VERSION 5.7 ;
  NOWIREEXTENSIONATPIN ON ;
  DIVIDERCHAR "/" ;
  BUSBITCHARS "[]" ;
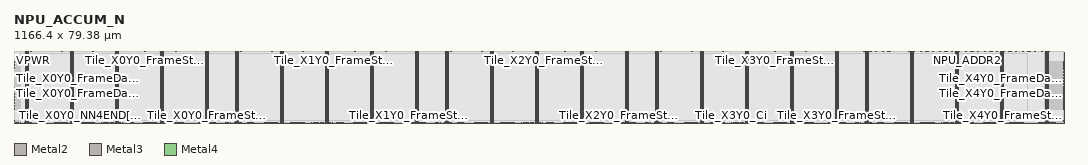
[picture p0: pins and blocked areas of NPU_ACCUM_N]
MACRO NPU_ACCUM_N
  CLASS BLOCK ;
  FOREIGN NPU_ACCUM_N ;
  ORIGIN 0.000 0.000 ;
  SIZE 1166.400 BY 79.380 ;
  PIN NPU_ADDR0
    DIRECTION OUTPUT ;
    USE SIGNAL ;
    ANTENNADIFFAREA 2.647800 ;
    PORT
      LAYER Metal2 ;
        RECT 1055.320 78.980 1055.720 79.380 ;
    END
  END NPU_ADDR0
  PIN NPU_ADDR1
    DIRECTION OUTPUT ;
    USE SIGNAL ;
    ANTENNADIFFAREA 2.647800 ;
    PORT
      LAYER Metal2 ;
        RECT 1057.240 78.980 1057.640 79.380 ;
    END
  END NPU_ADDR1
  PIN NPU_ADDR2
    DIRECTION OUTPUT ;
    USE SIGNAL ;
    ANTENNADIFFAREA 2.647800 ;
    PORT
      LAYER Metal2 ;
        RECT 1059.160 78.980 1059.560 79.380 ;
    END
  END NPU_ADDR2
  PIN NPU_ADDR3
    DIRECTION OUTPUT ;
    USE SIGNAL ;
    ANTENNADIFFAREA 2.647800 ;
    PORT
      LAYER Metal2 ;
        RECT 1061.080 78.980 1061.480 79.380 ;
    END
  END NPU_ADDR3
  PIN NPU_ADDR4
    DIRECTION OUTPUT ;
    USE SIGNAL ;
    ANTENNADIFFAREA 2.647800 ;
    PORT
      LAYER Metal2 ;
        RECT 1063.000 78.980 1063.400 79.380 ;
    END
  END NPU_ADDR4
  PIN NPU_ADDR5
    DIRECTION OUTPUT ;
    USE SIGNAL ;
    ANTENNADIFFAREA 2.647800 ;
    PORT
      LAYER Metal2 ;
        RECT 1064.920 78.980 1065.320 79.380 ;
    END
  END NPU_ADDR5
  PIN NPU_ADDR6
    DIRECTION OUTPUT ;
    USE SIGNAL ;
    ANTENNADIFFAREA 2.647800 ;
    PORT
      LAYER Metal2 ;
        RECT 1066.840 78.980 1067.240 79.380 ;
    END
  END NPU_ADDR6
  PIN NPU_ADDR7
    DIRECTION OUTPUT ;
    USE SIGNAL ;
    ANTENNADIFFAREA 2.647800 ;
    PORT
      LAYER Metal2 ;
        RECT 1068.760 78.980 1069.160 79.380 ;
    END
  END NPU_ADDR7
  PIN NPU_RDATA0
    DIRECTION INPUT ;
    USE SIGNAL ;
    ANTENNAGATEAREA 0.109200 ;
    ANTENNADIFFAREA 2.015400 ;
    PORT
      LAYER Metal2 ;
        RECT 993.880 78.980 994.280 79.380 ;
    END
  END NPU_RDATA0
  PIN NPU_RDATA1
    DIRECTION INPUT ;
    USE SIGNAL ;
    ANTENNAGATEAREA 0.109200 ;
    ANTENNADIFFAREA 2.015400 ;
    PORT
      LAYER Metal2 ;
        RECT 995.800 78.980 996.200 79.380 ;
    END
  END NPU_RDATA1
  PIN NPU_RDATA10
    DIRECTION INPUT ;
    USE SIGNAL ;
    ANTENNAGATEAREA 0.109200 ;
    ANTENNADIFFAREA 2.015400 ;
    PORT
      LAYER Metal2 ;
        RECT 1013.080 78.980 1013.480 79.380 ;
    END
  END NPU_RDATA10
  PIN NPU_RDATA11
    DIRECTION INPUT ;
    USE SIGNAL ;
    ANTENNAGATEAREA 0.109200 ;
    ANTENNADIFFAREA 2.015400 ;
    PORT
      LAYER Metal2 ;
        RECT 1015.000 78.980 1015.400 79.380 ;
    END
  END NPU_RDATA11
  PIN NPU_RDATA12
    DIRECTION INPUT ;
    USE SIGNAL ;
    ANTENNAGATEAREA 0.109200 ;
    ANTENNADIFFAREA 2.015400 ;
    PORT
      LAYER Metal2 ;
        RECT 1016.920 78.980 1017.320 79.380 ;
    END
  END NPU_RDATA12
  PIN NPU_RDATA13
    DIRECTION INPUT ;
    USE SIGNAL ;
    ANTENNAGATEAREA 0.109200 ;
    ANTENNADIFFAREA 2.015400 ;
    PORT
      LAYER Metal2 ;
        RECT 1018.840 78.980 1019.240 79.380 ;
    END
  END NPU_RDATA13
  PIN NPU_RDATA14
    DIRECTION INPUT ;
    USE SIGNAL ;
    ANTENNAGATEAREA 0.109200 ;
    ANTENNADIFFAREA 2.015400 ;
    PORT
      LAYER Metal2 ;
        RECT 1020.760 78.980 1021.160 79.380 ;
    END
  END NPU_RDATA14
  PIN NPU_RDATA15
    DIRECTION INPUT ;
    USE SIGNAL ;
    ANTENNAGATEAREA 0.109200 ;
    ANTENNADIFFAREA 2.015400 ;
    PORT
      LAYER Metal2 ;
        RECT 1022.680 78.980 1023.080 79.380 ;
    END
  END NPU_RDATA15
  PIN NPU_RDATA16
    DIRECTION INPUT ;
    USE SIGNAL ;
    ANTENNAGATEAREA 0.109200 ;
    ANTENNADIFFAREA 2.015400 ;
    PORT
      LAYER Metal2 ;
        RECT 1024.600 78.980 1025.000 79.380 ;
    END
  END NPU_RDATA16
  PIN NPU_RDATA17
    DIRECTION INPUT ;
    USE SIGNAL ;
    ANTENNAGATEAREA 0.109200 ;
    ANTENNADIFFAREA 2.015400 ;
    PORT
      LAYER Metal2 ;
        RECT 1026.520 78.980 1026.920 79.380 ;
    END
  END NPU_RDATA17
  PIN NPU_RDATA18
    DIRECTION INPUT ;
    USE SIGNAL ;
    ANTENNAGATEAREA 0.109200 ;
    ANTENNADIFFAREA 2.015400 ;
    PORT
      LAYER Metal2 ;
        RECT 1028.440 78.980 1028.840 79.380 ;
    END
  END NPU_RDATA18
  PIN NPU_RDATA19
    DIRECTION INPUT ;
    USE SIGNAL ;
    ANTENNAGATEAREA 0.109200 ;
    ANTENNADIFFAREA 2.015400 ;
    PORT
      LAYER Metal2 ;
        RECT 1030.360 78.980 1030.760 79.380 ;
    END
  END NPU_RDATA19
  PIN NPU_RDATA2
    DIRECTION INPUT ;
    USE SIGNAL ;
    ANTENNAGATEAREA 0.109200 ;
    ANTENNADIFFAREA 2.015400 ;
    PORT
      LAYER Metal2 ;
        RECT 997.720 78.980 998.120 79.380 ;
    END
  END NPU_RDATA2
  PIN NPU_RDATA20
    DIRECTION INPUT ;
    USE SIGNAL ;
    ANTENNAGATEAREA 0.109200 ;
    ANTENNADIFFAREA 2.015400 ;
    PORT
      LAYER Metal2 ;
        RECT 1032.280 78.980 1032.680 79.380 ;
    END
  END NPU_RDATA20
  PIN NPU_RDATA21
    DIRECTION INPUT ;
    USE SIGNAL ;
    ANTENNAGATEAREA 0.109200 ;
    ANTENNADIFFAREA 2.015400 ;
    PORT
      LAYER Metal2 ;
        RECT 1034.200 78.980 1034.600 79.380 ;
    END
  END NPU_RDATA21
  PIN NPU_RDATA22
    DIRECTION INPUT ;
    USE SIGNAL ;
    ANTENNAGATEAREA 0.109200 ;
    ANTENNADIFFAREA 2.015400 ;
    PORT
      LAYER Metal2 ;
        RECT 1036.120 78.980 1036.520 79.380 ;
    END
  END NPU_RDATA22
  PIN NPU_RDATA23
    DIRECTION INPUT ;
    USE SIGNAL ;
    ANTENNAGATEAREA 0.109200 ;
    ANTENNADIFFAREA 4.030800 ;
    PORT
      LAYER Metal2 ;
        RECT 1038.040 78.980 1038.440 79.380 ;
    END
  END NPU_RDATA23
  PIN NPU_RDATA24
    DIRECTION INPUT ;
    USE SIGNAL ;
    ANTENNAGATEAREA 0.109200 ;
    ANTENNADIFFAREA 6.046200 ;
    PORT
      LAYER Metal2 ;
        RECT 1039.960 78.980 1040.360 79.380 ;
    END
  END NPU_RDATA24
  PIN NPU_RDATA25
    DIRECTION INPUT ;
    USE SIGNAL ;
    ANTENNAGATEAREA 0.109200 ;
    ANTENNADIFFAREA 2.015400 ;
    PORT
      LAYER Metal2 ;
        RECT 1041.880 78.980 1042.280 79.380 ;
    END
  END NPU_RDATA25
  PIN NPU_RDATA26
    DIRECTION INPUT ;
    USE SIGNAL ;
    ANTENNAGATEAREA 0.109200 ;
    ANTENNADIFFAREA 6.046200 ;
    PORT
      LAYER Metal2 ;
        RECT 1043.800 78.980 1044.200 79.380 ;
    END
  END NPU_RDATA26
  PIN NPU_RDATA27
    DIRECTION INPUT ;
    USE SIGNAL ;
    ANTENNAGATEAREA 0.109200 ;
    ANTENNADIFFAREA 2.015400 ;
    PORT
      LAYER Metal2 ;
        RECT 1045.720 78.980 1046.120 79.380 ;
    END
  END NPU_RDATA27
  PIN NPU_RDATA28
    DIRECTION INPUT ;
    USE SIGNAL ;
    ANTENNAGATEAREA 0.109200 ;
    ANTENNADIFFAREA 2.015400 ;
    PORT
      LAYER Metal2 ;
        RECT 1047.640 78.980 1048.040 79.380 ;
    END
  END NPU_RDATA28
  PIN NPU_RDATA29
    DIRECTION INPUT ;
    USE SIGNAL ;
    ANTENNAGATEAREA 0.109200 ;
    ANTENNADIFFAREA 2.015400 ;
    PORT
      LAYER Metal2 ;
        RECT 1049.560 78.980 1049.960 79.380 ;
    END
  END NPU_RDATA29
  PIN NPU_RDATA3
    DIRECTION INPUT ;
    USE SIGNAL ;
    ANTENNAGATEAREA 0.109200 ;
    ANTENNADIFFAREA 2.015400 ;
    PORT
      LAYER Metal2 ;
        RECT 999.640 78.980 1000.040 79.380 ;
    END
  END NPU_RDATA3
  PIN NPU_RDATA30
    DIRECTION INPUT ;
    USE SIGNAL ;
    ANTENNAGATEAREA 0.109200 ;
    ANTENNADIFFAREA 2.015400 ;
    PORT
      LAYER Metal2 ;
        RECT 1051.480 78.980 1051.880 79.380 ;
    END
  END NPU_RDATA30
  PIN NPU_RDATA31
    DIRECTION INPUT ;
    USE SIGNAL ;
    ANTENNAGATEAREA 0.109200 ;
    ANTENNADIFFAREA 2.015400 ;
    PORT
      LAYER Metal2 ;
        RECT 1053.400 78.980 1053.800 79.380 ;
    END
  END NPU_RDATA31
  PIN NPU_RDATA4
    DIRECTION INPUT ;
    USE SIGNAL ;
    ANTENNAGATEAREA 0.109200 ;
    ANTENNADIFFAREA 2.015400 ;
    PORT
      LAYER Metal2 ;
        RECT 1001.560 78.980 1001.960 79.380 ;
    END
  END NPU_RDATA4
  PIN NPU_RDATA5
    DIRECTION INPUT ;
    USE SIGNAL ;
    ANTENNAGATEAREA 0.109200 ;
    ANTENNADIFFAREA 2.015400 ;
    PORT
      LAYER Metal2 ;
        RECT 1003.480 78.980 1003.880 79.380 ;
    END
  END NPU_RDATA5
  PIN NPU_RDATA6
    DIRECTION INPUT ;
    USE SIGNAL ;
    ANTENNAGATEAREA 0.109200 ;
    ANTENNADIFFAREA 2.015400 ;
    PORT
      LAYER Metal2 ;
        RECT 1005.400 78.980 1005.800 79.380 ;
    END
  END NPU_RDATA6
  PIN NPU_RDATA7
    DIRECTION INPUT ;
    USE SIGNAL ;
    ANTENNAGATEAREA 0.109200 ;
    ANTENNADIFFAREA 6.046200 ;
    PORT
      LAYER Metal2 ;
        RECT 1007.320 78.980 1007.720 79.380 ;
    END
  END NPU_RDATA7
  PIN NPU_RDATA8
    DIRECTION INPUT ;
    USE SIGNAL ;
    ANTENNAGATEAREA 0.109200 ;
    ANTENNADIFFAREA 2.015400 ;
    PORT
      LAYER Metal2 ;
        RECT 1009.240 78.980 1009.640 79.380 ;
    END
  END NPU_RDATA8
  PIN NPU_RDATA9
    DIRECTION INPUT ;
    USE SIGNAL ;
    ANTENNAGATEAREA 0.109200 ;
    ANTENNADIFFAREA 6.046200 ;
    PORT
      LAYER Metal2 ;
        RECT 1011.160 78.980 1011.560 79.380 ;
    END
  END NPU_RDATA9
  PIN NPU_READ_BANK_SEL0
    DIRECTION OUTPUT ;
    USE SIGNAL ;
    ANTENNADIFFAREA 2.647800 ;
    PORT
      LAYER Metal2 ;
        RECT 1147.480 78.980 1147.880 79.380 ;
    END
  END NPU_READ_BANK_SEL0
  PIN NPU_READ_BANK_SEL1
    DIRECTION OUTPUT ;
    USE SIGNAL ;
    ANTENNADIFFAREA 2.647800 ;
    PORT
      LAYER Metal2 ;
        RECT 1149.400 78.980 1149.800 79.380 ;
    END
  END NPU_READ_BANK_SEL1
  PIN NPU_READ_BANK_SEL2
    DIRECTION OUTPUT ;
    USE SIGNAL ;
    ANTENNADIFFAREA 2.647800 ;
    PORT
      LAYER Metal2 ;
        RECT 1151.320 78.980 1151.720 79.380 ;
    END
  END NPU_READ_BANK_SEL2
  PIN NPU_WDATA0
    DIRECTION OUTPUT ;
    USE SIGNAL ;
    ANTENNADIFFAREA 2.647800 ;
    PORT
      LAYER Metal2 ;
        RECT 1086.040 78.980 1086.440 79.380 ;
    END
  END NPU_WDATA0
  PIN NPU_WDATA1
    DIRECTION OUTPUT ;
    USE SIGNAL ;
    ANTENNADIFFAREA 2.647800 ;
    PORT
      LAYER Metal2 ;
        RECT 1087.960 78.980 1088.360 79.380 ;
    END
  END NPU_WDATA1
  PIN NPU_WDATA10
    DIRECTION OUTPUT ;
    USE SIGNAL ;
    ANTENNADIFFAREA 2.647800 ;
    PORT
      LAYER Metal2 ;
        RECT 1105.240 78.980 1105.640 79.380 ;
    END
  END NPU_WDATA10
  PIN NPU_WDATA11
    DIRECTION OUTPUT ;
    USE SIGNAL ;
    ANTENNADIFFAREA 2.647800 ;
    PORT
      LAYER Metal2 ;
        RECT 1107.160 78.980 1107.560 79.380 ;
    END
  END NPU_WDATA11
  PIN NPU_WDATA12
    DIRECTION OUTPUT ;
    USE SIGNAL ;
    ANTENNADIFFAREA 2.647800 ;
    PORT
      LAYER Metal2 ;
        RECT 1109.080 78.980 1109.480 79.380 ;
    END
  END NPU_WDATA12
  PIN NPU_WDATA13
    DIRECTION OUTPUT ;
    USE SIGNAL ;
    ANTENNADIFFAREA 2.647800 ;
    PORT
      LAYER Metal2 ;
        RECT 1111.000 78.980 1111.400 79.380 ;
    END
  END NPU_WDATA13
  PIN NPU_WDATA14
    DIRECTION OUTPUT ;
    USE SIGNAL ;
    ANTENNADIFFAREA 2.647800 ;
    PORT
      LAYER Metal2 ;
        RECT 1112.920 78.980 1113.320 79.380 ;
    END
  END NPU_WDATA14
  PIN NPU_WDATA15
    DIRECTION OUTPUT ;
    USE SIGNAL ;
    ANTENNADIFFAREA 2.647800 ;
    PORT
      LAYER Metal2 ;
        RECT 1114.840 78.980 1115.240 79.380 ;
    END
  END NPU_WDATA15
  PIN NPU_WDATA16
    DIRECTION OUTPUT ;
    USE SIGNAL ;
    ANTENNADIFFAREA 2.647800 ;
    PORT
      LAYER Metal2 ;
        RECT 1116.760 78.980 1117.160 79.380 ;
    END
  END NPU_WDATA16
  PIN NPU_WDATA17
    DIRECTION OUTPUT ;
    USE SIGNAL ;
    ANTENNADIFFAREA 2.647800 ;
    PORT
      LAYER Metal2 ;
        RECT 1118.680 78.980 1119.080 79.380 ;
    END
  END NPU_WDATA17
  PIN NPU_WDATA18
    DIRECTION OUTPUT ;
    USE SIGNAL ;
    ANTENNADIFFAREA 2.647800 ;
    PORT
      LAYER Metal2 ;
        RECT 1120.600 78.980 1121.000 79.380 ;
    END
  END NPU_WDATA18
  PIN NPU_WDATA19
    DIRECTION OUTPUT ;
    USE SIGNAL ;
    ANTENNADIFFAREA 2.647800 ;
    PORT
      LAYER Metal2 ;
        RECT 1122.520 78.980 1122.920 79.380 ;
    END
  END NPU_WDATA19
  PIN NPU_WDATA2
    DIRECTION OUTPUT ;
    USE SIGNAL ;
    ANTENNADIFFAREA 2.647800 ;
    PORT
      LAYER Metal2 ;
        RECT 1089.880 78.980 1090.280 79.380 ;
    END
  END NPU_WDATA2
  PIN NPU_WDATA20
    DIRECTION OUTPUT ;
    USE SIGNAL ;
    ANTENNADIFFAREA 2.647800 ;
    PORT
      LAYER Metal2 ;
        RECT 1124.440 78.980 1124.840 79.380 ;
    END
  END NPU_WDATA20
  PIN NPU_WDATA21
    DIRECTION OUTPUT ;
    USE SIGNAL ;
    ANTENNADIFFAREA 2.647800 ;
    PORT
      LAYER Metal2 ;
        RECT 1126.360 78.980 1126.760 79.380 ;
    END
  END NPU_WDATA21
  PIN NPU_WDATA22
    DIRECTION OUTPUT ;
    USE SIGNAL ;
    ANTENNADIFFAREA 2.647800 ;
    PORT
      LAYER Metal2 ;
        RECT 1128.280 78.980 1128.680 79.380 ;
    END
  END NPU_WDATA22
  PIN NPU_WDATA23
    DIRECTION OUTPUT ;
    USE SIGNAL ;
    ANTENNADIFFAREA 2.647800 ;
    PORT
      LAYER Metal2 ;
        RECT 1130.200 78.980 1130.600 79.380 ;
    END
  END NPU_WDATA23
  PIN NPU_WDATA24
    DIRECTION OUTPUT ;
    USE SIGNAL ;
    ANTENNADIFFAREA 2.647800 ;
    PORT
      LAYER Metal2 ;
        RECT 1132.120 78.980 1132.520 79.380 ;
    END
  END NPU_WDATA24
  PIN NPU_WDATA25
    DIRECTION OUTPUT ;
    USE SIGNAL ;
    ANTENNADIFFAREA 2.647800 ;
    PORT
      LAYER Metal2 ;
        RECT 1134.040 78.980 1134.440 79.380 ;
    END
  END NPU_WDATA25
  PIN NPU_WDATA26
    DIRECTION OUTPUT ;
    USE SIGNAL ;
    ANTENNADIFFAREA 2.647800 ;
    PORT
      LAYER Metal2 ;
        RECT 1135.960 78.980 1136.360 79.380 ;
    END
  END NPU_WDATA26
  PIN NPU_WDATA27
    DIRECTION OUTPUT ;
    USE SIGNAL ;
    ANTENNADIFFAREA 2.647800 ;
    PORT
      LAYER Metal2 ;
        RECT 1137.880 78.980 1138.280 79.380 ;
    END
  END NPU_WDATA27
  PIN NPU_WDATA28
    DIRECTION OUTPUT ;
    USE SIGNAL ;
    ANTENNADIFFAREA 2.647800 ;
    PORT
      LAYER Metal2 ;
        RECT 1139.800 78.980 1140.200 79.380 ;
    END
  END NPU_WDATA28
  PIN NPU_WDATA29
    DIRECTION OUTPUT ;
    USE SIGNAL ;
    ANTENNADIFFAREA 2.647800 ;
    PORT
      LAYER Metal2 ;
        RECT 1141.720 78.980 1142.120 79.380 ;
    END
  END NPU_WDATA29
  PIN NPU_WDATA3
    DIRECTION OUTPUT ;
    USE SIGNAL ;
    ANTENNADIFFAREA 2.647800 ;
    PORT
      LAYER Metal2 ;
        RECT 1091.800 78.980 1092.200 79.380 ;
    END
  END NPU_WDATA3
  PIN NPU_WDATA30
    DIRECTION OUTPUT ;
    USE SIGNAL ;
    ANTENNADIFFAREA 2.647800 ;
    PORT
      LAYER Metal2 ;
        RECT 1143.640 78.980 1144.040 79.380 ;
    END
  END NPU_WDATA30
  PIN NPU_WDATA31
    DIRECTION OUTPUT ;
    USE SIGNAL ;
    ANTENNADIFFAREA 2.647800 ;
    PORT
      LAYER Metal2 ;
        RECT 1145.560 78.980 1145.960 79.380 ;
    END
  END NPU_WDATA31
  PIN NPU_WDATA4
    DIRECTION OUTPUT ;
    USE SIGNAL ;
    ANTENNADIFFAREA 2.647800 ;
    PORT
      LAYER Metal2 ;
        RECT 1093.720 78.980 1094.120 79.380 ;
    END
  END NPU_WDATA4
  PIN NPU_WDATA5
    DIRECTION OUTPUT ;
    USE SIGNAL ;
    ANTENNADIFFAREA 2.647800 ;
    PORT
      LAYER Metal2 ;
        RECT 1095.640 78.980 1096.040 79.380 ;
    END
  END NPU_WDATA5
  PIN NPU_WDATA6
    DIRECTION OUTPUT ;
    USE SIGNAL ;
    ANTENNADIFFAREA 2.647800 ;
    PORT
      LAYER Metal2 ;
        RECT 1097.560 78.980 1097.960 79.380 ;
    END
  END NPU_WDATA6
  PIN NPU_WDATA7
    DIRECTION OUTPUT ;
    USE SIGNAL ;
    ANTENNADIFFAREA 2.647800 ;
    PORT
      LAYER Metal2 ;
        RECT 1099.480 78.980 1099.880 79.380 ;
    END
  END NPU_WDATA7
  PIN NPU_WDATA8
    DIRECTION OUTPUT ;
    USE SIGNAL ;
    ANTENNADIFFAREA 2.647800 ;
    PORT
      LAYER Metal2 ;
        RECT 1101.400 78.980 1101.800 79.380 ;
    END
  END NPU_WDATA8
  PIN NPU_WDATA9
    DIRECTION OUTPUT ;
    USE SIGNAL ;
    ANTENNADIFFAREA 2.647800 ;
    PORT
      LAYER Metal2 ;
        RECT 1103.320 78.980 1103.720 79.380 ;
    END
  END NPU_WDATA9
  PIN NPU_WE0
    DIRECTION OUTPUT ;
    USE SIGNAL ;
    ANTENNADIFFAREA 2.647800 ;
    PORT
      LAYER Metal2 ;
        RECT 1070.680 78.980 1071.080 79.380 ;
    END
  END NPU_WE0
  PIN NPU_WE1
    DIRECTION OUTPUT ;
    USE SIGNAL ;
    ANTENNADIFFAREA 2.647800 ;
    PORT
      LAYER Metal2 ;
        RECT 1072.600 78.980 1073.000 79.380 ;
    END
  END NPU_WE1
  PIN NPU_WE2
    DIRECTION OUTPUT ;
    USE SIGNAL ;
    ANTENNADIFFAREA 2.647800 ;
    PORT
      LAYER Metal2 ;
        RECT 1074.520 78.980 1074.920 79.380 ;
    END
  END NPU_WE2
  PIN NPU_WE3
    DIRECTION OUTPUT ;
    USE SIGNAL ;
    ANTENNADIFFAREA 2.647800 ;
    PORT
      LAYER Metal2 ;
        RECT 1076.440 78.980 1076.840 79.380 ;
    END
  END NPU_WE3
  PIN NPU_WE4
    DIRECTION OUTPUT ;
    USE SIGNAL ;
    ANTENNADIFFAREA 2.647800 ;
    PORT
      LAYER Metal2 ;
        RECT 1078.360 78.980 1078.760 79.380 ;
    END
  END NPU_WE4
  PIN NPU_WE5
    DIRECTION OUTPUT ;
    USE SIGNAL ;
    ANTENNADIFFAREA 2.647800 ;
    PORT
      LAYER Metal2 ;
        RECT 1080.280 78.980 1080.680 79.380 ;
    END
  END NPU_WE5
  PIN NPU_WE6
    DIRECTION OUTPUT ;
    USE SIGNAL ;
    ANTENNADIFFAREA 2.647800 ;
    PORT
      LAYER Metal2 ;
        RECT 1082.200 78.980 1082.600 79.380 ;
    END
  END NPU_WE6
  PIN NPU_WE7
    DIRECTION OUTPUT ;
    USE SIGNAL ;
    ANTENNADIFFAREA 2.647800 ;
    PORT
      LAYER Metal2 ;
        RECT 1084.120 78.980 1084.520 79.380 ;
    END
  END NPU_WE7
  PIN Tile_X0Y0_Ci
    DIRECTION INPUT ;
    USE SIGNAL ;
    PORT
      LAYER Metal2 ;
        RECT 97.240 0.000 97.640 0.400 ;
    END
  END Tile_X0Y0_Ci
  PIN Tile_X0Y0_FrameData[0]
    DIRECTION INPUT ;
    USE SIGNAL ;
    ANTENNAGATEAREA 2.349100 ;
    ANTENNADIFFAREA 314.402405 ;
    PORT
      LAYER Metal3 ;
        RECT 0.000 15.340 0.400 15.740 ;
    END
  END Tile_X0Y0_FrameData[0]
  PIN Tile_X0Y0_FrameData[10]
    DIRECTION INPUT ;
    USE SIGNAL ;
    ANTENNAGATEAREA 2.349100 ;
    ANTENNADIFFAREA 78.600601 ;
    PORT
      LAYER Metal3 ;
        RECT 0.000 32.140 0.400 32.540 ;
    END
  END Tile_X0Y0_FrameData[10]
  PIN Tile_X0Y0_FrameData[11]
    DIRECTION INPUT ;
    USE SIGNAL ;
    ANTENNAGATEAREA 2.349100 ;
    ANTENNADIFFAREA 131.000992 ;
    PORT
      LAYER Metal3 ;
        RECT 0.000 33.820 0.400 34.220 ;
    END
  END Tile_X0Y0_FrameData[11]
  PIN Tile_X0Y0_FrameData[12]
    DIRECTION INPUT ;
    USE SIGNAL ;
    ANTENNAGATEAREA 2.349100 ;
    ANTENNADIFFAREA 26.200199 ;
    PORT
      LAYER Metal3 ;
        RECT 0.000 35.500 0.400 35.900 ;
    END
  END Tile_X0Y0_FrameData[12]
  PIN Tile_X0Y0_FrameData[13]
    DIRECTION INPUT ;
    USE SIGNAL ;
    ANTENNAGATEAREA 2.349100 ;
    ANTENNADIFFAREA 350.679596 ;
    PORT
      LAYER Metal3 ;
        RECT 0.000 37.180 0.400 37.580 ;
    END
  END Tile_X0Y0_FrameData[13]
  PIN Tile_X0Y0_FrameData[14]
    DIRECTION INPUT ;
    USE SIGNAL ;
    ANTENNAGATEAREA 2.349100 ;
    ANTENNADIFFAREA 235.801788 ;
    PORT
      LAYER Metal3 ;
        RECT 0.000 38.860 0.400 39.260 ;
    END
  END Tile_X0Y0_FrameData[14]
  PIN Tile_X0Y0_FrameData[15]
    DIRECTION INPUT ;
    USE SIGNAL ;
    ANTENNAGATEAREA 2.349100 ;
    ANTENNADIFFAREA 340.602600 ;
    PORT
      LAYER Metal3 ;
        RECT 0.000 40.540 0.400 40.940 ;
    END
  END Tile_X0Y0_FrameData[15]
  PIN Tile_X0Y0_FrameData[16]
    DIRECTION INPUT ;
    USE SIGNAL ;
    ANTENNAGATEAREA 2.710500 ;
    ANTENNADIFFAREA 362.772003 ;
    PORT
      LAYER Metal3 ;
        RECT 0.000 42.220 0.400 42.620 ;
    END
  END Tile_X0Y0_FrameData[16]
  PIN Tile_X0Y0_FrameData[17]
    DIRECTION INPUT ;
    USE SIGNAL ;
    ANTENNAGATEAREA 2.710500 ;
    ANTENNADIFFAREA 453.464996 ;
    PORT
      LAYER Metal3 ;
        RECT 0.000 43.900 0.400 44.300 ;
    END
  END Tile_X0Y0_FrameData[17]
  PIN Tile_X0Y0_FrameData[18]
    DIRECTION INPUT ;
    USE SIGNAL ;
    ANTENNAGATEAREA 2.891200 ;
    ANTENNADIFFAREA 322.463989 ;
    PORT
      LAYER Metal3 ;
        RECT 0.000 45.580 0.400 45.980 ;
    END
  END Tile_X0Y0_FrameData[18]
  PIN Tile_X0Y0_FrameData[19]
    DIRECTION INPUT ;
    USE SIGNAL ;
    ANTENNAGATEAREA 2.891200 ;
    ANTENNADIFFAREA 515.942383 ;
    PORT
      LAYER Metal3 ;
        RECT 0.000 47.260 0.400 47.660 ;
    END
  END Tile_X0Y0_FrameData[19]
  PIN Tile_X0Y0_FrameData[1]
    DIRECTION INPUT ;
    USE SIGNAL ;
    ANTENNAGATEAREA 2.349100 ;
    ANTENNADIFFAREA 316.417786 ;
    PORT
      LAYER Metal3 ;
        RECT 0.000 17.020 0.400 17.420 ;
    END
  END Tile_X0Y0_FrameData[1]
  PIN Tile_X0Y0_FrameData[20]
    DIRECTION INPUT ;
    USE SIGNAL ;
    ANTENNAGATEAREA 2.891200 ;
    ANTENNADIFFAREA 515.942383 ;
    PORT
      LAYER Metal3 ;
        RECT 0.000 48.940 0.400 49.340 ;
    END
  END Tile_X0Y0_FrameData[20]
  PIN Tile_X0Y0_FrameData[21]
    DIRECTION INPUT ;
    USE SIGNAL ;
    ANTENNAGATEAREA 2.891200 ;
    ANTENNADIFFAREA 163.247391 ;
    PORT
      LAYER Metal3 ;
        RECT 0.000 50.620 0.400 51.020 ;
    END
  END Tile_X0Y0_FrameData[21]
  PIN Tile_X0Y0_FrameData[22]
    DIRECTION INPUT ;
    USE SIGNAL ;
    ANTENNAGATEAREA 2.891200 ;
    ANTENNADIFFAREA 290.217590 ;
    PORT
      LAYER Metal3 ;
        RECT 0.000 52.300 0.400 52.700 ;
    END
  END Tile_X0Y0_FrameData[22]
  PIN Tile_X0Y0_FrameData[23]
    DIRECTION INPUT ;
    USE SIGNAL ;
    ANTENNAGATEAREA 2.891200 ;
    ANTENNADIFFAREA 419.203186 ;
    PORT
      LAYER Metal3 ;
        RECT 0.000 53.980 0.400 54.380 ;
    END
  END Tile_X0Y0_FrameData[23]
  PIN Tile_X0Y0_FrameData[24]
    DIRECTION INPUT ;
    USE SIGNAL ;
    ANTENNAGATEAREA 2.891200 ;
    ANTENNADIFFAREA 128.985596 ;
    PORT
      LAYER Metal3 ;
        RECT 0.000 55.660 0.400 56.060 ;
    END
  END Tile_X0Y0_FrameData[24]
  PIN Tile_X0Y0_FrameData[25]
    DIRECTION INPUT ;
    USE SIGNAL ;
    ANTENNAGATEAREA 2.891200 ;
    ANTENNADIFFAREA 515.942383 ;
    PORT
      LAYER Metal3 ;
        RECT 0.000 57.340 0.400 57.740 ;
    END
  END Tile_X0Y0_FrameData[25]
  PIN Tile_X0Y0_FrameData[26]
    DIRECTION INPUT ;
    USE SIGNAL ;
    ANTENNAGATEAREA 2.891200 ;
    ANTENNADIFFAREA 515.942383 ;
    PORT
      LAYER Metal3 ;
        RECT 0.000 59.020 0.400 59.420 ;
    END
  END Tile_X0Y0_FrameData[26]
  PIN Tile_X0Y0_FrameData[27]
    DIRECTION INPUT ;
    USE SIGNAL ;
    ANTENNAGATEAREA 2.891200 ;
    ANTENNADIFFAREA 32.246399 ;
    PORT
      LAYER Metal3 ;
        RECT 0.000 60.700 0.400 61.100 ;
    END
  END Tile_X0Y0_FrameData[27]
  PIN Tile_X0Y0_FrameData[28]
    DIRECTION INPUT ;
    USE SIGNAL ;
    ANTENNAGATEAREA 2.891200 ;
    ANTENNADIFFAREA 386.956787 ;
    PORT
      LAYER Metal3 ;
        RECT 0.000 62.380 0.400 62.780 ;
    END
  END Tile_X0Y0_FrameData[28]
  PIN Tile_X0Y0_FrameData[29]
    DIRECTION INPUT ;
    USE SIGNAL ;
    ANTENNAGATEAREA 2.891200 ;
    ANTENNADIFFAREA 386.956787 ;
    PORT
      LAYER Metal3 ;
        RECT 0.000 64.060 0.400 64.460 ;
    END
  END Tile_X0Y0_FrameData[29]
  PIN Tile_X0Y0_FrameData[2]
    DIRECTION INPUT ;
    USE SIGNAL ;
    ANTENNAGATEAREA 2.349100 ;
    ANTENNADIFFAREA 78.600601 ;
    PORT
      LAYER Metal3 ;
        RECT 0.000 18.700 0.400 19.100 ;
    END
  END Tile_X0Y0_FrameData[2]
  PIN Tile_X0Y0_FrameData[30]
    DIRECTION INPUT ;
    USE SIGNAL ;
    ANTENNAGATEAREA 2.891200 ;
    ANTENNADIFFAREA 128.985596 ;
    PORT
      LAYER Metal3 ;
        RECT 0.000 65.740 0.400 66.140 ;
    END
  END Tile_X0Y0_FrameData[30]
  PIN Tile_X0Y0_FrameData[31]
    DIRECTION INPUT ;
    USE SIGNAL ;
    ANTENNAGATEAREA 2.891200 ;
    ANTENNADIFFAREA 515.942383 ;
    PORT
      LAYER Metal3 ;
        RECT 0.000 67.420 0.400 67.820 ;
    END
  END Tile_X0Y0_FrameData[31]
  PIN Tile_X0Y0_FrameData[3]
    DIRECTION INPUT ;
    USE SIGNAL ;
    ANTENNAGATEAREA 2.349100 ;
    ANTENNADIFFAREA 78.600601 ;
    PORT
      LAYER Metal3 ;
        RECT 0.000 20.380 0.400 20.780 ;
    END
  END Tile_X0Y0_FrameData[3]
  PIN Tile_X0Y0_FrameData[4]
    DIRECTION INPUT ;
    USE SIGNAL ;
    ANTENNAGATEAREA 2.349100 ;
    ANTENNADIFFAREA 30.230999 ;
    PORT
      LAYER Metal3 ;
        RECT 0.000 22.060 0.400 22.460 ;
    END
  END Tile_X0Y0_FrameData[4]
  PIN Tile_X0Y0_FrameData[5]
    DIRECTION INPUT ;
    USE SIGNAL ;
    ANTENNAGATEAREA 2.349100 ;
    ANTENNADIFFAREA 340.602600 ;
    PORT
      LAYER Metal3 ;
        RECT 0.000 23.740 0.400 24.140 ;
    END
  END Tile_X0Y0_FrameData[5]
  PIN Tile_X0Y0_FrameData[6]
    DIRECTION INPUT ;
    USE SIGNAL ;
    ANTENNAGATEAREA 2.349100 ;
    ANTENNADIFFAREA 340.602600 ;
    PORT
      LAYER Metal3 ;
        RECT 0.000 25.420 0.400 25.820 ;
    END
  END Tile_X0Y0_FrameData[6]
  PIN Tile_X0Y0_FrameData[7]
    DIRECTION INPUT ;
    USE SIGNAL ;
    ANTENNAGATEAREA 2.349100 ;
    ANTENNADIFFAREA 340.602600 ;
    PORT
      LAYER Metal3 ;
        RECT 0.000 27.100 0.400 27.500 ;
    END
  END Tile_X0Y0_FrameData[7]
  PIN Tile_X0Y0_FrameData[8]
    DIRECTION INPUT ;
    USE SIGNAL ;
    ANTENNAGATEAREA 2.349100 ;
    ANTENNADIFFAREA 314.402405 ;
    PORT
      LAYER Metal3 ;
        RECT 0.000 28.780 0.400 29.180 ;
    END
  END Tile_X0Y0_FrameData[8]
  PIN Tile_X0Y0_FrameData[9]
    DIRECTION INPUT ;
    USE SIGNAL ;
    ANTENNAGATEAREA 2.349100 ;
    ANTENNADIFFAREA 340.602600 ;
    PORT
      LAYER Metal3 ;
        RECT 0.000 30.460 0.400 30.860 ;
    END
  END Tile_X0Y0_FrameData[9]
  PIN Tile_X0Y0_FrameStrobe[0]
    DIRECTION INPUT ;
    USE SIGNAL ;
    ANTENNAGATEAREA 11.745500 ;
    PORT
      LAYER Metal2 ;
        RECT 204.760 0.000 205.160 0.400 ;
    END
  END Tile_X0Y0_FrameStrobe[0]
  PIN Tile_X0Y0_FrameStrobe[10]
    DIRECTION INPUT ;
    USE SIGNAL ;
    ANTENNAGATEAREA 0.180700 ;
    PORT
      LAYER Metal2 ;
        RECT 214.360 0.000 214.760 0.400 ;
    END
  END Tile_X0Y0_FrameStrobe[10]
  PIN Tile_X0Y0_FrameStrobe[11]
    DIRECTION INPUT ;
    USE SIGNAL ;
    ANTENNAGATEAREA 0.180700 ;
    PORT
      LAYER Metal2 ;
        RECT 215.320 0.000 215.720 0.400 ;
    END
  END Tile_X0Y0_FrameStrobe[11]
  PIN Tile_X0Y0_FrameStrobe[12]
    DIRECTION INPUT ;
    USE SIGNAL ;
    ANTENNAGATEAREA 0.180700 ;
    PORT
      LAYER Metal2 ;
        RECT 216.280 0.000 216.680 0.400 ;
    END
  END Tile_X0Y0_FrameStrobe[12]
  PIN Tile_X0Y0_FrameStrobe[13]
    DIRECTION INPUT ;
    USE SIGNAL ;
    ANTENNAGATEAREA 0.180700 ;
    PORT
      LAYER Metal2 ;
        RECT 217.240 0.000 217.640 0.400 ;
    END
  END Tile_X0Y0_FrameStrobe[13]
  PIN Tile_X0Y0_FrameStrobe[14]
    DIRECTION INPUT ;
    USE SIGNAL ;
    ANTENNAGATEAREA 0.180700 ;
    PORT
      LAYER Metal2 ;
        RECT 218.200 0.000 218.600 0.400 ;
    END
  END Tile_X0Y0_FrameStrobe[14]
  PIN Tile_X0Y0_FrameStrobe[15]
    DIRECTION INPUT ;
    USE SIGNAL ;
    ANTENNAGATEAREA 0.180700 ;
    PORT
      LAYER Metal2 ;
        RECT 219.160 0.000 219.560 0.400 ;
    END
  END Tile_X0Y0_FrameStrobe[15]
  PIN Tile_X0Y0_FrameStrobe[16]
    DIRECTION INPUT ;
    USE SIGNAL ;
    ANTENNAGATEAREA 0.180700 ;
    PORT
      LAYER Metal2 ;
        RECT 220.120 0.000 220.520 0.400 ;
    END
  END Tile_X0Y0_FrameStrobe[16]
  PIN Tile_X0Y0_FrameStrobe[17]
    DIRECTION INPUT ;
    USE SIGNAL ;
    ANTENNAGATEAREA 0.180700 ;
    PORT
      LAYER Metal2 ;
        RECT 221.080 0.000 221.480 0.400 ;
    END
  END Tile_X0Y0_FrameStrobe[17]
  PIN Tile_X0Y0_FrameStrobe[18]
    DIRECTION INPUT ;
    USE SIGNAL ;
    ANTENNAGATEAREA 0.180700 ;
    PORT
      LAYER Metal2 ;
        RECT 222.040 0.000 222.440 0.400 ;
    END
  END Tile_X0Y0_FrameStrobe[18]
  PIN Tile_X0Y0_FrameStrobe[19]
    DIRECTION INPUT ;
    USE SIGNAL ;
    ANTENNAGATEAREA 0.180700 ;
    PORT
      LAYER Metal2 ;
        RECT 223.000 0.000 223.400 0.400 ;
    END
  END Tile_X0Y0_FrameStrobe[19]
  PIN Tile_X0Y0_FrameStrobe[1]
    DIRECTION INPUT ;
    USE SIGNAL ;
    ANTENNAGATEAREA 11.745500 ;
    PORT
      LAYER Metal2 ;
        RECT 205.720 0.000 206.120 0.400 ;
    END
  END Tile_X0Y0_FrameStrobe[1]
  PIN Tile_X0Y0_FrameStrobe[2]
    DIRECTION INPUT ;
    USE SIGNAL ;
    ANTENNAGATEAREA 11.745500 ;
    PORT
      LAYER Metal2 ;
        RECT 206.680 0.000 207.080 0.400 ;
    END
  END Tile_X0Y0_FrameStrobe[2]
  PIN Tile_X0Y0_FrameStrobe[3]
    DIRECTION INPUT ;
    USE SIGNAL ;
    ANTENNAGATEAREA 5.963100 ;
    PORT
      LAYER Metal2 ;
        RECT 207.640 0.000 208.040 0.400 ;
    END
  END Tile_X0Y0_FrameStrobe[3]
  PIN Tile_X0Y0_FrameStrobe[4]
    DIRECTION INPUT ;
    USE SIGNAL ;
    ANTENNAGATEAREA 0.180700 ;
    PORT
      LAYER Metal2 ;
        RECT 208.600 0.000 209.000 0.400 ;
    END
  END Tile_X0Y0_FrameStrobe[4]
  PIN Tile_X0Y0_FrameStrobe[5]
    DIRECTION INPUT ;
    USE SIGNAL ;
    ANTENNAGATEAREA 0.180700 ;
    PORT
      LAYER Metal2 ;
        RECT 209.560 0.000 209.960 0.400 ;
    END
  END Tile_X0Y0_FrameStrobe[5]
  PIN Tile_X0Y0_FrameStrobe[6]
    DIRECTION INPUT ;
    USE SIGNAL ;
    ANTENNAGATEAREA 0.180700 ;
    PORT
      LAYER Metal2 ;
        RECT 210.520 0.000 210.920 0.400 ;
    END
  END Tile_X0Y0_FrameStrobe[6]
  PIN Tile_X0Y0_FrameStrobe[7]
    DIRECTION INPUT ;
    USE SIGNAL ;
    ANTENNAGATEAREA 0.180700 ;
    PORT
      LAYER Metal2 ;
        RECT 211.480 0.000 211.880 0.400 ;
    END
  END Tile_X0Y0_FrameStrobe[7]
  PIN Tile_X0Y0_FrameStrobe[8]
    DIRECTION INPUT ;
    USE SIGNAL ;
    ANTENNAGATEAREA 0.180700 ;
    PORT
      LAYER Metal2 ;
        RECT 212.440 0.000 212.840 0.400 ;
    END
  END Tile_X0Y0_FrameStrobe[8]
  PIN Tile_X0Y0_FrameStrobe[9]
    DIRECTION INPUT ;
    USE SIGNAL ;
    ANTENNAGATEAREA 0.180700 ;
    PORT
      LAYER Metal2 ;
        RECT 213.400 0.000 213.800 0.400 ;
    END
  END Tile_X0Y0_FrameStrobe[9]
  PIN Tile_X0Y0_FrameStrobe_O[0]
    DIRECTION OUTPUT ;
    USE SIGNAL ;
    ANTENNADIFFAREA 2.724000 ;
    PORT
      LAYER Metal2 ;
        RECT 7.000 78.980 7.400 79.380 ;
    END
  END Tile_X0Y0_FrameStrobe_O[0]
  PIN Tile_X0Y0_FrameStrobe_O[10]
    DIRECTION OUTPUT ;
    USE SIGNAL ;
    ANTENNADIFFAREA 2.724000 ;
    PORT
      LAYER Metal2 ;
        RECT 122.200 78.980 122.600 79.380 ;
    END
  END Tile_X0Y0_FrameStrobe_O[10]
  PIN Tile_X0Y0_FrameStrobe_O[11]
    DIRECTION OUTPUT ;
    USE SIGNAL ;
    ANTENNADIFFAREA 2.724000 ;
    PORT
      LAYER Metal2 ;
        RECT 133.720 78.980 134.120 79.380 ;
    END
  END Tile_X0Y0_FrameStrobe_O[11]
  PIN Tile_X0Y0_FrameStrobe_O[12]
    DIRECTION OUTPUT ;
    USE SIGNAL ;
    ANTENNADIFFAREA 2.724000 ;
    PORT
      LAYER Metal2 ;
        RECT 145.240 78.980 145.640 79.380 ;
    END
  END Tile_X0Y0_FrameStrobe_O[12]
  PIN Tile_X0Y0_FrameStrobe_O[13]
    DIRECTION OUTPUT ;
    USE SIGNAL ;
    ANTENNADIFFAREA 2.724000 ;
    PORT
      LAYER Metal2 ;
        RECT 156.760 78.980 157.160 79.380 ;
    END
  END Tile_X0Y0_FrameStrobe_O[13]
  PIN Tile_X0Y0_FrameStrobe_O[14]
    DIRECTION OUTPUT ;
    USE SIGNAL ;
    ANTENNADIFFAREA 2.724000 ;
    PORT
      LAYER Metal2 ;
        RECT 168.280 78.980 168.680 79.380 ;
    END
  END Tile_X0Y0_FrameStrobe_O[14]
  PIN Tile_X0Y0_FrameStrobe_O[15]
    DIRECTION OUTPUT ;
    USE SIGNAL ;
    ANTENNADIFFAREA 2.724000 ;
    PORT
      LAYER Metal2 ;
        RECT 179.800 78.980 180.200 79.380 ;
    END
  END Tile_X0Y0_FrameStrobe_O[15]
  PIN Tile_X0Y0_FrameStrobe_O[16]
    DIRECTION OUTPUT ;
    USE SIGNAL ;
    ANTENNADIFFAREA 2.724000 ;
    PORT
      LAYER Metal2 ;
        RECT 191.320 78.980 191.720 79.380 ;
    END
  END Tile_X0Y0_FrameStrobe_O[16]
  PIN Tile_X0Y0_FrameStrobe_O[17]
    DIRECTION OUTPUT ;
    USE SIGNAL ;
    ANTENNADIFFAREA 2.724000 ;
    PORT
      LAYER Metal2 ;
        RECT 202.840 78.980 203.240 79.380 ;
    END
  END Tile_X0Y0_FrameStrobe_O[17]
  PIN Tile_X0Y0_FrameStrobe_O[18]
    DIRECTION OUTPUT ;
    USE SIGNAL ;
    ANTENNADIFFAREA 2.724000 ;
    PORT
      LAYER Metal2 ;
        RECT 214.360 78.980 214.760 79.380 ;
    END
  END Tile_X0Y0_FrameStrobe_O[18]
  PIN Tile_X0Y0_FrameStrobe_O[19]
    DIRECTION OUTPUT ;
    USE SIGNAL ;
    ANTENNADIFFAREA 2.724000 ;
    PORT
      LAYER Metal2 ;
        RECT 225.880 78.980 226.280 79.380 ;
    END
  END Tile_X0Y0_FrameStrobe_O[19]
  PIN Tile_X0Y0_FrameStrobe_O[1]
    DIRECTION OUTPUT ;
    USE SIGNAL ;
    ANTENNADIFFAREA 2.724000 ;
    PORT
      LAYER Metal2 ;
        RECT 18.520 78.980 18.920 79.380 ;
    END
  END Tile_X0Y0_FrameStrobe_O[1]
  PIN Tile_X0Y0_FrameStrobe_O[2]
    DIRECTION OUTPUT ;
    USE SIGNAL ;
    ANTENNADIFFAREA 2.724000 ;
    PORT
      LAYER Metal2 ;
        RECT 30.040 78.980 30.440 79.380 ;
    END
  END Tile_X0Y0_FrameStrobe_O[2]
  PIN Tile_X0Y0_FrameStrobe_O[3]
    DIRECTION OUTPUT ;
    USE SIGNAL ;
    ANTENNADIFFAREA 2.724000 ;
    PORT
      LAYER Metal2 ;
        RECT 41.560 78.980 41.960 79.380 ;
    END
  END Tile_X0Y0_FrameStrobe_O[3]
  PIN Tile_X0Y0_FrameStrobe_O[4]
    DIRECTION OUTPUT ;
    USE SIGNAL ;
    ANTENNADIFFAREA 2.724000 ;
    PORT
      LAYER Metal2 ;
        RECT 53.080 78.980 53.480 79.380 ;
    END
  END Tile_X0Y0_FrameStrobe_O[4]
  PIN Tile_X0Y0_FrameStrobe_O[5]
    DIRECTION OUTPUT ;
    USE SIGNAL ;
    ANTENNADIFFAREA 2.724000 ;
    PORT
      LAYER Metal2 ;
        RECT 64.600 78.980 65.000 79.380 ;
    END
  END Tile_X0Y0_FrameStrobe_O[5]
  PIN Tile_X0Y0_FrameStrobe_O[6]
    DIRECTION OUTPUT ;
    USE SIGNAL ;
    ANTENNADIFFAREA 2.724000 ;
    PORT
      LAYER Metal2 ;
        RECT 76.120 78.980 76.520 79.380 ;
    END
  END Tile_X0Y0_FrameStrobe_O[6]
  PIN Tile_X0Y0_FrameStrobe_O[7]
    DIRECTION OUTPUT ;
    USE SIGNAL ;
    ANTENNADIFFAREA 2.724000 ;
    PORT
      LAYER Metal2 ;
        RECT 87.640 78.980 88.040 79.380 ;
    END
  END Tile_X0Y0_FrameStrobe_O[7]
  PIN Tile_X0Y0_FrameStrobe_O[8]
    DIRECTION OUTPUT ;
    USE SIGNAL ;
    ANTENNADIFFAREA 2.724000 ;
    PORT
      LAYER Metal2 ;
        RECT 99.160 78.980 99.560 79.380 ;
    END
  END Tile_X0Y0_FrameStrobe_O[8]
  PIN Tile_X0Y0_FrameStrobe_O[9]
    DIRECTION OUTPUT ;
    USE SIGNAL ;
    ANTENNADIFFAREA 2.724000 ;
    PORT
      LAYER Metal2 ;
        RECT 110.680 78.980 111.080 79.380 ;
    END
  END Tile_X0Y0_FrameStrobe_O[9]
  PIN Tile_X0Y0_N1END[0]
    DIRECTION INPUT ;
    USE SIGNAL ;
    ANTENNAGATEAREA 0.607100 ;
    ANTENNADIFFAREA 18.138599 ;
    PORT
      LAYER Metal2 ;
        RECT 1.240 0.000 1.640 0.400 ;
    END
  END Tile_X0Y0_N1END[0]
  PIN Tile_X0Y0_N1END[1]
    DIRECTION INPUT ;
    USE SIGNAL ;
    ANTENNAGATEAREA 0.607100 ;
    PORT
      LAYER Metal2 ;
        RECT 3.160 0.000 3.560 0.400 ;
    END
  END Tile_X0Y0_N1END[1]
  PIN Tile_X0Y0_N1END[2]
    DIRECTION INPUT ;
    USE SIGNAL ;
    ANTENNAGATEAREA 0.607100 ;
    PORT
      LAYER Metal2 ;
        RECT 5.080 0.000 5.480 0.400 ;
    END
  END Tile_X0Y0_N1END[2]
  PIN Tile_X0Y0_N1END[3]
    DIRECTION INPUT ;
    USE SIGNAL ;
    ANTENNAGATEAREA 0.607100 ;
    PORT
      LAYER Metal2 ;
        RECT 7.000 0.000 7.400 0.400 ;
    END
  END Tile_X0Y0_N1END[3]
  PIN Tile_X0Y0_N2END[0]
    DIRECTION INPUT ;
    USE SIGNAL ;
    ANTENNAGATEAREA 0.639600 ;
    PORT
      LAYER Metal2 ;
        RECT 26.200 0.000 26.600 0.400 ;
    END
  END Tile_X0Y0_N2END[0]
  PIN Tile_X0Y0_N2END[1]
    DIRECTION INPUT ;
    USE SIGNAL ;
    ANTENNAGATEAREA 0.639600 ;
    PORT
      LAYER Metal2 ;
        RECT 27.160 0.000 27.560 0.400 ;
    END
  END Tile_X0Y0_N2END[1]
  PIN Tile_X0Y0_N2END[2]
    DIRECTION INPUT ;
    USE SIGNAL ;
    ANTENNAGATEAREA 0.639600 ;
    PORT
      LAYER Metal2 ;
        RECT 28.120 0.000 28.520 0.400 ;
    END
  END Tile_X0Y0_N2END[2]
  PIN Tile_X0Y0_N2END[3]
    DIRECTION INPUT ;
    USE SIGNAL ;
    ANTENNAGATEAREA 0.639600 ;
    PORT
      LAYER Metal2 ;
        RECT 29.080 0.000 29.480 0.400 ;
    END
  END Tile_X0Y0_N2END[3]
  PIN Tile_X0Y0_N2END[4]
    DIRECTION INPUT ;
    USE SIGNAL ;
    ANTENNAGATEAREA 0.639600 ;
    PORT
      LAYER Metal2 ;
        RECT 30.040 0.000 30.440 0.400 ;
    END
  END Tile_X0Y0_N2END[4]
  PIN Tile_X0Y0_N2END[5]
    DIRECTION INPUT ;
    USE SIGNAL ;
    ANTENNAGATEAREA 0.639600 ;
    ANTENNADIFFAREA 18.138599 ;
    PORT
      LAYER Metal2 ;
        RECT 31.000 0.000 31.400 0.400 ;
    END
  END Tile_X0Y0_N2END[5]
  PIN Tile_X0Y0_N2END[6]
    DIRECTION INPUT ;
    USE SIGNAL ;
    ANTENNAGATEAREA 0.639600 ;
    PORT
      LAYER Metal2 ;
        RECT 31.960 0.000 32.360 0.400 ;
    END
  END Tile_X0Y0_N2END[6]
  PIN Tile_X0Y0_N2END[7]
    DIRECTION INPUT ;
    USE SIGNAL ;
    ANTENNAGATEAREA 0.639600 ;
    PORT
      LAYER Metal2 ;
        RECT 32.920 0.000 33.320 0.400 ;
    END
  END Tile_X0Y0_N2END[7]
  PIN Tile_X0Y0_N2MID[0]
    DIRECTION INPUT ;
    USE SIGNAL ;
    ANTENNAGATEAREA 0.820300 ;
    PORT
      LAYER Metal2 ;
        RECT 11.800 0.000 12.200 0.400 ;
    END
  END Tile_X0Y0_N2MID[0]
  PIN Tile_X0Y0_N2MID[1]
    DIRECTION INPUT ;
    USE SIGNAL ;
    ANTENNAGATEAREA 0.820300 ;
    PORT
      LAYER Metal2 ;
        RECT 12.760 0.000 13.160 0.400 ;
    END
  END Tile_X0Y0_N2MID[1]
  PIN Tile_X0Y0_N2MID[2]
    DIRECTION INPUT ;
    USE SIGNAL ;
    ANTENNAGATEAREA 0.820300 ;
    PORT
      LAYER Metal2 ;
        RECT 13.720 0.000 14.120 0.400 ;
    END
  END Tile_X0Y0_N2MID[2]
  PIN Tile_X0Y0_N2MID[3]
    DIRECTION INPUT ;
    USE SIGNAL ;
    ANTENNAGATEAREA 0.820300 ;
    PORT
      LAYER Metal2 ;
        RECT 14.680 0.000 15.080 0.400 ;
    END
  END Tile_X0Y0_N2MID[3]
  PIN Tile_X0Y0_N2MID[4]
    DIRECTION INPUT ;
    USE SIGNAL ;
    ANTENNAGATEAREA 0.820300 ;
    PORT
      LAYER Metal2 ;
        RECT 15.640 0.000 16.040 0.400 ;
    END
  END Tile_X0Y0_N2MID[4]
  PIN Tile_X0Y0_N2MID[5]
    DIRECTION INPUT ;
    USE SIGNAL ;
    ANTENNAGATEAREA 0.820300 ;
    PORT
      LAYER Metal2 ;
        RECT 16.600 0.000 17.000 0.400 ;
    END
  END Tile_X0Y0_N2MID[5]
  PIN Tile_X0Y0_N2MID[6]
    DIRECTION INPUT ;
    USE SIGNAL ;
    ANTENNAGATEAREA 0.820300 ;
    PORT
      LAYER Metal2 ;
        RECT 17.560 0.000 17.960 0.400 ;
    END
  END Tile_X0Y0_N2MID[6]
  PIN Tile_X0Y0_N2MID[7]
    DIRECTION INPUT ;
    USE SIGNAL ;
    ANTENNAGATEAREA 0.820300 ;
    PORT
      LAYER Metal2 ;
        RECT 18.520 0.000 18.920 0.400 ;
    END
  END Tile_X0Y0_N2MID[7]
  PIN Tile_X0Y0_N4END[0]
    DIRECTION INPUT ;
    USE SIGNAL ;
    ANTENNAGATEAREA 0.852800 ;
    PORT
      LAYER Metal2 ;
        RECT 44.440 0.000 44.840 0.400 ;
    END
  END Tile_X0Y0_N4END[0]
  PIN Tile_X0Y0_N4END[10]
    DIRECTION INPUT ;
    USE SIGNAL ;
    ANTENNAGATEAREA 0.852800 ;
    PORT
      LAYER Metal2 ;
        RECT 54.040 0.000 54.440 0.400 ;
    END
  END Tile_X0Y0_N4END[10]
  PIN Tile_X0Y0_N4END[11]
    DIRECTION INPUT ;
    USE SIGNAL ;
    ANTENNAGATEAREA 0.852800 ;
    PORT
      LAYER Metal2 ;
        RECT 55.000 0.000 55.400 0.400 ;
    END
  END Tile_X0Y0_N4END[11]
  PIN Tile_X0Y0_N4END[12]
    DIRECTION INPUT ;
    USE SIGNAL ;
    ANTENNAGATEAREA 0.852800 ;
    PORT
      LAYER Metal2 ;
        RECT 55.960 0.000 56.360 0.400 ;
    END
  END Tile_X0Y0_N4END[12]
  PIN Tile_X0Y0_N4END[13]
    DIRECTION INPUT ;
    USE SIGNAL ;
    ANTENNAGATEAREA 0.852800 ;
    PORT
      LAYER Metal2 ;
        RECT 56.920 0.000 57.320 0.400 ;
    END
  END Tile_X0Y0_N4END[13]
  PIN Tile_X0Y0_N4END[14]
    DIRECTION INPUT ;
    USE SIGNAL ;
    ANTENNAGATEAREA 0.852800 ;
    PORT
      LAYER Metal2 ;
        RECT 57.880 0.000 58.280 0.400 ;
    END
  END Tile_X0Y0_N4END[14]
  PIN Tile_X0Y0_N4END[15]
    DIRECTION INPUT ;
    USE SIGNAL ;
    ANTENNAGATEAREA 0.852800 ;
    PORT
      LAYER Metal2 ;
        RECT 58.840 0.000 59.240 0.400 ;
    END
  END Tile_X0Y0_N4END[15]
  PIN Tile_X0Y0_N4END[1]
    DIRECTION INPUT ;
    USE SIGNAL ;
    ANTENNAGATEAREA 0.852800 ;
    PORT
      LAYER Metal2 ;
        RECT 45.400 0.000 45.800 0.400 ;
    END
  END Tile_X0Y0_N4END[1]
  PIN Tile_X0Y0_N4END[2]
    DIRECTION INPUT ;
    USE SIGNAL ;
    ANTENNAGATEAREA 0.852800 ;
    PORT
      LAYER Metal2 ;
        RECT 46.360 0.000 46.760 0.400 ;
    END
  END Tile_X0Y0_N4END[2]
  PIN Tile_X0Y0_N4END[3]
    DIRECTION INPUT ;
    USE SIGNAL ;
    ANTENNAGATEAREA 0.852800 ;
    PORT
      LAYER Metal2 ;
        RECT 47.320 0.000 47.720 0.400 ;
    END
  END Tile_X0Y0_N4END[3]
  PIN Tile_X0Y0_N4END[4]
    DIRECTION INPUT ;
    USE SIGNAL ;
    ANTENNAGATEAREA 0.852800 ;
    PORT
      LAYER Metal2 ;
        RECT 48.280 0.000 48.680 0.400 ;
    END
  END Tile_X0Y0_N4END[4]
  PIN Tile_X0Y0_N4END[5]
    DIRECTION INPUT ;
    USE SIGNAL ;
    ANTENNAGATEAREA 0.852800 ;
    PORT
      LAYER Metal2 ;
        RECT 49.240 0.000 49.640 0.400 ;
    END
  END Tile_X0Y0_N4END[5]
  PIN Tile_X0Y0_N4END[6]
    DIRECTION INPUT ;
    USE SIGNAL ;
    ANTENNAGATEAREA 0.852800 ;
    PORT
      LAYER Metal2 ;
        RECT 50.200 0.000 50.600 0.400 ;
    END
  END Tile_X0Y0_N4END[6]
  PIN Tile_X0Y0_N4END[7]
    DIRECTION INPUT ;
    USE SIGNAL ;
    ANTENNAGATEAREA 0.852800 ;
    PORT
      LAYER Metal2 ;
        RECT 51.160 0.000 51.560 0.400 ;
    END
  END Tile_X0Y0_N4END[7]
  PIN Tile_X0Y0_N4END[8]
    DIRECTION INPUT ;
    USE SIGNAL ;
    ANTENNAGATEAREA 0.852800 ;
    PORT
      LAYER Metal2 ;
        RECT 52.120 0.000 52.520 0.400 ;
    END
  END Tile_X0Y0_N4END[8]
  PIN Tile_X0Y0_N4END[9]
    DIRECTION INPUT ;
    USE SIGNAL ;
    ANTENNAGATEAREA 0.852800 ;
    ANTENNADIFFAREA 16.123199 ;
    PORT
      LAYER Metal2 ;
        RECT 53.080 0.000 53.480 0.400 ;
    END
  END Tile_X0Y0_N4END[9]
  PIN Tile_X0Y0_NN4END[0]
    DIRECTION INPUT ;
    USE SIGNAL ;
    ANTENNAGATEAREA 0.852800 ;
    PORT
      LAYER Metal2 ;
        RECT 74.200 0.000 74.600 0.400 ;
    END
  END Tile_X0Y0_NN4END[0]
  PIN Tile_X0Y0_NN4END[10]
    DIRECTION INPUT ;
    USE SIGNAL ;
    ANTENNAGATEAREA 0.852800 ;
    PORT
      LAYER Metal2 ;
        RECT 83.800 0.000 84.200 0.400 ;
    END
  END Tile_X0Y0_NN4END[10]
  PIN Tile_X0Y0_NN4END[11]
    DIRECTION INPUT ;
    USE SIGNAL ;
    ANTENNAGATEAREA 0.852800 ;
    PORT
      LAYER Metal2 ;
        RECT 84.760 0.000 85.160 0.400 ;
    END
  END Tile_X0Y0_NN4END[11]
  PIN Tile_X0Y0_NN4END[12]
    DIRECTION INPUT ;
    USE SIGNAL ;
    ANTENNAGATEAREA 0.852800 ;
    PORT
      LAYER Metal2 ;
        RECT 85.720 0.000 86.120 0.400 ;
    END
  END Tile_X0Y0_NN4END[12]
  PIN Tile_X0Y0_NN4END[13]
    DIRECTION INPUT ;
    USE SIGNAL ;
    ANTENNAGATEAREA 0.852800 ;
    PORT
      LAYER Metal2 ;
        RECT 86.680 0.000 87.080 0.400 ;
    END
  END Tile_X0Y0_NN4END[13]
  PIN Tile_X0Y0_NN4END[14]
    DIRECTION INPUT ;
    USE SIGNAL ;
    ANTENNAGATEAREA 0.852800 ;
    PORT
      LAYER Metal2 ;
        RECT 87.640 0.000 88.040 0.400 ;
    END
  END Tile_X0Y0_NN4END[14]
  PIN Tile_X0Y0_NN4END[15]
    DIRECTION INPUT ;
    USE SIGNAL ;
    ANTENNAGATEAREA 0.852800 ;
    PORT
      LAYER Metal2 ;
        RECT 88.600 0.000 89.000 0.400 ;
    END
  END Tile_X0Y0_NN4END[15]
  PIN Tile_X0Y0_NN4END[1]
    DIRECTION INPUT ;
    USE SIGNAL ;
    ANTENNAGATEAREA 0.852800 ;
    PORT
      LAYER Metal2 ;
        RECT 75.160 0.000 75.560 0.400 ;
    END
  END Tile_X0Y0_NN4END[1]
  PIN Tile_X0Y0_NN4END[2]
    DIRECTION INPUT ;
    USE SIGNAL ;
    ANTENNAGATEAREA 0.852800 ;
    PORT
      LAYER Metal2 ;
        RECT 76.120 0.000 76.520 0.400 ;
    END
  END Tile_X0Y0_NN4END[2]
  PIN Tile_X0Y0_NN4END[3]
    DIRECTION INPUT ;
    USE SIGNAL ;
    ANTENNAGATEAREA 0.852800 ;
    PORT
      LAYER Metal2 ;
        RECT 77.080 0.000 77.480 0.400 ;
    END
  END Tile_X0Y0_NN4END[3]
  PIN Tile_X0Y0_NN4END[4]
    DIRECTION INPUT ;
    USE SIGNAL ;
    ANTENNAGATEAREA 0.852800 ;
    PORT
      LAYER Metal2 ;
        RECT 78.040 0.000 78.440 0.400 ;
    END
  END Tile_X0Y0_NN4END[4]
  PIN Tile_X0Y0_NN4END[5]
    DIRECTION INPUT ;
    USE SIGNAL ;
    ANTENNAGATEAREA 0.852800 ;
    PORT
      LAYER Metal2 ;
        RECT 79.000 0.000 79.400 0.400 ;
    END
  END Tile_X0Y0_NN4END[5]
  PIN Tile_X0Y0_NN4END[6]
    DIRECTION INPUT ;
    USE SIGNAL ;
    ANTENNAGATEAREA 0.852800 ;
    PORT
      LAYER Metal2 ;
        RECT 79.960 0.000 80.360 0.400 ;
    END
  END Tile_X0Y0_NN4END[6]
  PIN Tile_X0Y0_NN4END[7]
    DIRECTION INPUT ;
    USE SIGNAL ;
    ANTENNAGATEAREA 0.852800 ;
    PORT
      LAYER Metal2 ;
        RECT 80.920 0.000 81.320 0.400 ;
    END
  END Tile_X0Y0_NN4END[7]
  PIN Tile_X0Y0_NN4END[8]
    DIRECTION INPUT ;
    USE SIGNAL ;
    ANTENNAGATEAREA 0.852800 ;
    PORT
      LAYER Metal2 ;
        RECT 81.880 0.000 82.280 0.400 ;
    END
  END Tile_X0Y0_NN4END[8]
  PIN Tile_X0Y0_NN4END[9]
    DIRECTION INPUT ;
    USE SIGNAL ;
    ANTENNAGATEAREA 0.852800 ;
    PORT
      LAYER Metal2 ;
        RECT 82.840 0.000 83.240 0.400 ;
    END
  END Tile_X0Y0_NN4END[9]
  PIN Tile_X0Y0_S1BEG[0]
    DIRECTION OUTPUT ;
    USE SIGNAL ;
    ANTENNADIFFAREA 2.724000 ;
    PORT
      LAYER Metal2 ;
        RECT 99.160 0.000 99.560 0.400 ;
    END
  END Tile_X0Y0_S1BEG[0]
  PIN Tile_X0Y0_S1BEG[1]
    DIRECTION OUTPUT ;
    USE SIGNAL ;
    ANTENNADIFFAREA 2.724000 ;
    PORT
      LAYER Metal2 ;
        RECT 101.080 0.000 101.480 0.400 ;
    END
  END Tile_X0Y0_S1BEG[1]
  PIN Tile_X0Y0_S1BEG[2]
    DIRECTION OUTPUT ;
    USE SIGNAL ;
    ANTENNADIFFAREA 2.724000 ;
    PORT
      LAYER Metal2 ;
        RECT 103.000 0.000 103.400 0.400 ;
    END
  END Tile_X0Y0_S1BEG[2]
  PIN Tile_X0Y0_S1BEG[3]
    DIRECTION OUTPUT ;
    USE SIGNAL ;
    ANTENNADIFFAREA 2.724000 ;
    PORT
      LAYER Metal2 ;
        RECT 104.920 0.000 105.320 0.400 ;
    END
  END Tile_X0Y0_S1BEG[3]
  PIN Tile_X0Y0_S2BEG[0]
    DIRECTION OUTPUT ;
    USE SIGNAL ;
    ANTENNADIFFAREA 2.724000 ;
    PORT
      LAYER Metal2 ;
        RECT 106.840 0.000 107.240 0.400 ;
    END
  END Tile_X0Y0_S2BEG[0]
  PIN Tile_X0Y0_S2BEG[1]
    DIRECTION OUTPUT ;
    USE SIGNAL ;
    ANTENNADIFFAREA 2.724000 ;
    PORT
      LAYER Metal2 ;
        RECT 108.760 0.000 109.160 0.400 ;
    END
  END Tile_X0Y0_S2BEG[1]
  PIN Tile_X0Y0_S2BEG[2]
    DIRECTION OUTPUT ;
    USE SIGNAL ;
    ANTENNADIFFAREA 2.724000 ;
    PORT
      LAYER Metal2 ;
        RECT 110.680 0.000 111.080 0.400 ;
    END
  END Tile_X0Y0_S2BEG[2]
  PIN Tile_X0Y0_S2BEG[3]
    DIRECTION OUTPUT ;
    USE SIGNAL ;
    ANTENNADIFFAREA 2.724000 ;
    PORT
      LAYER Metal2 ;
        RECT 112.600 0.000 113.000 0.400 ;
    END
  END Tile_X0Y0_S2BEG[3]
  PIN Tile_X0Y0_S2BEG[4]
    DIRECTION OUTPUT ;
    USE SIGNAL ;
    ANTENNADIFFAREA 2.724000 ;
    PORT
      LAYER Metal2 ;
        RECT 114.520 0.000 114.920 0.400 ;
    END
  END Tile_X0Y0_S2BEG[4]
  PIN Tile_X0Y0_S2BEG[5]
    DIRECTION OUTPUT ;
    USE SIGNAL ;
    ANTENNADIFFAREA 2.724000 ;
    PORT
      LAYER Metal2 ;
        RECT 116.440 0.000 116.840 0.400 ;
    END
  END Tile_X0Y0_S2BEG[5]
  PIN Tile_X0Y0_S2BEG[6]
    DIRECTION OUTPUT ;
    USE SIGNAL ;
    ANTENNADIFFAREA 2.724000 ;
    PORT
      LAYER Metal2 ;
        RECT 118.360 0.000 118.760 0.400 ;
    END
  END Tile_X0Y0_S2BEG[6]
  PIN Tile_X0Y0_S2BEG[7]
    DIRECTION OUTPUT ;
    USE SIGNAL ;
    ANTENNADIFFAREA 2.724000 ;
    PORT
      LAYER Metal2 ;
        RECT 120.280 0.000 120.680 0.400 ;
    END
  END Tile_X0Y0_S2BEG[7]
  PIN Tile_X0Y0_S2BEGb[0]
    DIRECTION OUTPUT ;
    USE SIGNAL ;
    ANTENNADIFFAREA 2.724000 ;
    PORT
      LAYER Metal2 ;
        RECT 125.080 0.000 125.480 0.400 ;
    END
  END Tile_X0Y0_S2BEGb[0]
  PIN Tile_X0Y0_S2BEGb[1]
    DIRECTION OUTPUT ;
    USE SIGNAL ;
    ANTENNADIFFAREA 2.724000 ;
    PORT
      LAYER Metal2 ;
        RECT 126.040 0.000 126.440 0.400 ;
    END
  END Tile_X0Y0_S2BEGb[1]
  PIN Tile_X0Y0_S2BEGb[2]
    DIRECTION OUTPUT ;
    USE SIGNAL ;
    ANTENNADIFFAREA 2.724000 ;
    PORT
      LAYER Metal2 ;
        RECT 127.000 0.000 127.400 0.400 ;
    END
  END Tile_X0Y0_S2BEGb[2]
  PIN Tile_X0Y0_S2BEGb[3]
    DIRECTION OUTPUT ;
    USE SIGNAL ;
    ANTENNADIFFAREA 2.724000 ;
    PORT
      LAYER Metal2 ;
        RECT 127.960 0.000 128.360 0.400 ;
    END
  END Tile_X0Y0_S2BEGb[3]
  PIN Tile_X0Y0_S2BEGb[4]
    DIRECTION OUTPUT ;
    USE SIGNAL ;
    ANTENNADIFFAREA 2.724000 ;
    PORT
      LAYER Metal2 ;
        RECT 128.920 0.000 129.320 0.400 ;
    END
  END Tile_X0Y0_S2BEGb[4]
  PIN Tile_X0Y0_S2BEGb[5]
    DIRECTION OUTPUT ;
    USE SIGNAL ;
    ANTENNADIFFAREA 2.724000 ;
    PORT
      LAYER Metal2 ;
        RECT 129.880 0.000 130.280 0.400 ;
    END
  END Tile_X0Y0_S2BEGb[5]
  PIN Tile_X0Y0_S2BEGb[6]
    DIRECTION OUTPUT ;
    USE SIGNAL ;
    ANTENNADIFFAREA 2.724000 ;
    PORT
      LAYER Metal2 ;
        RECT 130.840 0.000 131.240 0.400 ;
    END
  END Tile_X0Y0_S2BEGb[6]
  PIN Tile_X0Y0_S2BEGb[7]
    DIRECTION OUTPUT ;
    USE SIGNAL ;
    ANTENNADIFFAREA 2.724000 ;
    PORT
      LAYER Metal2 ;
        RECT 131.800 0.000 132.200 0.400 ;
    END
  END Tile_X0Y0_S2BEGb[7]
  PIN Tile_X0Y0_S4BEG[0]
    DIRECTION OUTPUT ;
    USE SIGNAL ;
    ANTENNADIFFAREA 2.724000 ;
    PORT
      LAYER Metal2 ;
        RECT 143.320 0.000 143.720 0.400 ;
    END
  END Tile_X0Y0_S4BEG[0]
  PIN Tile_X0Y0_S4BEG[10]
    DIRECTION OUTPUT ;
    USE SIGNAL ;
    ANTENNADIFFAREA 2.724000 ;
    PORT
      LAYER Metal2 ;
        RECT 152.920 0.000 153.320 0.400 ;
    END
  END Tile_X0Y0_S4BEG[10]
  PIN Tile_X0Y0_S4BEG[11]
    DIRECTION OUTPUT ;
    USE SIGNAL ;
    ANTENNADIFFAREA 2.724000 ;
    PORT
      LAYER Metal2 ;
        RECT 153.880 0.000 154.280 0.400 ;
    END
  END Tile_X0Y0_S4BEG[11]
  PIN Tile_X0Y0_S4BEG[12]
    DIRECTION OUTPUT ;
    USE SIGNAL ;
    ANTENNADIFFAREA 2.724000 ;
    PORT
      LAYER Metal2 ;
        RECT 154.840 0.000 155.240 0.400 ;
    END
  END Tile_X0Y0_S4BEG[12]
  PIN Tile_X0Y0_S4BEG[13]
    DIRECTION OUTPUT ;
    USE SIGNAL ;
    ANTENNADIFFAREA 2.724000 ;
    PORT
      LAYER Metal2 ;
        RECT 155.800 0.000 156.200 0.400 ;
    END
  END Tile_X0Y0_S4BEG[13]
  PIN Tile_X0Y0_S4BEG[14]
    DIRECTION OUTPUT ;
    USE SIGNAL ;
    ANTENNADIFFAREA 2.724000 ;
    PORT
      LAYER Metal2 ;
        RECT 156.760 0.000 157.160 0.400 ;
    END
  END Tile_X0Y0_S4BEG[14]
  PIN Tile_X0Y0_S4BEG[15]
    DIRECTION OUTPUT ;
    USE SIGNAL ;
    ANTENNADIFFAREA 2.724000 ;
    PORT
      LAYER Metal2 ;
        RECT 157.720 0.000 158.120 0.400 ;
    END
  END Tile_X0Y0_S4BEG[15]
  PIN Tile_X0Y0_S4BEG[1]
    DIRECTION OUTPUT ;
    USE SIGNAL ;
    ANTENNADIFFAREA 2.724000 ;
    PORT
      LAYER Metal2 ;
        RECT 144.280 0.000 144.680 0.400 ;
    END
  END Tile_X0Y0_S4BEG[1]
  PIN Tile_X0Y0_S4BEG[2]
    DIRECTION OUTPUT ;
    USE SIGNAL ;
    ANTENNADIFFAREA 2.724000 ;
    PORT
      LAYER Metal2 ;
        RECT 145.240 0.000 145.640 0.400 ;
    END
  END Tile_X0Y0_S4BEG[2]
  PIN Tile_X0Y0_S4BEG[3]
    DIRECTION OUTPUT ;
    USE SIGNAL ;
    ANTENNADIFFAREA 2.724000 ;
    PORT
      LAYER Metal2 ;
        RECT 146.200 0.000 146.600 0.400 ;
    END
  END Tile_X0Y0_S4BEG[3]
  PIN Tile_X0Y0_S4BEG[4]
    DIRECTION OUTPUT ;
    USE SIGNAL ;
    ANTENNADIFFAREA 2.724000 ;
    PORT
      LAYER Metal2 ;
        RECT 147.160 0.000 147.560 0.400 ;
    END
  END Tile_X0Y0_S4BEG[4]
  PIN Tile_X0Y0_S4BEG[5]
    DIRECTION OUTPUT ;
    USE SIGNAL ;
    ANTENNADIFFAREA 2.724000 ;
    PORT
      LAYER Metal2 ;
        RECT 148.120 0.000 148.520 0.400 ;
    END
  END Tile_X0Y0_S4BEG[5]
  PIN Tile_X0Y0_S4BEG[6]
    DIRECTION OUTPUT ;
    USE SIGNAL ;
    ANTENNADIFFAREA 2.724000 ;
    PORT
      LAYER Metal2 ;
        RECT 149.080 0.000 149.480 0.400 ;
    END
  END Tile_X0Y0_S4BEG[6]
  PIN Tile_X0Y0_S4BEG[7]
    DIRECTION OUTPUT ;
    USE SIGNAL ;
    ANTENNADIFFAREA 2.724000 ;
    PORT
      LAYER Metal2 ;
        RECT 150.040 0.000 150.440 0.400 ;
    END
  END Tile_X0Y0_S4BEG[7]
  PIN Tile_X0Y0_S4BEG[8]
    DIRECTION OUTPUT ;
    USE SIGNAL ;
    ANTENNADIFFAREA 2.724000 ;
    PORT
      LAYER Metal2 ;
        RECT 151.000 0.000 151.400 0.400 ;
    END
  END Tile_X0Y0_S4BEG[8]
  PIN Tile_X0Y0_S4BEG[9]
    DIRECTION OUTPUT ;
    USE SIGNAL ;
    ANTENNADIFFAREA 2.724000 ;
    PORT
      LAYER Metal2 ;
        RECT 151.960 0.000 152.360 0.400 ;
    END
  END Tile_X0Y0_S4BEG[9]
  PIN Tile_X0Y0_SS4BEG[0]
    DIRECTION OUTPUT ;
    USE SIGNAL ;
    ANTENNADIFFAREA 2.724000 ;
    PORT
      LAYER Metal2 ;
        RECT 173.080 0.000 173.480 0.400 ;
    END
  END Tile_X0Y0_SS4BEG[0]
  PIN Tile_X0Y0_SS4BEG[10]
    DIRECTION OUTPUT ;
    USE SIGNAL ;
    ANTENNADIFFAREA 2.724000 ;
    PORT
      LAYER Metal2 ;
        RECT 182.680 0.000 183.080 0.400 ;
    END
  END Tile_X0Y0_SS4BEG[10]
  PIN Tile_X0Y0_SS4BEG[11]
    DIRECTION OUTPUT ;
    USE SIGNAL ;
    ANTENNADIFFAREA 2.724000 ;
    PORT
      LAYER Metal2 ;
        RECT 183.640 0.000 184.040 0.400 ;
    END
  END Tile_X0Y0_SS4BEG[11]
  PIN Tile_X0Y0_SS4BEG[12]
    DIRECTION OUTPUT ;
    USE SIGNAL ;
    ANTENNADIFFAREA 2.724000 ;
    PORT
      LAYER Metal2 ;
        RECT 184.600 0.000 185.000 0.400 ;
    END
  END Tile_X0Y0_SS4BEG[12]
  PIN Tile_X0Y0_SS4BEG[13]
    DIRECTION OUTPUT ;
    USE SIGNAL ;
    ANTENNADIFFAREA 2.724000 ;
    PORT
      LAYER Metal2 ;
        RECT 185.560 0.000 185.960 0.400 ;
    END
  END Tile_X0Y0_SS4BEG[13]
  PIN Tile_X0Y0_SS4BEG[14]
    DIRECTION OUTPUT ;
    USE SIGNAL ;
    ANTENNADIFFAREA 2.724000 ;
    PORT
      LAYER Metal2 ;
        RECT 186.520 0.000 186.920 0.400 ;
    END
  END Tile_X0Y0_SS4BEG[14]
  PIN Tile_X0Y0_SS4BEG[15]
    DIRECTION OUTPUT ;
    USE SIGNAL ;
    ANTENNADIFFAREA 2.724000 ;
    PORT
      LAYER Metal2 ;
        RECT 187.480 0.000 187.880 0.400 ;
    END
  END Tile_X0Y0_SS4BEG[15]
  PIN Tile_X0Y0_SS4BEG[1]
    DIRECTION OUTPUT ;
    USE SIGNAL ;
    ANTENNADIFFAREA 2.724000 ;
    PORT
      LAYER Metal2 ;
        RECT 174.040 0.000 174.440 0.400 ;
    END
  END Tile_X0Y0_SS4BEG[1]
  PIN Tile_X0Y0_SS4BEG[2]
    DIRECTION OUTPUT ;
    USE SIGNAL ;
    ANTENNADIFFAREA 2.724000 ;
    PORT
      LAYER Metal2 ;
        RECT 175.000 0.000 175.400 0.400 ;
    END
  END Tile_X0Y0_SS4BEG[2]
  PIN Tile_X0Y0_SS4BEG[3]
    DIRECTION OUTPUT ;
    USE SIGNAL ;
    ANTENNADIFFAREA 2.724000 ;
    PORT
      LAYER Metal2 ;
        RECT 175.960 0.000 176.360 0.400 ;
    END
  END Tile_X0Y0_SS4BEG[3]
  PIN Tile_X0Y0_SS4BEG[4]
    DIRECTION OUTPUT ;
    USE SIGNAL ;
    ANTENNADIFFAREA 2.724000 ;
    PORT
      LAYER Metal2 ;
        RECT 176.920 0.000 177.320 0.400 ;
    END
  END Tile_X0Y0_SS4BEG[4]
  PIN Tile_X0Y0_SS4BEG[5]
    DIRECTION OUTPUT ;
    USE SIGNAL ;
    ANTENNADIFFAREA 2.724000 ;
    PORT
      LAYER Metal2 ;
        RECT 177.880 0.000 178.280 0.400 ;
    END
  END Tile_X0Y0_SS4BEG[5]
  PIN Tile_X0Y0_SS4BEG[6]
    DIRECTION OUTPUT ;
    USE SIGNAL ;
    ANTENNADIFFAREA 2.724000 ;
    PORT
      LAYER Metal2 ;
        RECT 178.840 0.000 179.240 0.400 ;
    END
  END Tile_X0Y0_SS4BEG[6]
  PIN Tile_X0Y0_SS4BEG[7]
    DIRECTION OUTPUT ;
    USE SIGNAL ;
    ANTENNADIFFAREA 2.724000 ;
    PORT
      LAYER Metal2 ;
        RECT 179.800 0.000 180.200 0.400 ;
    END
  END Tile_X0Y0_SS4BEG[7]
  PIN Tile_X0Y0_SS4BEG[8]
    DIRECTION OUTPUT ;
    USE SIGNAL ;
    ANTENNADIFFAREA 2.724000 ;
    PORT
      LAYER Metal2 ;
        RECT 180.760 0.000 181.160 0.400 ;
    END
  END Tile_X0Y0_SS4BEG[8]
  PIN Tile_X0Y0_SS4BEG[9]
    DIRECTION OUTPUT ;
    USE SIGNAL ;
    ANTENNADIFFAREA 2.724000 ;
    PORT
      LAYER Metal2 ;
        RECT 181.720 0.000 182.120 0.400 ;
    END
  END Tile_X0Y0_SS4BEG[9]
  PIN Tile_X0Y0_UserCLK
    DIRECTION INPUT ;
    USE SIGNAL ;
    ANTENNAGATEAREA 20.250099 ;
    PORT
      LAYER Metal3 ;
        RECT 0.000 1.900 0.400 2.300 ;
    END
  END Tile_X0Y0_UserCLK
  PIN Tile_X1Y0_Ci
    DIRECTION INPUT ;
    USE SIGNAL ;
    PORT
      LAYER Metal2 ;
        RECT 330.520 0.000 330.920 0.400 ;
    END
  END Tile_X1Y0_Ci
  PIN Tile_X1Y0_FrameStrobe[0]
    DIRECTION INPUT ;
    USE SIGNAL ;
    ANTENNAGATEAREA 11.745500 ;
    PORT
      LAYER Metal2 ;
        RECT 438.040 0.000 438.440 0.400 ;
    END
  END Tile_X1Y0_FrameStrobe[0]
  PIN Tile_X1Y0_FrameStrobe[10]
    DIRECTION INPUT ;
    USE SIGNAL ;
    ANTENNAGATEAREA 0.180700 ;
    PORT
      LAYER Metal2 ;
        RECT 447.640 0.000 448.040 0.400 ;
    END
  END Tile_X1Y0_FrameStrobe[10]
  PIN Tile_X1Y0_FrameStrobe[11]
    DIRECTION INPUT ;
    USE SIGNAL ;
    ANTENNAGATEAREA 0.180700 ;
    PORT
      LAYER Metal2 ;
        RECT 448.600 0.000 449.000 0.400 ;
    END
  END Tile_X1Y0_FrameStrobe[11]
  PIN Tile_X1Y0_FrameStrobe[12]
    DIRECTION INPUT ;
    USE SIGNAL ;
    ANTENNAGATEAREA 0.180700 ;
    PORT
      LAYER Metal2 ;
        RECT 449.560 0.000 449.960 0.400 ;
    END
  END Tile_X1Y0_FrameStrobe[12]
  PIN Tile_X1Y0_FrameStrobe[13]
    DIRECTION INPUT ;
    USE SIGNAL ;
    ANTENNAGATEAREA 0.180700 ;
    PORT
      LAYER Metal2 ;
        RECT 450.520 0.000 450.920 0.400 ;
    END
  END Tile_X1Y0_FrameStrobe[13]
  PIN Tile_X1Y0_FrameStrobe[14]
    DIRECTION INPUT ;
    USE SIGNAL ;
    ANTENNAGATEAREA 0.180700 ;
    PORT
      LAYER Metal2 ;
        RECT 451.480 0.000 451.880 0.400 ;
    END
  END Tile_X1Y0_FrameStrobe[14]
  PIN Tile_X1Y0_FrameStrobe[15]
    DIRECTION INPUT ;
    USE SIGNAL ;
    ANTENNAGATEAREA 0.180700 ;
    PORT
      LAYER Metal2 ;
        RECT 452.440 0.000 452.840 0.400 ;
    END
  END Tile_X1Y0_FrameStrobe[15]
  PIN Tile_X1Y0_FrameStrobe[16]
    DIRECTION INPUT ;
    USE SIGNAL ;
    ANTENNAGATEAREA 0.180700 ;
    PORT
      LAYER Metal2 ;
        RECT 453.400 0.000 453.800 0.400 ;
    END
  END Tile_X1Y0_FrameStrobe[16]
  PIN Tile_X1Y0_FrameStrobe[17]
    DIRECTION INPUT ;
    USE SIGNAL ;
    ANTENNAGATEAREA 0.180700 ;
    PORT
      LAYER Metal2 ;
        RECT 454.360 0.000 454.760 0.400 ;
    END
  END Tile_X1Y0_FrameStrobe[17]
  PIN Tile_X1Y0_FrameStrobe[18]
    DIRECTION INPUT ;
    USE SIGNAL ;
    ANTENNAGATEAREA 0.180700 ;
    PORT
      LAYER Metal2 ;
        RECT 455.320 0.000 455.720 0.400 ;
    END
  END Tile_X1Y0_FrameStrobe[18]
  PIN Tile_X1Y0_FrameStrobe[19]
    DIRECTION INPUT ;
    USE SIGNAL ;
    ANTENNAGATEAREA 0.180700 ;
    PORT
      LAYER Metal2 ;
        RECT 456.280 0.000 456.680 0.400 ;
    END
  END Tile_X1Y0_FrameStrobe[19]
  PIN Tile_X1Y0_FrameStrobe[1]
    DIRECTION INPUT ;
    USE SIGNAL ;
    ANTENNAGATEAREA 11.745500 ;
    PORT
      LAYER Metal2 ;
        RECT 439.000 0.000 439.400 0.400 ;
    END
  END Tile_X1Y0_FrameStrobe[1]
  PIN Tile_X1Y0_FrameStrobe[2]
    DIRECTION INPUT ;
    USE SIGNAL ;
    ANTENNAGATEAREA 11.745500 ;
    PORT
      LAYER Metal2 ;
        RECT 439.960 0.000 440.360 0.400 ;
    END
  END Tile_X1Y0_FrameStrobe[2]
  PIN Tile_X1Y0_FrameStrobe[3]
    DIRECTION INPUT ;
    USE SIGNAL ;
    ANTENNAGATEAREA 5.963100 ;
    PORT
      LAYER Metal2 ;
        RECT 440.920 0.000 441.320 0.400 ;
    END
  END Tile_X1Y0_FrameStrobe[3]
  PIN Tile_X1Y0_FrameStrobe[4]
    DIRECTION INPUT ;
    USE SIGNAL ;
    ANTENNAGATEAREA 0.180700 ;
    PORT
      LAYER Metal2 ;
        RECT 441.880 0.000 442.280 0.400 ;
    END
  END Tile_X1Y0_FrameStrobe[4]
  PIN Tile_X1Y0_FrameStrobe[5]
    DIRECTION INPUT ;
    USE SIGNAL ;
    ANTENNAGATEAREA 0.180700 ;
    PORT
      LAYER Metal2 ;
        RECT 442.840 0.000 443.240 0.400 ;
    END
  END Tile_X1Y0_FrameStrobe[5]
  PIN Tile_X1Y0_FrameStrobe[6]
    DIRECTION INPUT ;
    USE SIGNAL ;
    ANTENNAGATEAREA 0.180700 ;
    PORT
      LAYER Metal2 ;
        RECT 443.800 0.000 444.200 0.400 ;
    END
  END Tile_X1Y0_FrameStrobe[6]
  PIN Tile_X1Y0_FrameStrobe[7]
    DIRECTION INPUT ;
    USE SIGNAL ;
    ANTENNAGATEAREA 0.180700 ;
    PORT
      LAYER Metal2 ;
        RECT 444.760 0.000 445.160 0.400 ;
    END
  END Tile_X1Y0_FrameStrobe[7]
  PIN Tile_X1Y0_FrameStrobe[8]
    DIRECTION INPUT ;
    USE SIGNAL ;
    ANTENNAGATEAREA 0.180700 ;
    PORT
      LAYER Metal2 ;
        RECT 445.720 0.000 446.120 0.400 ;
    END
  END Tile_X1Y0_FrameStrobe[8]
  PIN Tile_X1Y0_FrameStrobe[9]
    DIRECTION INPUT ;
    USE SIGNAL ;
    ANTENNAGATEAREA 0.180700 ;
    PORT
      LAYER Metal2 ;
        RECT 446.680 0.000 447.080 0.400 ;
    END
  END Tile_X1Y0_FrameStrobe[9]
  PIN Tile_X1Y0_FrameStrobe_O[0]
    DIRECTION OUTPUT ;
    USE SIGNAL ;
    ANTENNADIFFAREA 2.724000 ;
    PORT
      LAYER Metal2 ;
        RECT 240.280 78.980 240.680 79.380 ;
    END
  END Tile_X1Y0_FrameStrobe_O[0]
  PIN Tile_X1Y0_FrameStrobe_O[10]
    DIRECTION OUTPUT ;
    USE SIGNAL ;
    ANTENNADIFFAREA 2.724000 ;
    PORT
      LAYER Metal2 ;
        RECT 355.480 78.980 355.880 79.380 ;
    END
  END Tile_X1Y0_FrameStrobe_O[10]
  PIN Tile_X1Y0_FrameStrobe_O[11]
    DIRECTION OUTPUT ;
    USE SIGNAL ;
    ANTENNADIFFAREA 2.724000 ;
    PORT
      LAYER Metal2 ;
        RECT 367.000 78.980 367.400 79.380 ;
    END
  END Tile_X1Y0_FrameStrobe_O[11]
  PIN Tile_X1Y0_FrameStrobe_O[12]
    DIRECTION OUTPUT ;
    USE SIGNAL ;
    ANTENNADIFFAREA 2.724000 ;
    PORT
      LAYER Metal2 ;
        RECT 378.520 78.980 378.920 79.380 ;
    END
  END Tile_X1Y0_FrameStrobe_O[12]
  PIN Tile_X1Y0_FrameStrobe_O[13]
    DIRECTION OUTPUT ;
    USE SIGNAL ;
    ANTENNADIFFAREA 2.724000 ;
    PORT
      LAYER Metal2 ;
        RECT 390.040 78.980 390.440 79.380 ;
    END
  END Tile_X1Y0_FrameStrobe_O[13]
  PIN Tile_X1Y0_FrameStrobe_O[14]
    DIRECTION OUTPUT ;
    USE SIGNAL ;
    ANTENNADIFFAREA 2.724000 ;
    PORT
      LAYER Metal2 ;
        RECT 401.560 78.980 401.960 79.380 ;
    END
  END Tile_X1Y0_FrameStrobe_O[14]
  PIN Tile_X1Y0_FrameStrobe_O[15]
    DIRECTION OUTPUT ;
    USE SIGNAL ;
    ANTENNADIFFAREA 2.724000 ;
    PORT
      LAYER Metal2 ;
        RECT 413.080 78.980 413.480 79.380 ;
    END
  END Tile_X1Y0_FrameStrobe_O[15]
  PIN Tile_X1Y0_FrameStrobe_O[16]
    DIRECTION OUTPUT ;
    USE SIGNAL ;
    ANTENNADIFFAREA 2.724000 ;
    PORT
      LAYER Metal2 ;
        RECT 424.600 78.980 425.000 79.380 ;
    END
  END Tile_X1Y0_FrameStrobe_O[16]
  PIN Tile_X1Y0_FrameStrobe_O[17]
    DIRECTION OUTPUT ;
    USE SIGNAL ;
    ANTENNADIFFAREA 2.724000 ;
    PORT
      LAYER Metal2 ;
        RECT 436.120 78.980 436.520 79.380 ;
    END
  END Tile_X1Y0_FrameStrobe_O[17]
  PIN Tile_X1Y0_FrameStrobe_O[18]
    DIRECTION OUTPUT ;
    USE SIGNAL ;
    ANTENNADIFFAREA 2.724000 ;
    PORT
      LAYER Metal2 ;
        RECT 447.640 78.980 448.040 79.380 ;
    END
  END Tile_X1Y0_FrameStrobe_O[18]
  PIN Tile_X1Y0_FrameStrobe_O[19]
    DIRECTION OUTPUT ;
    USE SIGNAL ;
    ANTENNADIFFAREA 2.724000 ;
    PORT
      LAYER Metal2 ;
        RECT 459.160 78.980 459.560 79.380 ;
    END
  END Tile_X1Y0_FrameStrobe_O[19]
  PIN Tile_X1Y0_FrameStrobe_O[1]
    DIRECTION OUTPUT ;
    USE SIGNAL ;
    ANTENNADIFFAREA 2.724000 ;
    PORT
      LAYER Metal2 ;
        RECT 251.800 78.980 252.200 79.380 ;
    END
  END Tile_X1Y0_FrameStrobe_O[1]
  PIN Tile_X1Y0_FrameStrobe_O[2]
    DIRECTION OUTPUT ;
    USE SIGNAL ;
    ANTENNADIFFAREA 2.724000 ;
    PORT
      LAYER Metal2 ;
        RECT 263.320 78.980 263.720 79.380 ;
    END
  END Tile_X1Y0_FrameStrobe_O[2]
  PIN Tile_X1Y0_FrameStrobe_O[3]
    DIRECTION OUTPUT ;
    USE SIGNAL ;
    ANTENNADIFFAREA 2.724000 ;
    PORT
      LAYER Metal2 ;
        RECT 274.840 78.980 275.240 79.380 ;
    END
  END Tile_X1Y0_FrameStrobe_O[3]
  PIN Tile_X1Y0_FrameStrobe_O[4]
    DIRECTION OUTPUT ;
    USE SIGNAL ;
    ANTENNADIFFAREA 2.724000 ;
    PORT
      LAYER Metal2 ;
        RECT 286.360 78.980 286.760 79.380 ;
    END
  END Tile_X1Y0_FrameStrobe_O[4]
  PIN Tile_X1Y0_FrameStrobe_O[5]
    DIRECTION OUTPUT ;
    USE SIGNAL ;
    ANTENNADIFFAREA 2.724000 ;
    PORT
      LAYER Metal2 ;
        RECT 297.880 78.980 298.280 79.380 ;
    END
  END Tile_X1Y0_FrameStrobe_O[5]
  PIN Tile_X1Y0_FrameStrobe_O[6]
    DIRECTION OUTPUT ;
    USE SIGNAL ;
    ANTENNADIFFAREA 2.724000 ;
    PORT
      LAYER Metal2 ;
        RECT 309.400 78.980 309.800 79.380 ;
    END
  END Tile_X1Y0_FrameStrobe_O[6]
  PIN Tile_X1Y0_FrameStrobe_O[7]
    DIRECTION OUTPUT ;
    USE SIGNAL ;
    ANTENNADIFFAREA 2.724000 ;
    PORT
      LAYER Metal2 ;
        RECT 320.920 78.980 321.320 79.380 ;
    END
  END Tile_X1Y0_FrameStrobe_O[7]
  PIN Tile_X1Y0_FrameStrobe_O[8]
    DIRECTION OUTPUT ;
    USE SIGNAL ;
    ANTENNADIFFAREA 2.724000 ;
    PORT
      LAYER Metal2 ;
        RECT 332.440 78.980 332.840 79.380 ;
    END
  END Tile_X1Y0_FrameStrobe_O[8]
  PIN Tile_X1Y0_FrameStrobe_O[9]
    DIRECTION OUTPUT ;
    USE SIGNAL ;
    ANTENNADIFFAREA 2.724000 ;
    PORT
      LAYER Metal2 ;
        RECT 343.960 78.980 344.360 79.380 ;
    END
  END Tile_X1Y0_FrameStrobe_O[9]
  PIN Tile_X1Y0_N1END[0]
    DIRECTION INPUT ;
    USE SIGNAL ;
    ANTENNAGATEAREA 0.607100 ;
    PORT
      LAYER Metal2 ;
        RECT 234.520 0.000 234.920 0.400 ;
    END
  END Tile_X1Y0_N1END[0]
  PIN Tile_X1Y0_N1END[1]
    DIRECTION INPUT ;
    USE SIGNAL ;
    ANTENNAGATEAREA 0.607100 ;
    ANTENNADIFFAREA 18.138599 ;
    PORT
      LAYER Metal2 ;
        RECT 236.440 0.000 236.840 0.400 ;
    END
  END Tile_X1Y0_N1END[1]
  PIN Tile_X1Y0_N1END[2]
    DIRECTION INPUT ;
    USE SIGNAL ;
    ANTENNAGATEAREA 0.607100 ;
    PORT
      LAYER Metal2 ;
        RECT 238.360 0.000 238.760 0.400 ;
    END
  END Tile_X1Y0_N1END[2]
  PIN Tile_X1Y0_N1END[3]
    DIRECTION INPUT ;
    USE SIGNAL ;
    ANTENNAGATEAREA 0.607100 ;
    ANTENNADIFFAREA 18.138599 ;
    PORT
      LAYER Metal2 ;
        RECT 240.280 0.000 240.680 0.400 ;
    END
  END Tile_X1Y0_N1END[3]
  PIN Tile_X1Y0_N2END[0]
    DIRECTION INPUT ;
    USE SIGNAL ;
    ANTENNAGATEAREA 0.639600 ;
    ANTENNADIFFAREA 6.046200 ;
    PORT
      LAYER Metal2 ;
        RECT 259.480 0.000 259.880 0.400 ;
    END
  END Tile_X1Y0_N2END[0]
  PIN Tile_X1Y0_N2END[1]
    DIRECTION INPUT ;
    USE SIGNAL ;
    ANTENNAGATEAREA 0.639600 ;
    PORT
      LAYER Metal2 ;
        RECT 260.440 0.000 260.840 0.400 ;
    END
  END Tile_X1Y0_N2END[1]
  PIN Tile_X1Y0_N2END[2]
    DIRECTION INPUT ;
    USE SIGNAL ;
    ANTENNAGATEAREA 0.639600 ;
    PORT
      LAYER Metal2 ;
        RECT 261.400 0.000 261.800 0.400 ;
    END
  END Tile_X1Y0_N2END[2]
  PIN Tile_X1Y0_N2END[3]
    DIRECTION INPUT ;
    USE SIGNAL ;
    ANTENNAGATEAREA 0.639600 ;
    PORT
      LAYER Metal2 ;
        RECT 262.360 0.000 262.760 0.400 ;
    END
  END Tile_X1Y0_N2END[3]
  PIN Tile_X1Y0_N2END[4]
    DIRECTION INPUT ;
    USE SIGNAL ;
    ANTENNAGATEAREA 0.639600 ;
    ANTENNADIFFAREA 18.138599 ;
    PORT
      LAYER Metal2 ;
        RECT 263.320 0.000 263.720 0.400 ;
    END
  END Tile_X1Y0_N2END[4]
  PIN Tile_X1Y0_N2END[5]
    DIRECTION INPUT ;
    USE SIGNAL ;
    ANTENNAGATEAREA 0.639600 ;
    PORT
      LAYER Metal2 ;
        RECT 264.280 0.000 264.680 0.400 ;
    END
  END Tile_X1Y0_N2END[5]
  PIN Tile_X1Y0_N2END[6]
    DIRECTION INPUT ;
    USE SIGNAL ;
    ANTENNAGATEAREA 0.639600 ;
    PORT
      LAYER Metal2 ;
        RECT 265.240 0.000 265.640 0.400 ;
    END
  END Tile_X1Y0_N2END[6]
  PIN Tile_X1Y0_N2END[7]
    DIRECTION INPUT ;
    USE SIGNAL ;
    ANTENNAGATEAREA 0.639600 ;
    PORT
      LAYER Metal2 ;
        RECT 266.200 0.000 266.600 0.400 ;
    END
  END Tile_X1Y0_N2END[7]
  PIN Tile_X1Y0_N2MID[0]
    DIRECTION INPUT ;
    USE SIGNAL ;
    ANTENNAGATEAREA 0.820300 ;
    PORT
      LAYER Metal2 ;
        RECT 245.080 0.000 245.480 0.400 ;
    END
  END Tile_X1Y0_N2MID[0]
  PIN Tile_X1Y0_N2MID[1]
    DIRECTION INPUT ;
    USE SIGNAL ;
    ANTENNAGATEAREA 0.820300 ;
    PORT
      LAYER Metal2 ;
        RECT 246.040 0.000 246.440 0.400 ;
    END
  END Tile_X1Y0_N2MID[1]
  PIN Tile_X1Y0_N2MID[2]
    DIRECTION INPUT ;
    USE SIGNAL ;
    ANTENNAGATEAREA 0.820300 ;
    PORT
      LAYER Metal2 ;
        RECT 247.000 0.000 247.400 0.400 ;
    END
  END Tile_X1Y0_N2MID[2]
  PIN Tile_X1Y0_N2MID[3]
    DIRECTION INPUT ;
    USE SIGNAL ;
    ANTENNAGATEAREA 0.820300 ;
    ANTENNADIFFAREA 8.061600 ;
    PORT
      LAYER Metal2 ;
        RECT 247.960 0.000 248.360 0.400 ;
    END
  END Tile_X1Y0_N2MID[3]
  PIN Tile_X1Y0_N2MID[4]
    DIRECTION INPUT ;
    USE SIGNAL ;
    ANTENNAGATEAREA 0.820300 ;
    PORT
      LAYER Metal2 ;
        RECT 248.920 0.000 249.320 0.400 ;
    END
  END Tile_X1Y0_N2MID[4]
  PIN Tile_X1Y0_N2MID[5]
    DIRECTION INPUT ;
    USE SIGNAL ;
    ANTENNAGATEAREA 0.820300 ;
    PORT
      LAYER Metal2 ;
        RECT 249.880 0.000 250.280 0.400 ;
    END
  END Tile_X1Y0_N2MID[5]
  PIN Tile_X1Y0_N2MID[6]
    DIRECTION INPUT ;
    USE SIGNAL ;
    ANTENNAGATEAREA 0.820300 ;
    PORT
      LAYER Metal2 ;
        RECT 250.840 0.000 251.240 0.400 ;
    END
  END Tile_X1Y0_N2MID[6]
  PIN Tile_X1Y0_N2MID[7]
    DIRECTION INPUT ;
    USE SIGNAL ;
    ANTENNAGATEAREA 0.820300 ;
    ANTENNADIFFAREA 8.061600 ;
    PORT
      LAYER Metal2 ;
        RECT 251.800 0.000 252.200 0.400 ;
    END
  END Tile_X1Y0_N2MID[7]
  PIN Tile_X1Y0_N4END[0]
    DIRECTION INPUT ;
    USE SIGNAL ;
    ANTENNAGATEAREA 0.852800 ;
    PORT
      LAYER Metal2 ;
        RECT 277.720 0.000 278.120 0.400 ;
    END
  END Tile_X1Y0_N4END[0]
  PIN Tile_X1Y0_N4END[10]
    DIRECTION INPUT ;
    USE SIGNAL ;
    ANTENNAGATEAREA 0.852800 ;
    PORT
      LAYER Metal2 ;
        RECT 287.320 0.000 287.720 0.400 ;
    END
  END Tile_X1Y0_N4END[10]
  PIN Tile_X1Y0_N4END[11]
    DIRECTION INPUT ;
    USE SIGNAL ;
    ANTENNAGATEAREA 0.852800 ;
    PORT
      LAYER Metal2 ;
        RECT 288.280 0.000 288.680 0.400 ;
    END
  END Tile_X1Y0_N4END[11]
  PIN Tile_X1Y0_N4END[12]
    DIRECTION INPUT ;
    USE SIGNAL ;
    ANTENNAGATEAREA 0.852800 ;
    PORT
      LAYER Metal2 ;
        RECT 289.240 0.000 289.640 0.400 ;
    END
  END Tile_X1Y0_N4END[12]
  PIN Tile_X1Y0_N4END[13]
    DIRECTION INPUT ;
    USE SIGNAL ;
    ANTENNAGATEAREA 0.852800 ;
    PORT
      LAYER Metal2 ;
        RECT 290.200 0.000 290.600 0.400 ;
    END
  END Tile_X1Y0_N4END[13]
  PIN Tile_X1Y0_N4END[14]
    DIRECTION INPUT ;
    USE SIGNAL ;
    ANTENNAGATEAREA 0.852800 ;
    PORT
      LAYER Metal2 ;
        RECT 291.160 0.000 291.560 0.400 ;
    END
  END Tile_X1Y0_N4END[14]
  PIN Tile_X1Y0_N4END[15]
    DIRECTION INPUT ;
    USE SIGNAL ;
    ANTENNAGATEAREA 0.852800 ;
    PORT
      LAYER Metal2 ;
        RECT 292.120 0.000 292.520 0.400 ;
    END
  END Tile_X1Y0_N4END[15]
  PIN Tile_X1Y0_N4END[1]
    DIRECTION INPUT ;
    USE SIGNAL ;
    ANTENNAGATEAREA 0.852800 ;
    PORT
      LAYER Metal2 ;
        RECT 278.680 0.000 279.080 0.400 ;
    END
  END Tile_X1Y0_N4END[1]
  PIN Tile_X1Y0_N4END[2]
    DIRECTION INPUT ;
    USE SIGNAL ;
    ANTENNAGATEAREA 0.852800 ;
    PORT
      LAYER Metal2 ;
        RECT 279.640 0.000 280.040 0.400 ;
    END
  END Tile_X1Y0_N4END[2]
  PIN Tile_X1Y0_N4END[3]
    DIRECTION INPUT ;
    USE SIGNAL ;
    ANTENNAGATEAREA 0.852800 ;
    PORT
      LAYER Metal2 ;
        RECT 280.600 0.000 281.000 0.400 ;
    END
  END Tile_X1Y0_N4END[3]
  PIN Tile_X1Y0_N4END[4]
    DIRECTION INPUT ;
    USE SIGNAL ;
    ANTENNAGATEAREA 0.852800 ;
    PORT
      LAYER Metal2 ;
        RECT 281.560 0.000 281.960 0.400 ;
    END
  END Tile_X1Y0_N4END[4]
  PIN Tile_X1Y0_N4END[5]
    DIRECTION INPUT ;
    USE SIGNAL ;
    ANTENNAGATEAREA 0.852800 ;
    PORT
      LAYER Metal2 ;
        RECT 282.520 0.000 282.920 0.400 ;
    END
  END Tile_X1Y0_N4END[5]
  PIN Tile_X1Y0_N4END[6]
    DIRECTION INPUT ;
    USE SIGNAL ;
    ANTENNAGATEAREA 0.852800 ;
    PORT
      LAYER Metal2 ;
        RECT 283.480 0.000 283.880 0.400 ;
    END
  END Tile_X1Y0_N4END[6]
  PIN Tile_X1Y0_N4END[7]
    DIRECTION INPUT ;
    USE SIGNAL ;
    ANTENNAGATEAREA 0.852800 ;
    PORT
      LAYER Metal2 ;
        RECT 284.440 0.000 284.840 0.400 ;
    END
  END Tile_X1Y0_N4END[7]
  PIN Tile_X1Y0_N4END[8]
    DIRECTION INPUT ;
    USE SIGNAL ;
    ANTENNAGATEAREA 0.852800 ;
    PORT
      LAYER Metal2 ;
        RECT 285.400 0.000 285.800 0.400 ;
    END
  END Tile_X1Y0_N4END[8]
  PIN Tile_X1Y0_N4END[9]
    DIRECTION INPUT ;
    USE SIGNAL ;
    ANTENNAGATEAREA 0.852800 ;
    PORT
      LAYER Metal2 ;
        RECT 286.360 0.000 286.760 0.400 ;
    END
  END Tile_X1Y0_N4END[9]
  PIN Tile_X1Y0_NN4END[0]
    DIRECTION INPUT ;
    USE SIGNAL ;
    ANTENNAGATEAREA 0.852800 ;
    PORT
      LAYER Metal2 ;
        RECT 307.480 0.000 307.880 0.400 ;
    END
  END Tile_X1Y0_NN4END[0]
  PIN Tile_X1Y0_NN4END[10]
    DIRECTION INPUT ;
    USE SIGNAL ;
    ANTENNAGATEAREA 0.852800 ;
    PORT
      LAYER Metal2 ;
        RECT 317.080 0.000 317.480 0.400 ;
    END
  END Tile_X1Y0_NN4END[10]
  PIN Tile_X1Y0_NN4END[11]
    DIRECTION INPUT ;
    USE SIGNAL ;
    ANTENNAGATEAREA 0.852800 ;
    PORT
      LAYER Metal2 ;
        RECT 318.040 0.000 318.440 0.400 ;
    END
  END Tile_X1Y0_NN4END[11]
  PIN Tile_X1Y0_NN4END[12]
    DIRECTION INPUT ;
    USE SIGNAL ;
    ANTENNAGATEAREA 0.852800 ;
    PORT
      LAYER Metal2 ;
        RECT 319.000 0.000 319.400 0.400 ;
    END
  END Tile_X1Y0_NN4END[12]
  PIN Tile_X1Y0_NN4END[13]
    DIRECTION INPUT ;
    USE SIGNAL ;
    ANTENNAGATEAREA 0.852800 ;
    PORT
      LAYER Metal2 ;
        RECT 319.960 0.000 320.360 0.400 ;
    END
  END Tile_X1Y0_NN4END[13]
  PIN Tile_X1Y0_NN4END[14]
    DIRECTION INPUT ;
    USE SIGNAL ;
    ANTENNAGATEAREA 0.852800 ;
    PORT
      LAYER Metal2 ;
        RECT 320.920 0.000 321.320 0.400 ;
    END
  END Tile_X1Y0_NN4END[14]
  PIN Tile_X1Y0_NN4END[15]
    DIRECTION INPUT ;
    USE SIGNAL ;
    ANTENNAGATEAREA 0.852800 ;
    PORT
      LAYER Metal2 ;
        RECT 321.880 0.000 322.280 0.400 ;
    END
  END Tile_X1Y0_NN4END[15]
  PIN Tile_X1Y0_NN4END[1]
    DIRECTION INPUT ;
    USE SIGNAL ;
    ANTENNAGATEAREA 0.852800 ;
    PORT
      LAYER Metal2 ;
        RECT 308.440 0.000 308.840 0.400 ;
    END
  END Tile_X1Y0_NN4END[1]
  PIN Tile_X1Y0_NN4END[2]
    DIRECTION INPUT ;
    USE SIGNAL ;
    ANTENNAGATEAREA 0.852800 ;
    PORT
      LAYER Metal2 ;
        RECT 309.400 0.000 309.800 0.400 ;
    END
  END Tile_X1Y0_NN4END[2]
  PIN Tile_X1Y0_NN4END[3]
    DIRECTION INPUT ;
    USE SIGNAL ;
    ANTENNAGATEAREA 0.852800 ;
    PORT
      LAYER Metal2 ;
        RECT 310.360 0.000 310.760 0.400 ;
    END
  END Tile_X1Y0_NN4END[3]
  PIN Tile_X1Y0_NN4END[4]
    DIRECTION INPUT ;
    USE SIGNAL ;
    ANTENNAGATEAREA 0.852800 ;
    PORT
      LAYER Metal2 ;
        RECT 311.320 0.000 311.720 0.400 ;
    END
  END Tile_X1Y0_NN4END[4]
  PIN Tile_X1Y0_NN4END[5]
    DIRECTION INPUT ;
    USE SIGNAL ;
    ANTENNAGATEAREA 0.852800 ;
    PORT
      LAYER Metal2 ;
        RECT 312.280 0.000 312.680 0.400 ;
    END
  END Tile_X1Y0_NN4END[5]
  PIN Tile_X1Y0_NN4END[6]
    DIRECTION INPUT ;
    USE SIGNAL ;
    ANTENNAGATEAREA 0.852800 ;
    PORT
      LAYER Metal2 ;
        RECT 313.240 0.000 313.640 0.400 ;
    END
  END Tile_X1Y0_NN4END[6]
  PIN Tile_X1Y0_NN4END[7]
    DIRECTION INPUT ;
    USE SIGNAL ;
    ANTENNAGATEAREA 0.852800 ;
    PORT
      LAYER Metal2 ;
        RECT 314.200 0.000 314.600 0.400 ;
    END
  END Tile_X1Y0_NN4END[7]
  PIN Tile_X1Y0_NN4END[8]
    DIRECTION INPUT ;
    USE SIGNAL ;
    ANTENNAGATEAREA 0.852800 ;
    PORT
      LAYER Metal2 ;
        RECT 315.160 0.000 315.560 0.400 ;
    END
  END Tile_X1Y0_NN4END[8]
  PIN Tile_X1Y0_NN4END[9]
    DIRECTION INPUT ;
    USE SIGNAL ;
    ANTENNAGATEAREA 0.852800 ;
    PORT
      LAYER Metal2 ;
        RECT 316.120 0.000 316.520 0.400 ;
    END
  END Tile_X1Y0_NN4END[9]
  PIN Tile_X1Y0_S1BEG[0]
    DIRECTION OUTPUT ;
    USE SIGNAL ;
    ANTENNADIFFAREA 2.724000 ;
    PORT
      LAYER Metal2 ;
        RECT 332.440 0.000 332.840 0.400 ;
    END
  END Tile_X1Y0_S1BEG[0]
  PIN Tile_X1Y0_S1BEG[1]
    DIRECTION OUTPUT ;
    USE SIGNAL ;
    ANTENNADIFFAREA 2.724000 ;
    PORT
      LAYER Metal2 ;
        RECT 334.360 0.000 334.760 0.400 ;
    END
  END Tile_X1Y0_S1BEG[1]
  PIN Tile_X1Y0_S1BEG[2]
    DIRECTION OUTPUT ;
    USE SIGNAL ;
    ANTENNADIFFAREA 2.724000 ;
    PORT
      LAYER Metal2 ;
        RECT 336.280 0.000 336.680 0.400 ;
    END
  END Tile_X1Y0_S1BEG[2]
  PIN Tile_X1Y0_S1BEG[3]
    DIRECTION OUTPUT ;
    USE SIGNAL ;
    ANTENNADIFFAREA 2.724000 ;
    PORT
      LAYER Metal2 ;
        RECT 338.200 0.000 338.600 0.400 ;
    END
  END Tile_X1Y0_S1BEG[3]
  PIN Tile_X1Y0_S2BEG[0]
    DIRECTION OUTPUT ;
    USE SIGNAL ;
    ANTENNADIFFAREA 2.724000 ;
    PORT
      LAYER Metal2 ;
        RECT 340.120 0.000 340.520 0.400 ;
    END
  END Tile_X1Y0_S2BEG[0]
  PIN Tile_X1Y0_S2BEG[1]
    DIRECTION OUTPUT ;
    USE SIGNAL ;
    ANTENNADIFFAREA 2.724000 ;
    PORT
      LAYER Metal2 ;
        RECT 342.040 0.000 342.440 0.400 ;
    END
  END Tile_X1Y0_S2BEG[1]
  PIN Tile_X1Y0_S2BEG[2]
    DIRECTION OUTPUT ;
    USE SIGNAL ;
    ANTENNADIFFAREA 2.724000 ;
    PORT
      LAYER Metal2 ;
        RECT 343.960 0.000 344.360 0.400 ;
    END
  END Tile_X1Y0_S2BEG[2]
  PIN Tile_X1Y0_S2BEG[3]
    DIRECTION OUTPUT ;
    USE SIGNAL ;
    ANTENNADIFFAREA 2.724000 ;
    PORT
      LAYER Metal2 ;
        RECT 345.880 0.000 346.280 0.400 ;
    END
  END Tile_X1Y0_S2BEG[3]
  PIN Tile_X1Y0_S2BEG[4]
    DIRECTION OUTPUT ;
    USE SIGNAL ;
    ANTENNADIFFAREA 2.724000 ;
    PORT
      LAYER Metal2 ;
        RECT 347.800 0.000 348.200 0.400 ;
    END
  END Tile_X1Y0_S2BEG[4]
  PIN Tile_X1Y0_S2BEG[5]
    DIRECTION OUTPUT ;
    USE SIGNAL ;
    ANTENNADIFFAREA 2.724000 ;
    PORT
      LAYER Metal2 ;
        RECT 349.720 0.000 350.120 0.400 ;
    END
  END Tile_X1Y0_S2BEG[5]
  PIN Tile_X1Y0_S2BEG[6]
    DIRECTION OUTPUT ;
    USE SIGNAL ;
    ANTENNADIFFAREA 2.724000 ;
    PORT
      LAYER Metal2 ;
        RECT 351.640 0.000 352.040 0.400 ;
    END
  END Tile_X1Y0_S2BEG[6]
  PIN Tile_X1Y0_S2BEG[7]
    DIRECTION OUTPUT ;
    USE SIGNAL ;
    ANTENNADIFFAREA 2.724000 ;
    PORT
      LAYER Metal2 ;
        RECT 353.560 0.000 353.960 0.400 ;
    END
  END Tile_X1Y0_S2BEG[7]
  PIN Tile_X1Y0_S2BEGb[0]
    DIRECTION OUTPUT ;
    USE SIGNAL ;
    ANTENNADIFFAREA 2.724000 ;
    PORT
      LAYER Metal2 ;
        RECT 358.360 0.000 358.760 0.400 ;
    END
  END Tile_X1Y0_S2BEGb[0]
  PIN Tile_X1Y0_S2BEGb[1]
    DIRECTION OUTPUT ;
    USE SIGNAL ;
    ANTENNADIFFAREA 2.724000 ;
    PORT
      LAYER Metal2 ;
        RECT 359.320 0.000 359.720 0.400 ;
    END
  END Tile_X1Y0_S2BEGb[1]
  PIN Tile_X1Y0_S2BEGb[2]
    DIRECTION OUTPUT ;
    USE SIGNAL ;
    ANTENNADIFFAREA 2.724000 ;
    PORT
      LAYER Metal2 ;
        RECT 360.280 0.000 360.680 0.400 ;
    END
  END Tile_X1Y0_S2BEGb[2]
  PIN Tile_X1Y0_S2BEGb[3]
    DIRECTION OUTPUT ;
    USE SIGNAL ;
    ANTENNADIFFAREA 2.724000 ;
    PORT
      LAYER Metal2 ;
        RECT 361.240 0.000 361.640 0.400 ;
    END
  END Tile_X1Y0_S2BEGb[3]
  PIN Tile_X1Y0_S2BEGb[4]
    DIRECTION OUTPUT ;
    USE SIGNAL ;
    ANTENNADIFFAREA 2.724000 ;
    PORT
      LAYER Metal2 ;
        RECT 362.200 0.000 362.600 0.400 ;
    END
  END Tile_X1Y0_S2BEGb[4]
  PIN Tile_X1Y0_S2BEGb[5]
    DIRECTION OUTPUT ;
    USE SIGNAL ;
    ANTENNADIFFAREA 2.724000 ;
    PORT
      LAYER Metal2 ;
        RECT 363.160 0.000 363.560 0.400 ;
    END
  END Tile_X1Y0_S2BEGb[5]
  PIN Tile_X1Y0_S2BEGb[6]
    DIRECTION OUTPUT ;
    USE SIGNAL ;
    ANTENNADIFFAREA 2.724000 ;
    PORT
      LAYER Metal2 ;
        RECT 364.120 0.000 364.520 0.400 ;
    END
  END Tile_X1Y0_S2BEGb[6]
  PIN Tile_X1Y0_S2BEGb[7]
    DIRECTION OUTPUT ;
    USE SIGNAL ;
    ANTENNADIFFAREA 2.724000 ;
    PORT
      LAYER Metal2 ;
        RECT 365.080 0.000 365.480 0.400 ;
    END
  END Tile_X1Y0_S2BEGb[7]
  PIN Tile_X1Y0_S4BEG[0]
    DIRECTION OUTPUT ;
    USE SIGNAL ;
    ANTENNADIFFAREA 2.724000 ;
    PORT
      LAYER Metal2 ;
        RECT 376.600 0.000 377.000 0.400 ;
    END
  END Tile_X1Y0_S4BEG[0]
  PIN Tile_X1Y0_S4BEG[10]
    DIRECTION OUTPUT ;
    USE SIGNAL ;
    ANTENNADIFFAREA 2.724000 ;
    PORT
      LAYER Metal2 ;
        RECT 386.200 0.000 386.600 0.400 ;
    END
  END Tile_X1Y0_S4BEG[10]
  PIN Tile_X1Y0_S4BEG[11]
    DIRECTION OUTPUT ;
    USE SIGNAL ;
    ANTENNADIFFAREA 2.724000 ;
    PORT
      LAYER Metal2 ;
        RECT 387.160 0.000 387.560 0.400 ;
    END
  END Tile_X1Y0_S4BEG[11]
  PIN Tile_X1Y0_S4BEG[12]
    DIRECTION OUTPUT ;
    USE SIGNAL ;
    ANTENNADIFFAREA 2.724000 ;
    PORT
      LAYER Metal2 ;
        RECT 388.120 0.000 388.520 0.400 ;
    END
  END Tile_X1Y0_S4BEG[12]
  PIN Tile_X1Y0_S4BEG[13]
    DIRECTION OUTPUT ;
    USE SIGNAL ;
    ANTENNADIFFAREA 2.724000 ;
    PORT
      LAYER Metal2 ;
        RECT 389.080 0.000 389.480 0.400 ;
    END
  END Tile_X1Y0_S4BEG[13]
  PIN Tile_X1Y0_S4BEG[14]
    DIRECTION OUTPUT ;
    USE SIGNAL ;
    ANTENNADIFFAREA 2.724000 ;
    PORT
      LAYER Metal2 ;
        RECT 390.040 0.000 390.440 0.400 ;
    END
  END Tile_X1Y0_S4BEG[14]
  PIN Tile_X1Y0_S4BEG[15]
    DIRECTION OUTPUT ;
    USE SIGNAL ;
    ANTENNADIFFAREA 2.724000 ;
    PORT
      LAYER Metal2 ;
        RECT 391.000 0.000 391.400 0.400 ;
    END
  END Tile_X1Y0_S4BEG[15]
  PIN Tile_X1Y0_S4BEG[1]
    DIRECTION OUTPUT ;
    USE SIGNAL ;
    ANTENNADIFFAREA 2.724000 ;
    PORT
      LAYER Metal2 ;
        RECT 377.560 0.000 377.960 0.400 ;
    END
  END Tile_X1Y0_S4BEG[1]
  PIN Tile_X1Y0_S4BEG[2]
    DIRECTION OUTPUT ;
    USE SIGNAL ;
    ANTENNADIFFAREA 2.724000 ;
    PORT
      LAYER Metal2 ;
        RECT 378.520 0.000 378.920 0.400 ;
    END
  END Tile_X1Y0_S4BEG[2]
  PIN Tile_X1Y0_S4BEG[3]
    DIRECTION OUTPUT ;
    USE SIGNAL ;
    ANTENNADIFFAREA 2.724000 ;
    PORT
      LAYER Metal2 ;
        RECT 379.480 0.000 379.880 0.400 ;
    END
  END Tile_X1Y0_S4BEG[3]
  PIN Tile_X1Y0_S4BEG[4]
    DIRECTION OUTPUT ;
    USE SIGNAL ;
    ANTENNADIFFAREA 2.724000 ;
    PORT
      LAYER Metal2 ;
        RECT 380.440 0.000 380.840 0.400 ;
    END
  END Tile_X1Y0_S4BEG[4]
  PIN Tile_X1Y0_S4BEG[5]
    DIRECTION OUTPUT ;
    USE SIGNAL ;
    ANTENNADIFFAREA 2.724000 ;
    PORT
      LAYER Metal2 ;
        RECT 381.400 0.000 381.800 0.400 ;
    END
  END Tile_X1Y0_S4BEG[5]
  PIN Tile_X1Y0_S4BEG[6]
    DIRECTION OUTPUT ;
    USE SIGNAL ;
    ANTENNADIFFAREA 2.724000 ;
    PORT
      LAYER Metal2 ;
        RECT 382.360 0.000 382.760 0.400 ;
    END
  END Tile_X1Y0_S4BEG[6]
  PIN Tile_X1Y0_S4BEG[7]
    DIRECTION OUTPUT ;
    USE SIGNAL ;
    ANTENNADIFFAREA 2.724000 ;
    PORT
      LAYER Metal2 ;
        RECT 383.320 0.000 383.720 0.400 ;
    END
  END Tile_X1Y0_S4BEG[7]
  PIN Tile_X1Y0_S4BEG[8]
    DIRECTION OUTPUT ;
    USE SIGNAL ;
    ANTENNADIFFAREA 2.724000 ;
    PORT
      LAYER Metal2 ;
        RECT 384.280 0.000 384.680 0.400 ;
    END
  END Tile_X1Y0_S4BEG[8]
  PIN Tile_X1Y0_S4BEG[9]
    DIRECTION OUTPUT ;
    USE SIGNAL ;
    ANTENNADIFFAREA 2.724000 ;
    PORT
      LAYER Metal2 ;
        RECT 385.240 0.000 385.640 0.400 ;
    END
  END Tile_X1Y0_S4BEG[9]
  PIN Tile_X1Y0_SS4BEG[0]
    DIRECTION OUTPUT ;
    USE SIGNAL ;
    ANTENNADIFFAREA 2.724000 ;
    PORT
      LAYER Metal2 ;
        RECT 406.360 0.000 406.760 0.400 ;
    END
  END Tile_X1Y0_SS4BEG[0]
  PIN Tile_X1Y0_SS4BEG[10]
    DIRECTION OUTPUT ;
    USE SIGNAL ;
    ANTENNADIFFAREA 2.724000 ;
    PORT
      LAYER Metal2 ;
        RECT 415.960 0.000 416.360 0.400 ;
    END
  END Tile_X1Y0_SS4BEG[10]
  PIN Tile_X1Y0_SS4BEG[11]
    DIRECTION OUTPUT ;
    USE SIGNAL ;
    ANTENNADIFFAREA 2.724000 ;
    PORT
      LAYER Metal2 ;
        RECT 416.920 0.000 417.320 0.400 ;
    END
  END Tile_X1Y0_SS4BEG[11]
  PIN Tile_X1Y0_SS4BEG[12]
    DIRECTION OUTPUT ;
    USE SIGNAL ;
    ANTENNADIFFAREA 2.724000 ;
    PORT
      LAYER Metal2 ;
        RECT 417.880 0.000 418.280 0.400 ;
    END
  END Tile_X1Y0_SS4BEG[12]
  PIN Tile_X1Y0_SS4BEG[13]
    DIRECTION OUTPUT ;
    USE SIGNAL ;
    ANTENNADIFFAREA 2.724000 ;
    PORT
      LAYER Metal2 ;
        RECT 418.840 0.000 419.240 0.400 ;
    END
  END Tile_X1Y0_SS4BEG[13]
  PIN Tile_X1Y0_SS4BEG[14]
    DIRECTION OUTPUT ;
    USE SIGNAL ;
    ANTENNADIFFAREA 2.724000 ;
    PORT
      LAYER Metal2 ;
        RECT 419.800 0.000 420.200 0.400 ;
    END
  END Tile_X1Y0_SS4BEG[14]
  PIN Tile_X1Y0_SS4BEG[15]
    DIRECTION OUTPUT ;
    USE SIGNAL ;
    ANTENNADIFFAREA 2.724000 ;
    PORT
      LAYER Metal2 ;
        RECT 420.760 0.000 421.160 0.400 ;
    END
  END Tile_X1Y0_SS4BEG[15]
  PIN Tile_X1Y0_SS4BEG[1]
    DIRECTION OUTPUT ;
    USE SIGNAL ;
    ANTENNADIFFAREA 2.724000 ;
    PORT
      LAYER Metal2 ;
        RECT 407.320 0.000 407.720 0.400 ;
    END
  END Tile_X1Y0_SS4BEG[1]
  PIN Tile_X1Y0_SS4BEG[2]
    DIRECTION OUTPUT ;
    USE SIGNAL ;
    ANTENNADIFFAREA 2.724000 ;
    PORT
      LAYER Metal2 ;
        RECT 408.280 0.000 408.680 0.400 ;
    END
  END Tile_X1Y0_SS4BEG[2]
  PIN Tile_X1Y0_SS4BEG[3]
    DIRECTION OUTPUT ;
    USE SIGNAL ;
    ANTENNADIFFAREA 2.724000 ;
    PORT
      LAYER Metal2 ;
        RECT 409.240 0.000 409.640 0.400 ;
    END
  END Tile_X1Y0_SS4BEG[3]
  PIN Tile_X1Y0_SS4BEG[4]
    DIRECTION OUTPUT ;
    USE SIGNAL ;
    ANTENNADIFFAREA 2.724000 ;
    PORT
      LAYER Metal2 ;
        RECT 410.200 0.000 410.600 0.400 ;
    END
  END Tile_X1Y0_SS4BEG[4]
  PIN Tile_X1Y0_SS4BEG[5]
    DIRECTION OUTPUT ;
    USE SIGNAL ;
    ANTENNADIFFAREA 2.724000 ;
    PORT
      LAYER Metal2 ;
        RECT 411.160 0.000 411.560 0.400 ;
    END
  END Tile_X1Y0_SS4BEG[5]
  PIN Tile_X1Y0_SS4BEG[6]
    DIRECTION OUTPUT ;
    USE SIGNAL ;
    ANTENNADIFFAREA 2.724000 ;
    PORT
      LAYER Metal2 ;
        RECT 412.120 0.000 412.520 0.400 ;
    END
  END Tile_X1Y0_SS4BEG[6]
  PIN Tile_X1Y0_SS4BEG[7]
    DIRECTION OUTPUT ;
    USE SIGNAL ;
    ANTENNADIFFAREA 2.724000 ;
    PORT
      LAYER Metal2 ;
        RECT 413.080 0.000 413.480 0.400 ;
    END
  END Tile_X1Y0_SS4BEG[7]
  PIN Tile_X1Y0_SS4BEG[8]
    DIRECTION OUTPUT ;
    USE SIGNAL ;
    ANTENNADIFFAREA 2.724000 ;
    PORT
      LAYER Metal2 ;
        RECT 414.040 0.000 414.440 0.400 ;
    END
  END Tile_X1Y0_SS4BEG[8]
  PIN Tile_X1Y0_SS4BEG[9]
    DIRECTION OUTPUT ;
    USE SIGNAL ;
    ANTENNADIFFAREA 2.724000 ;
    PORT
      LAYER Metal2 ;
        RECT 415.000 0.000 415.400 0.400 ;
    END
  END Tile_X1Y0_SS4BEG[9]
  PIN Tile_X2Y0_Ci
    DIRECTION INPUT ;
    USE SIGNAL ;
    PORT
      LAYER Metal2 ;
        RECT 563.800 0.000 564.200 0.400 ;
    END
  END Tile_X2Y0_Ci
  PIN Tile_X2Y0_FrameStrobe[0]
    DIRECTION INPUT ;
    USE SIGNAL ;
    ANTENNAGATEAREA 11.745500 ;
    PORT
      LAYER Metal2 ;
        RECT 671.320 0.000 671.720 0.400 ;
    END
  END Tile_X2Y0_FrameStrobe[0]
  PIN Tile_X2Y0_FrameStrobe[10]
    DIRECTION INPUT ;
    USE SIGNAL ;
    ANTENNAGATEAREA 0.180700 ;
    PORT
      LAYER Metal2 ;
        RECT 680.920 0.000 681.320 0.400 ;
    END
  END Tile_X2Y0_FrameStrobe[10]
  PIN Tile_X2Y0_FrameStrobe[11]
    DIRECTION INPUT ;
    USE SIGNAL ;
    ANTENNAGATEAREA 0.180700 ;
    PORT
      LAYER Metal2 ;
        RECT 681.880 0.000 682.280 0.400 ;
    END
  END Tile_X2Y0_FrameStrobe[11]
  PIN Tile_X2Y0_FrameStrobe[12]
    DIRECTION INPUT ;
    USE SIGNAL ;
    ANTENNAGATEAREA 0.180700 ;
    PORT
      LAYER Metal2 ;
        RECT 682.840 0.000 683.240 0.400 ;
    END
  END Tile_X2Y0_FrameStrobe[12]
  PIN Tile_X2Y0_FrameStrobe[13]
    DIRECTION INPUT ;
    USE SIGNAL ;
    ANTENNAGATEAREA 0.180700 ;
    PORT
      LAYER Metal2 ;
        RECT 683.800 0.000 684.200 0.400 ;
    END
  END Tile_X2Y0_FrameStrobe[13]
  PIN Tile_X2Y0_FrameStrobe[14]
    DIRECTION INPUT ;
    USE SIGNAL ;
    ANTENNAGATEAREA 0.180700 ;
    PORT
      LAYER Metal2 ;
        RECT 684.760 0.000 685.160 0.400 ;
    END
  END Tile_X2Y0_FrameStrobe[14]
  PIN Tile_X2Y0_FrameStrobe[15]
    DIRECTION INPUT ;
    USE SIGNAL ;
    ANTENNAGATEAREA 0.180700 ;
    PORT
      LAYER Metal2 ;
        RECT 685.720 0.000 686.120 0.400 ;
    END
  END Tile_X2Y0_FrameStrobe[15]
  PIN Tile_X2Y0_FrameStrobe[16]
    DIRECTION INPUT ;
    USE SIGNAL ;
    ANTENNAGATEAREA 0.180700 ;
    PORT
      LAYER Metal2 ;
        RECT 686.680 0.000 687.080 0.400 ;
    END
  END Tile_X2Y0_FrameStrobe[16]
  PIN Tile_X2Y0_FrameStrobe[17]
    DIRECTION INPUT ;
    USE SIGNAL ;
    ANTENNAGATEAREA 0.180700 ;
    PORT
      LAYER Metal2 ;
        RECT 687.640 0.000 688.040 0.400 ;
    END
  END Tile_X2Y0_FrameStrobe[17]
  PIN Tile_X2Y0_FrameStrobe[18]
    DIRECTION INPUT ;
    USE SIGNAL ;
    ANTENNAGATEAREA 0.180700 ;
    PORT
      LAYER Metal2 ;
        RECT 688.600 0.000 689.000 0.400 ;
    END
  END Tile_X2Y0_FrameStrobe[18]
  PIN Tile_X2Y0_FrameStrobe[19]
    DIRECTION INPUT ;
    USE SIGNAL ;
    ANTENNAGATEAREA 0.180700 ;
    PORT
      LAYER Metal2 ;
        RECT 689.560 0.000 689.960 0.400 ;
    END
  END Tile_X2Y0_FrameStrobe[19]
  PIN Tile_X2Y0_FrameStrobe[1]
    DIRECTION INPUT ;
    USE SIGNAL ;
    ANTENNAGATEAREA 11.745500 ;
    PORT
      LAYER Metal2 ;
        RECT 672.280 0.000 672.680 0.400 ;
    END
  END Tile_X2Y0_FrameStrobe[1]
  PIN Tile_X2Y0_FrameStrobe[2]
    DIRECTION INPUT ;
    USE SIGNAL ;
    ANTENNAGATEAREA 11.745500 ;
    PORT
      LAYER Metal2 ;
        RECT 673.240 0.000 673.640 0.400 ;
    END
  END Tile_X2Y0_FrameStrobe[2]
  PIN Tile_X2Y0_FrameStrobe[3]
    DIRECTION INPUT ;
    USE SIGNAL ;
    ANTENNAGATEAREA 0.180700 ;
    PORT
      LAYER Metal2 ;
        RECT 674.200 0.000 674.600 0.400 ;
    END
  END Tile_X2Y0_FrameStrobe[3]
  PIN Tile_X2Y0_FrameStrobe[4]
    DIRECTION INPUT ;
    USE SIGNAL ;
    ANTENNAGATEAREA 0.180700 ;
    PORT
      LAYER Metal2 ;
        RECT 675.160 0.000 675.560 0.400 ;
    END
  END Tile_X2Y0_FrameStrobe[4]
  PIN Tile_X2Y0_FrameStrobe[5]
    DIRECTION INPUT ;
    USE SIGNAL ;
    ANTENNAGATEAREA 0.180700 ;
    PORT
      LAYER Metal2 ;
        RECT 676.120 0.000 676.520 0.400 ;
    END
  END Tile_X2Y0_FrameStrobe[5]
  PIN Tile_X2Y0_FrameStrobe[6]
    DIRECTION INPUT ;
    USE SIGNAL ;
    ANTENNAGATEAREA 0.180700 ;
    PORT
      LAYER Metal2 ;
        RECT 677.080 0.000 677.480 0.400 ;
    END
  END Tile_X2Y0_FrameStrobe[6]
  PIN Tile_X2Y0_FrameStrobe[7]
    DIRECTION INPUT ;
    USE SIGNAL ;
    ANTENNAGATEAREA 0.180700 ;
    PORT
      LAYER Metal2 ;
        RECT 678.040 0.000 678.440 0.400 ;
    END
  END Tile_X2Y0_FrameStrobe[7]
  PIN Tile_X2Y0_FrameStrobe[8]
    DIRECTION INPUT ;
    USE SIGNAL ;
    ANTENNAGATEAREA 0.180700 ;
    PORT
      LAYER Metal2 ;
        RECT 679.000 0.000 679.400 0.400 ;
    END
  END Tile_X2Y0_FrameStrobe[8]
  PIN Tile_X2Y0_FrameStrobe[9]
    DIRECTION INPUT ;
    USE SIGNAL ;
    ANTENNAGATEAREA 0.180700 ;
    PORT
      LAYER Metal2 ;
        RECT 679.960 0.000 680.360 0.400 ;
    END
  END Tile_X2Y0_FrameStrobe[9]
  PIN Tile_X2Y0_FrameStrobe_O[0]
    DIRECTION OUTPUT ;
    USE SIGNAL ;
    ANTENNADIFFAREA 2.724000 ;
    PORT
      LAYER Metal2 ;
        RECT 473.560 78.980 473.960 79.380 ;
    END
  END Tile_X2Y0_FrameStrobe_O[0]
  PIN Tile_X2Y0_FrameStrobe_O[10]
    DIRECTION OUTPUT ;
    USE SIGNAL ;
    ANTENNADIFFAREA 2.724000 ;
    PORT
      LAYER Metal2 ;
        RECT 588.760 78.980 589.160 79.380 ;
    END
  END Tile_X2Y0_FrameStrobe_O[10]
  PIN Tile_X2Y0_FrameStrobe_O[11]
    DIRECTION OUTPUT ;
    USE SIGNAL ;
    ANTENNADIFFAREA 2.724000 ;
    PORT
      LAYER Metal2 ;
        RECT 600.280 78.980 600.680 79.380 ;
    END
  END Tile_X2Y0_FrameStrobe_O[11]
  PIN Tile_X2Y0_FrameStrobe_O[12]
    DIRECTION OUTPUT ;
    USE SIGNAL ;
    ANTENNADIFFAREA 2.724000 ;
    PORT
      LAYER Metal2 ;
        RECT 611.800 78.980 612.200 79.380 ;
    END
  END Tile_X2Y0_FrameStrobe_O[12]
  PIN Tile_X2Y0_FrameStrobe_O[13]
    DIRECTION OUTPUT ;
    USE SIGNAL ;
    ANTENNADIFFAREA 2.724000 ;
    PORT
      LAYER Metal2 ;
        RECT 623.320 78.980 623.720 79.380 ;
    END
  END Tile_X2Y0_FrameStrobe_O[13]
  PIN Tile_X2Y0_FrameStrobe_O[14]
    DIRECTION OUTPUT ;
    USE SIGNAL ;
    ANTENNADIFFAREA 2.724000 ;
    PORT
      LAYER Metal2 ;
        RECT 634.840 78.980 635.240 79.380 ;
    END
  END Tile_X2Y0_FrameStrobe_O[14]
  PIN Tile_X2Y0_FrameStrobe_O[15]
    DIRECTION OUTPUT ;
    USE SIGNAL ;
    ANTENNADIFFAREA 2.724000 ;
    PORT
      LAYER Metal2 ;
        RECT 646.360 78.980 646.760 79.380 ;
    END
  END Tile_X2Y0_FrameStrobe_O[15]
  PIN Tile_X2Y0_FrameStrobe_O[16]
    DIRECTION OUTPUT ;
    USE SIGNAL ;
    ANTENNADIFFAREA 2.724000 ;
    PORT
      LAYER Metal2 ;
        RECT 657.880 78.980 658.280 79.380 ;
    END
  END Tile_X2Y0_FrameStrobe_O[16]
  PIN Tile_X2Y0_FrameStrobe_O[17]
    DIRECTION OUTPUT ;
    USE SIGNAL ;
    ANTENNADIFFAREA 2.724000 ;
    PORT
      LAYER Metal2 ;
        RECT 669.400 78.980 669.800 79.380 ;
    END
  END Tile_X2Y0_FrameStrobe_O[17]
  PIN Tile_X2Y0_FrameStrobe_O[18]
    DIRECTION OUTPUT ;
    USE SIGNAL ;
    ANTENNADIFFAREA 2.724000 ;
    PORT
      LAYER Metal2 ;
        RECT 680.920 78.980 681.320 79.380 ;
    END
  END Tile_X2Y0_FrameStrobe_O[18]
  PIN Tile_X2Y0_FrameStrobe_O[19]
    DIRECTION OUTPUT ;
    USE SIGNAL ;
    ANTENNADIFFAREA 2.724000 ;
    PORT
      LAYER Metal2 ;
        RECT 692.440 78.980 692.840 79.380 ;
    END
  END Tile_X2Y0_FrameStrobe_O[19]
  PIN Tile_X2Y0_FrameStrobe_O[1]
    DIRECTION OUTPUT ;
    USE SIGNAL ;
    ANTENNADIFFAREA 2.724000 ;
    PORT
      LAYER Metal2 ;
        RECT 485.080 78.980 485.480 79.380 ;
    END
  END Tile_X2Y0_FrameStrobe_O[1]
  PIN Tile_X2Y0_FrameStrobe_O[2]
    DIRECTION OUTPUT ;
    USE SIGNAL ;
    ANTENNADIFFAREA 2.724000 ;
    PORT
      LAYER Metal2 ;
        RECT 496.600 78.980 497.000 79.380 ;
    END
  END Tile_X2Y0_FrameStrobe_O[2]
  PIN Tile_X2Y0_FrameStrobe_O[3]
    DIRECTION OUTPUT ;
    USE SIGNAL ;
    ANTENNADIFFAREA 2.724000 ;
    PORT
      LAYER Metal2 ;
        RECT 508.120 78.980 508.520 79.380 ;
    END
  END Tile_X2Y0_FrameStrobe_O[3]
  PIN Tile_X2Y0_FrameStrobe_O[4]
    DIRECTION OUTPUT ;
    USE SIGNAL ;
    ANTENNADIFFAREA 2.724000 ;
    PORT
      LAYER Metal2 ;
        RECT 519.640 78.980 520.040 79.380 ;
    END
  END Tile_X2Y0_FrameStrobe_O[4]
  PIN Tile_X2Y0_FrameStrobe_O[5]
    DIRECTION OUTPUT ;
    USE SIGNAL ;
    ANTENNADIFFAREA 2.724000 ;
    PORT
      LAYER Metal2 ;
        RECT 531.160 78.980 531.560 79.380 ;
    END
  END Tile_X2Y0_FrameStrobe_O[5]
  PIN Tile_X2Y0_FrameStrobe_O[6]
    DIRECTION OUTPUT ;
    USE SIGNAL ;
    ANTENNADIFFAREA 2.724000 ;
    PORT
      LAYER Metal2 ;
        RECT 542.680 78.980 543.080 79.380 ;
    END
  END Tile_X2Y0_FrameStrobe_O[6]
  PIN Tile_X2Y0_FrameStrobe_O[7]
    DIRECTION OUTPUT ;
    USE SIGNAL ;
    ANTENNADIFFAREA 2.724000 ;
    PORT
      LAYER Metal2 ;
        RECT 554.200 78.980 554.600 79.380 ;
    END
  END Tile_X2Y0_FrameStrobe_O[7]
  PIN Tile_X2Y0_FrameStrobe_O[8]
    DIRECTION OUTPUT ;
    USE SIGNAL ;
    ANTENNADIFFAREA 2.724000 ;
    PORT
      LAYER Metal2 ;
        RECT 565.720 78.980 566.120 79.380 ;
    END
  END Tile_X2Y0_FrameStrobe_O[8]
  PIN Tile_X2Y0_FrameStrobe_O[9]
    DIRECTION OUTPUT ;
    USE SIGNAL ;
    ANTENNADIFFAREA 2.724000 ;
    PORT
      LAYER Metal2 ;
        RECT 577.240 78.980 577.640 79.380 ;
    END
  END Tile_X2Y0_FrameStrobe_O[9]
  PIN Tile_X2Y0_N1END[0]
    DIRECTION INPUT ;
    USE SIGNAL ;
    ANTENNAGATEAREA 1.033500 ;
    PORT
      LAYER Metal2 ;
        RECT 467.800 0.000 468.200 0.400 ;
    END
  END Tile_X2Y0_N1END[0]
  PIN Tile_X2Y0_N1END[1]
    DIRECTION INPUT ;
    USE SIGNAL ;
    ANTENNAGATEAREA 1.033500 ;
    PORT
      LAYER Metal2 ;
        RECT 469.720 0.000 470.120 0.400 ;
    END
  END Tile_X2Y0_N1END[1]
  PIN Tile_X2Y0_N1END[2]
    DIRECTION INPUT ;
    USE SIGNAL ;
    ANTENNAGATEAREA 1.033500 ;
    PORT
      LAYER Metal2 ;
        RECT 471.640 0.000 472.040 0.400 ;
    END
  END Tile_X2Y0_N1END[2]
  PIN Tile_X2Y0_N1END[3]
    DIRECTION INPUT ;
    USE SIGNAL ;
    ANTENNAGATEAREA 1.033500 ;
    PORT
      LAYER Metal2 ;
        RECT 473.560 0.000 473.960 0.400 ;
    END
  END Tile_X2Y0_N1END[3]
  PIN Tile_X2Y0_N2END[0]
    DIRECTION INPUT ;
    USE SIGNAL ;
    ANTENNAGATEAREA 0.852800 ;
    PORT
      LAYER Metal2 ;
        RECT 492.760 0.000 493.160 0.400 ;
    END
  END Tile_X2Y0_N2END[0]
  PIN Tile_X2Y0_N2END[1]
    DIRECTION INPUT ;
    USE SIGNAL ;
    ANTENNAGATEAREA 0.852800 ;
    PORT
      LAYER Metal2 ;
        RECT 493.720 0.000 494.120 0.400 ;
    END
  END Tile_X2Y0_N2END[1]
  PIN Tile_X2Y0_N2END[2]
    DIRECTION INPUT ;
    USE SIGNAL ;
    ANTENNAGATEAREA 0.852800 ;
    PORT
      LAYER Metal2 ;
        RECT 494.680 0.000 495.080 0.400 ;
    END
  END Tile_X2Y0_N2END[2]
  PIN Tile_X2Y0_N2END[3]
    DIRECTION INPUT ;
    USE SIGNAL ;
    ANTENNAGATEAREA 0.852800 ;
    PORT
      LAYER Metal2 ;
        RECT 495.640 0.000 496.040 0.400 ;
    END
  END Tile_X2Y0_N2END[3]
  PIN Tile_X2Y0_N2END[4]
    DIRECTION INPUT ;
    USE SIGNAL ;
    ANTENNAGATEAREA 0.852800 ;
    PORT
      LAYER Metal2 ;
        RECT 496.600 0.000 497.000 0.400 ;
    END
  END Tile_X2Y0_N2END[4]
  PIN Tile_X2Y0_N2END[5]
    DIRECTION INPUT ;
    USE SIGNAL ;
    ANTENNAGATEAREA 0.852800 ;
    PORT
      LAYER Metal2 ;
        RECT 497.560 0.000 497.960 0.400 ;
    END
  END Tile_X2Y0_N2END[5]
  PIN Tile_X2Y0_N2END[6]
    DIRECTION INPUT ;
    USE SIGNAL ;
    ANTENNAGATEAREA 0.852800 ;
    PORT
      LAYER Metal2 ;
        RECT 498.520 0.000 498.920 0.400 ;
    END
  END Tile_X2Y0_N2END[6]
  PIN Tile_X2Y0_N2END[7]
    DIRECTION INPUT ;
    USE SIGNAL ;
    ANTENNAGATEAREA 0.852800 ;
    PORT
      LAYER Metal2 ;
        RECT 499.480 0.000 499.880 0.400 ;
    END
  END Tile_X2Y0_N2END[7]
  PIN Tile_X2Y0_N2MID[0]
    DIRECTION INPUT ;
    USE SIGNAL ;
    ANTENNAGATEAREA 1.246700 ;
    PORT
      LAYER Metal2 ;
        RECT 478.360 0.000 478.760 0.400 ;
    END
  END Tile_X2Y0_N2MID[0]
  PIN Tile_X2Y0_N2MID[1]
    DIRECTION INPUT ;
    USE SIGNAL ;
    ANTENNAGATEAREA 1.246700 ;
    PORT
      LAYER Metal2 ;
        RECT 479.320 0.000 479.720 0.400 ;
    END
  END Tile_X2Y0_N2MID[1]
  PIN Tile_X2Y0_N2MID[2]
    DIRECTION INPUT ;
    USE SIGNAL ;
    ANTENNAGATEAREA 1.246700 ;
    PORT
      LAYER Metal2 ;
        RECT 480.280 0.000 480.680 0.400 ;
    END
  END Tile_X2Y0_N2MID[2]
  PIN Tile_X2Y0_N2MID[3]
    DIRECTION INPUT ;
    USE SIGNAL ;
    ANTENNAGATEAREA 1.246700 ;
    PORT
      LAYER Metal2 ;
        RECT 481.240 0.000 481.640 0.400 ;
    END
  END Tile_X2Y0_N2MID[3]
  PIN Tile_X2Y0_N2MID[4]
    DIRECTION INPUT ;
    USE SIGNAL ;
    ANTENNAGATEAREA 1.246700 ;
    PORT
      LAYER Metal2 ;
        RECT 482.200 0.000 482.600 0.400 ;
    END
  END Tile_X2Y0_N2MID[4]
  PIN Tile_X2Y0_N2MID[5]
    DIRECTION INPUT ;
    USE SIGNAL ;
    ANTENNAGATEAREA 1.246700 ;
    PORT
      LAYER Metal2 ;
        RECT 483.160 0.000 483.560 0.400 ;
    END
  END Tile_X2Y0_N2MID[5]
  PIN Tile_X2Y0_N2MID[6]
    DIRECTION INPUT ;
    USE SIGNAL ;
    ANTENNAGATEAREA 1.246700 ;
    PORT
      LAYER Metal2 ;
        RECT 484.120 0.000 484.520 0.400 ;
    END
  END Tile_X2Y0_N2MID[6]
  PIN Tile_X2Y0_N2MID[7]
    DIRECTION INPUT ;
    USE SIGNAL ;
    ANTENNAGATEAREA 1.246700 ;
    PORT
      LAYER Metal2 ;
        RECT 485.080 0.000 485.480 0.400 ;
    END
  END Tile_X2Y0_N2MID[7]
  PIN Tile_X2Y0_N4END[0]
    DIRECTION INPUT ;
    USE SIGNAL ;
    ANTENNAGATEAREA 0.426400 ;
    PORT
      LAYER Metal2 ;
        RECT 511.000 0.000 511.400 0.400 ;
    END
  END Tile_X2Y0_N4END[0]
  PIN Tile_X2Y0_N4END[10]
    DIRECTION INPUT ;
    USE SIGNAL ;
    ANTENNAGATEAREA 0.426400 ;
    PORT
      LAYER Metal2 ;
        RECT 520.600 0.000 521.000 0.400 ;
    END
  END Tile_X2Y0_N4END[10]
  PIN Tile_X2Y0_N4END[11]
    DIRECTION INPUT ;
    USE SIGNAL ;
    ANTENNAGATEAREA 0.426400 ;
    ANTENNADIFFAREA 8.061600 ;
    PORT
      LAYER Metal2 ;
        RECT 521.560 0.000 521.960 0.400 ;
    END
  END Tile_X2Y0_N4END[11]
  PIN Tile_X2Y0_N4END[12]
    DIRECTION INPUT ;
    USE SIGNAL ;
    ANTENNAGATEAREA 0.426400 ;
    PORT
      LAYER Metal2 ;
        RECT 522.520 0.000 522.920 0.400 ;
    END
  END Tile_X2Y0_N4END[12]
  PIN Tile_X2Y0_N4END[13]
    DIRECTION INPUT ;
    USE SIGNAL ;
    ANTENNAGATEAREA 0.426400 ;
    PORT
      LAYER Metal2 ;
        RECT 523.480 0.000 523.880 0.400 ;
    END
  END Tile_X2Y0_N4END[13]
  PIN Tile_X2Y0_N4END[14]
    DIRECTION INPUT ;
    USE SIGNAL ;
    ANTENNAGATEAREA 0.426400 ;
    PORT
      LAYER Metal2 ;
        RECT 524.440 0.000 524.840 0.400 ;
    END
  END Tile_X2Y0_N4END[14]
  PIN Tile_X2Y0_N4END[15]
    DIRECTION INPUT ;
    USE SIGNAL ;
    ANTENNAGATEAREA 0.426400 ;
    PORT
      LAYER Metal2 ;
        RECT 525.400 0.000 525.800 0.400 ;
    END
  END Tile_X2Y0_N4END[15]
  PIN Tile_X2Y0_N4END[1]
    DIRECTION INPUT ;
    USE SIGNAL ;
    ANTENNAGATEAREA 0.426400 ;
    ANTENNADIFFAREA 8.061600 ;
    PORT
      LAYER Metal2 ;
        RECT 511.960 0.000 512.360 0.400 ;
    END
  END Tile_X2Y0_N4END[1]
  PIN Tile_X2Y0_N4END[2]
    DIRECTION INPUT ;
    USE SIGNAL ;
    ANTENNAGATEAREA 0.426400 ;
    PORT
      LAYER Metal2 ;
        RECT 512.920 0.000 513.320 0.400 ;
    END
  END Tile_X2Y0_N4END[2]
  PIN Tile_X2Y0_N4END[3]
    DIRECTION INPUT ;
    USE SIGNAL ;
    ANTENNAGATEAREA 0.426400 ;
    PORT
      LAYER Metal2 ;
        RECT 513.880 0.000 514.280 0.400 ;
    END
  END Tile_X2Y0_N4END[3]
  PIN Tile_X2Y0_N4END[4]
    DIRECTION INPUT ;
    USE SIGNAL ;
    ANTENNAGATEAREA 0.426400 ;
    PORT
      LAYER Metal2 ;
        RECT 514.840 0.000 515.240 0.400 ;
    END
  END Tile_X2Y0_N4END[4]
  PIN Tile_X2Y0_N4END[5]
    DIRECTION INPUT ;
    USE SIGNAL ;
    ANTENNAGATEAREA 0.426400 ;
    ANTENNADIFFAREA 8.061600 ;
    PORT
      LAYER Metal2 ;
        RECT 515.800 0.000 516.200 0.400 ;
    END
  END Tile_X2Y0_N4END[5]
  PIN Tile_X2Y0_N4END[6]
    DIRECTION INPUT ;
    USE SIGNAL ;
    ANTENNAGATEAREA 0.426400 ;
    PORT
      LAYER Metal2 ;
        RECT 516.760 0.000 517.160 0.400 ;
    END
  END Tile_X2Y0_N4END[6]
  PIN Tile_X2Y0_N4END[7]
    DIRECTION INPUT ;
    USE SIGNAL ;
    ANTENNAGATEAREA 0.426400 ;
    PORT
      LAYER Metal2 ;
        RECT 517.720 0.000 518.120 0.400 ;
    END
  END Tile_X2Y0_N4END[7]
  PIN Tile_X2Y0_N4END[8]
    DIRECTION INPUT ;
    USE SIGNAL ;
    ANTENNAGATEAREA 0.426400 ;
    PORT
      LAYER Metal2 ;
        RECT 518.680 0.000 519.080 0.400 ;
    END
  END Tile_X2Y0_N4END[8]
  PIN Tile_X2Y0_N4END[9]
    DIRECTION INPUT ;
    USE SIGNAL ;
    ANTENNAGATEAREA 0.426400 ;
    ANTENNADIFFAREA 8.061600 ;
    PORT
      LAYER Metal2 ;
        RECT 519.640 0.000 520.040 0.400 ;
    END
  END Tile_X2Y0_N4END[9]
  PIN Tile_X2Y0_NN4END[0]
    DIRECTION INPUT ;
    USE SIGNAL ;
    ANTENNAGATEAREA 0.426400 ;
    PORT
      LAYER Metal2 ;
        RECT 540.760 0.000 541.160 0.400 ;
    END
  END Tile_X2Y0_NN4END[0]
  PIN Tile_X2Y0_NN4END[10]
    DIRECTION INPUT ;
    USE SIGNAL ;
    ANTENNAGATEAREA 0.426400 ;
    PORT
      LAYER Metal2 ;
        RECT 550.360 0.000 550.760 0.400 ;
    END
  END Tile_X2Y0_NN4END[10]
  PIN Tile_X2Y0_NN4END[11]
    DIRECTION INPUT ;
    USE SIGNAL ;
    ANTENNAGATEAREA 0.426400 ;
    PORT
      LAYER Metal2 ;
        RECT 551.320 0.000 551.720 0.400 ;
    END
  END Tile_X2Y0_NN4END[11]
  PIN Tile_X2Y0_NN4END[12]
    DIRECTION INPUT ;
    USE SIGNAL ;
    ANTENNAGATEAREA 0.426400 ;
    PORT
      LAYER Metal2 ;
        RECT 552.280 0.000 552.680 0.400 ;
    END
  END Tile_X2Y0_NN4END[12]
  PIN Tile_X2Y0_NN4END[13]
    DIRECTION INPUT ;
    USE SIGNAL ;
    ANTENNAGATEAREA 0.426400 ;
    PORT
      LAYER Metal2 ;
        RECT 553.240 0.000 553.640 0.400 ;
    END
  END Tile_X2Y0_NN4END[13]
  PIN Tile_X2Y0_NN4END[14]
    DIRECTION INPUT ;
    USE SIGNAL ;
    ANTENNAGATEAREA 0.426400 ;
    ANTENNADIFFAREA 8.061600 ;
    PORT
      LAYER Metal2 ;
        RECT 554.200 0.000 554.600 0.400 ;
    END
  END Tile_X2Y0_NN4END[14]
  PIN Tile_X2Y0_NN4END[15]
    DIRECTION INPUT ;
    USE SIGNAL ;
    ANTENNAGATEAREA 0.426400 ;
    PORT
      LAYER Metal2 ;
        RECT 555.160 0.000 555.560 0.400 ;
    END
  END Tile_X2Y0_NN4END[15]
  PIN Tile_X2Y0_NN4END[1]
    DIRECTION INPUT ;
    USE SIGNAL ;
    ANTENNAGATEAREA 0.426400 ;
    PORT
      LAYER Metal2 ;
        RECT 541.720 0.000 542.120 0.400 ;
    END
  END Tile_X2Y0_NN4END[1]
  PIN Tile_X2Y0_NN4END[2]
    DIRECTION INPUT ;
    USE SIGNAL ;
    ANTENNAGATEAREA 0.426400 ;
    PORT
      LAYER Metal2 ;
        RECT 542.680 0.000 543.080 0.400 ;
    END
  END Tile_X2Y0_NN4END[2]
  PIN Tile_X2Y0_NN4END[3]
    DIRECTION INPUT ;
    USE SIGNAL ;
    ANTENNAGATEAREA 0.426400 ;
    PORT
      LAYER Metal2 ;
        RECT 543.640 0.000 544.040 0.400 ;
    END
  END Tile_X2Y0_NN4END[3]
  PIN Tile_X2Y0_NN4END[4]
    DIRECTION INPUT ;
    USE SIGNAL ;
    ANTENNAGATEAREA 0.426400 ;
    PORT
      LAYER Metal2 ;
        RECT 544.600 0.000 545.000 0.400 ;
    END
  END Tile_X2Y0_NN4END[4]
  PIN Tile_X2Y0_NN4END[5]
    DIRECTION INPUT ;
    USE SIGNAL ;
    ANTENNAGATEAREA 0.426400 ;
    PORT
      LAYER Metal2 ;
        RECT 545.560 0.000 545.960 0.400 ;
    END
  END Tile_X2Y0_NN4END[5]
  PIN Tile_X2Y0_NN4END[6]
    DIRECTION INPUT ;
    USE SIGNAL ;
    ANTENNAGATEAREA 0.426400 ;
    PORT
      LAYER Metal2 ;
        RECT 546.520 0.000 546.920 0.400 ;
    END
  END Tile_X2Y0_NN4END[6]
  PIN Tile_X2Y0_NN4END[7]
    DIRECTION INPUT ;
    USE SIGNAL ;
    ANTENNAGATEAREA 0.426400 ;
    PORT
      LAYER Metal2 ;
        RECT 547.480 0.000 547.880 0.400 ;
    END
  END Tile_X2Y0_NN4END[7]
  PIN Tile_X2Y0_NN4END[8]
    DIRECTION INPUT ;
    USE SIGNAL ;
    ANTENNAGATEAREA 0.426400 ;
    PORT
      LAYER Metal2 ;
        RECT 548.440 0.000 548.840 0.400 ;
    END
  END Tile_X2Y0_NN4END[8]
  PIN Tile_X2Y0_NN4END[9]
    DIRECTION INPUT ;
    USE SIGNAL ;
    ANTENNAGATEAREA 0.426400 ;
    PORT
      LAYER Metal2 ;
        RECT 549.400 0.000 549.800 0.400 ;
    END
  END Tile_X2Y0_NN4END[9]
  PIN Tile_X2Y0_S1BEG[0]
    DIRECTION OUTPUT ;
    USE SIGNAL ;
    ANTENNADIFFAREA 2.724000 ;
    PORT
      LAYER Metal2 ;
        RECT 565.720 0.000 566.120 0.400 ;
    END
  END Tile_X2Y0_S1BEG[0]
  PIN Tile_X2Y0_S1BEG[1]
    DIRECTION OUTPUT ;
    USE SIGNAL ;
    ANTENNADIFFAREA 2.724000 ;
    PORT
      LAYER Metal2 ;
        RECT 567.640 0.000 568.040 0.400 ;
    END
  END Tile_X2Y0_S1BEG[1]
  PIN Tile_X2Y0_S1BEG[2]
    DIRECTION OUTPUT ;
    USE SIGNAL ;
    ANTENNADIFFAREA 2.724000 ;
    PORT
      LAYER Metal2 ;
        RECT 569.560 0.000 569.960 0.400 ;
    END
  END Tile_X2Y0_S1BEG[2]
  PIN Tile_X2Y0_S1BEG[3]
    DIRECTION OUTPUT ;
    USE SIGNAL ;
    ANTENNADIFFAREA 2.724000 ;
    PORT
      LAYER Metal2 ;
        RECT 571.480 0.000 571.880 0.400 ;
    END
  END Tile_X2Y0_S1BEG[3]
  PIN Tile_X2Y0_S2BEG[0]
    DIRECTION OUTPUT ;
    USE SIGNAL ;
    ANTENNADIFFAREA 2.724000 ;
    PORT
      LAYER Metal2 ;
        RECT 573.400 0.000 573.800 0.400 ;
    END
  END Tile_X2Y0_S2BEG[0]
  PIN Tile_X2Y0_S2BEG[1]
    DIRECTION OUTPUT ;
    USE SIGNAL ;
    ANTENNADIFFAREA 2.724000 ;
    PORT
      LAYER Metal2 ;
        RECT 575.320 0.000 575.720 0.400 ;
    END
  END Tile_X2Y0_S2BEG[1]
  PIN Tile_X2Y0_S2BEG[2]
    DIRECTION OUTPUT ;
    USE SIGNAL ;
    ANTENNADIFFAREA 2.724000 ;
    PORT
      LAYER Metal2 ;
        RECT 577.240 0.000 577.640 0.400 ;
    END
  END Tile_X2Y0_S2BEG[2]
  PIN Tile_X2Y0_S2BEG[3]
    DIRECTION OUTPUT ;
    USE SIGNAL ;
    ANTENNADIFFAREA 2.724000 ;
    PORT
      LAYER Metal2 ;
        RECT 579.160 0.000 579.560 0.400 ;
    END
  END Tile_X2Y0_S2BEG[3]
  PIN Tile_X2Y0_S2BEG[4]
    DIRECTION OUTPUT ;
    USE SIGNAL ;
    ANTENNADIFFAREA 2.724000 ;
    PORT
      LAYER Metal2 ;
        RECT 581.080 0.000 581.480 0.400 ;
    END
  END Tile_X2Y0_S2BEG[4]
  PIN Tile_X2Y0_S2BEG[5]
    DIRECTION OUTPUT ;
    USE SIGNAL ;
    ANTENNADIFFAREA 2.724000 ;
    PORT
      LAYER Metal2 ;
        RECT 583.000 0.000 583.400 0.400 ;
    END
  END Tile_X2Y0_S2BEG[5]
  PIN Tile_X2Y0_S2BEG[6]
    DIRECTION OUTPUT ;
    USE SIGNAL ;
    ANTENNADIFFAREA 2.724000 ;
    PORT
      LAYER Metal2 ;
        RECT 584.920 0.000 585.320 0.400 ;
    END
  END Tile_X2Y0_S2BEG[6]
  PIN Tile_X2Y0_S2BEG[7]
    DIRECTION OUTPUT ;
    USE SIGNAL ;
    ANTENNADIFFAREA 2.724000 ;
    PORT
      LAYER Metal2 ;
        RECT 586.840 0.000 587.240 0.400 ;
    END
  END Tile_X2Y0_S2BEG[7]
  PIN Tile_X2Y0_S2BEGb[0]
    DIRECTION OUTPUT ;
    USE SIGNAL ;
    ANTENNADIFFAREA 2.724000 ;
    PORT
      LAYER Metal2 ;
        RECT 591.640 0.000 592.040 0.400 ;
    END
  END Tile_X2Y0_S2BEGb[0]
  PIN Tile_X2Y0_S2BEGb[1]
    DIRECTION OUTPUT ;
    USE SIGNAL ;
    ANTENNADIFFAREA 2.724000 ;
    PORT
      LAYER Metal2 ;
        RECT 592.600 0.000 593.000 0.400 ;
    END
  END Tile_X2Y0_S2BEGb[1]
  PIN Tile_X2Y0_S2BEGb[2]
    DIRECTION OUTPUT ;
    USE SIGNAL ;
    ANTENNADIFFAREA 2.724000 ;
    PORT
      LAYER Metal2 ;
        RECT 593.560 0.000 593.960 0.400 ;
    END
  END Tile_X2Y0_S2BEGb[2]
  PIN Tile_X2Y0_S2BEGb[3]
    DIRECTION OUTPUT ;
    USE SIGNAL ;
    ANTENNADIFFAREA 2.724000 ;
    PORT
      LAYER Metal2 ;
        RECT 594.520 0.000 594.920 0.400 ;
    END
  END Tile_X2Y0_S2BEGb[3]
  PIN Tile_X2Y0_S2BEGb[4]
    DIRECTION OUTPUT ;
    USE SIGNAL ;
    ANTENNADIFFAREA 2.724000 ;
    PORT
      LAYER Metal2 ;
        RECT 595.480 0.000 595.880 0.400 ;
    END
  END Tile_X2Y0_S2BEGb[4]
  PIN Tile_X2Y0_S2BEGb[5]
    DIRECTION OUTPUT ;
    USE SIGNAL ;
    ANTENNADIFFAREA 2.724000 ;
    PORT
      LAYER Metal2 ;
        RECT 596.440 0.000 596.840 0.400 ;
    END
  END Tile_X2Y0_S2BEGb[5]
  PIN Tile_X2Y0_S2BEGb[6]
    DIRECTION OUTPUT ;
    USE SIGNAL ;
    ANTENNADIFFAREA 2.724000 ;
    PORT
      LAYER Metal2 ;
        RECT 597.400 0.000 597.800 0.400 ;
    END
  END Tile_X2Y0_S2BEGb[6]
  PIN Tile_X2Y0_S2BEGb[7]
    DIRECTION OUTPUT ;
    USE SIGNAL ;
    ANTENNADIFFAREA 2.724000 ;
    PORT
      LAYER Metal2 ;
        RECT 598.360 0.000 598.760 0.400 ;
    END
  END Tile_X2Y0_S2BEGb[7]
  PIN Tile_X2Y0_S4BEG[0]
    DIRECTION OUTPUT ;
    USE SIGNAL ;
    ANTENNADIFFAREA 2.724000 ;
    PORT
      LAYER Metal2 ;
        RECT 609.880 0.000 610.280 0.400 ;
    END
  END Tile_X2Y0_S4BEG[0]
  PIN Tile_X2Y0_S4BEG[10]
    DIRECTION OUTPUT ;
    USE SIGNAL ;
    ANTENNADIFFAREA 2.724000 ;
    PORT
      LAYER Metal2 ;
        RECT 619.480 0.000 619.880 0.400 ;
    END
  END Tile_X2Y0_S4BEG[10]
  PIN Tile_X2Y0_S4BEG[11]
    DIRECTION OUTPUT ;
    USE SIGNAL ;
    ANTENNADIFFAREA 2.724000 ;
    PORT
      LAYER Metal2 ;
        RECT 620.440 0.000 620.840 0.400 ;
    END
  END Tile_X2Y0_S4BEG[11]
  PIN Tile_X2Y0_S4BEG[12]
    DIRECTION OUTPUT ;
    USE SIGNAL ;
    ANTENNADIFFAREA 2.724000 ;
    PORT
      LAYER Metal2 ;
        RECT 621.400 0.000 621.800 0.400 ;
    END
  END Tile_X2Y0_S4BEG[12]
  PIN Tile_X2Y0_S4BEG[13]
    DIRECTION OUTPUT ;
    USE SIGNAL ;
    ANTENNADIFFAREA 2.724000 ;
    PORT
      LAYER Metal2 ;
        RECT 622.360 0.000 622.760 0.400 ;
    END
  END Tile_X2Y0_S4BEG[13]
  PIN Tile_X2Y0_S4BEG[14]
    DIRECTION OUTPUT ;
    USE SIGNAL ;
    ANTENNADIFFAREA 2.724000 ;
    PORT
      LAYER Metal2 ;
        RECT 623.320 0.000 623.720 0.400 ;
    END
  END Tile_X2Y0_S4BEG[14]
  PIN Tile_X2Y0_S4BEG[15]
    DIRECTION OUTPUT ;
    USE SIGNAL ;
    ANTENNADIFFAREA 2.724000 ;
    PORT
      LAYER Metal2 ;
        RECT 624.280 0.000 624.680 0.400 ;
    END
  END Tile_X2Y0_S4BEG[15]
  PIN Tile_X2Y0_S4BEG[1]
    DIRECTION OUTPUT ;
    USE SIGNAL ;
    ANTENNADIFFAREA 2.724000 ;
    PORT
      LAYER Metal2 ;
        RECT 610.840 0.000 611.240 0.400 ;
    END
  END Tile_X2Y0_S4BEG[1]
  PIN Tile_X2Y0_S4BEG[2]
    DIRECTION OUTPUT ;
    USE SIGNAL ;
    ANTENNADIFFAREA 2.724000 ;
    PORT
      LAYER Metal2 ;
        RECT 611.800 0.000 612.200 0.400 ;
    END
  END Tile_X2Y0_S4BEG[2]
  PIN Tile_X2Y0_S4BEG[3]
    DIRECTION OUTPUT ;
    USE SIGNAL ;
    ANTENNADIFFAREA 2.724000 ;
    PORT
      LAYER Metal2 ;
        RECT 612.760 0.000 613.160 0.400 ;
    END
  END Tile_X2Y0_S4BEG[3]
  PIN Tile_X2Y0_S4BEG[4]
    DIRECTION OUTPUT ;
    USE SIGNAL ;
    ANTENNADIFFAREA 2.724000 ;
    PORT
      LAYER Metal2 ;
        RECT 613.720 0.000 614.120 0.400 ;
    END
  END Tile_X2Y0_S4BEG[4]
  PIN Tile_X2Y0_S4BEG[5]
    DIRECTION OUTPUT ;
    USE SIGNAL ;
    ANTENNADIFFAREA 2.724000 ;
    PORT
      LAYER Metal2 ;
        RECT 614.680 0.000 615.080 0.400 ;
    END
  END Tile_X2Y0_S4BEG[5]
  PIN Tile_X2Y0_S4BEG[6]
    DIRECTION OUTPUT ;
    USE SIGNAL ;
    ANTENNADIFFAREA 2.724000 ;
    PORT
      LAYER Metal2 ;
        RECT 615.640 0.000 616.040 0.400 ;
    END
  END Tile_X2Y0_S4BEG[6]
  PIN Tile_X2Y0_S4BEG[7]
    DIRECTION OUTPUT ;
    USE SIGNAL ;
    ANTENNADIFFAREA 2.724000 ;
    PORT
      LAYER Metal2 ;
        RECT 616.600 0.000 617.000 0.400 ;
    END
  END Tile_X2Y0_S4BEG[7]
  PIN Tile_X2Y0_S4BEG[8]
    DIRECTION OUTPUT ;
    USE SIGNAL ;
    ANTENNADIFFAREA 2.724000 ;
    PORT
      LAYER Metal2 ;
        RECT 617.560 0.000 617.960 0.400 ;
    END
  END Tile_X2Y0_S4BEG[8]
  PIN Tile_X2Y0_S4BEG[9]
    DIRECTION OUTPUT ;
    USE SIGNAL ;
    ANTENNADIFFAREA 2.724000 ;
    PORT
      LAYER Metal2 ;
        RECT 618.520 0.000 618.920 0.400 ;
    END
  END Tile_X2Y0_S4BEG[9]
  PIN Tile_X2Y0_SS4BEG[0]
    DIRECTION OUTPUT ;
    USE SIGNAL ;
    ANTENNADIFFAREA 2.724000 ;
    PORT
      LAYER Metal2 ;
        RECT 639.640 0.000 640.040 0.400 ;
    END
  END Tile_X2Y0_SS4BEG[0]
  PIN Tile_X2Y0_SS4BEG[10]
    DIRECTION OUTPUT ;
    USE SIGNAL ;
    ANTENNADIFFAREA 2.724000 ;
    PORT
      LAYER Metal2 ;
        RECT 649.240 0.000 649.640 0.400 ;
    END
  END Tile_X2Y0_SS4BEG[10]
  PIN Tile_X2Y0_SS4BEG[11]
    DIRECTION OUTPUT ;
    USE SIGNAL ;
    ANTENNADIFFAREA 2.724000 ;
    PORT
      LAYER Metal2 ;
        RECT 650.200 0.000 650.600 0.400 ;
    END
  END Tile_X2Y0_SS4BEG[11]
  PIN Tile_X2Y0_SS4BEG[12]
    DIRECTION OUTPUT ;
    USE SIGNAL ;
    ANTENNADIFFAREA 2.724000 ;
    PORT
      LAYER Metal2 ;
        RECT 651.160 0.000 651.560 0.400 ;
    END
  END Tile_X2Y0_SS4BEG[12]
  PIN Tile_X2Y0_SS4BEG[13]
    DIRECTION OUTPUT ;
    USE SIGNAL ;
    ANTENNADIFFAREA 2.724000 ;
    PORT
      LAYER Metal2 ;
        RECT 652.120 0.000 652.520 0.400 ;
    END
  END Tile_X2Y0_SS4BEG[13]
  PIN Tile_X2Y0_SS4BEG[14]
    DIRECTION OUTPUT ;
    USE SIGNAL ;
    ANTENNADIFFAREA 2.724000 ;
    PORT
      LAYER Metal2 ;
        RECT 653.080 0.000 653.480 0.400 ;
    END
  END Tile_X2Y0_SS4BEG[14]
  PIN Tile_X2Y0_SS4BEG[15]
    DIRECTION OUTPUT ;
    USE SIGNAL ;
    ANTENNADIFFAREA 2.724000 ;
    PORT
      LAYER Metal2 ;
        RECT 654.040 0.000 654.440 0.400 ;
    END
  END Tile_X2Y0_SS4BEG[15]
  PIN Tile_X2Y0_SS4BEG[1]
    DIRECTION OUTPUT ;
    USE SIGNAL ;
    ANTENNADIFFAREA 2.724000 ;
    PORT
      LAYER Metal2 ;
        RECT 640.600 0.000 641.000 0.400 ;
    END
  END Tile_X2Y0_SS4BEG[1]
  PIN Tile_X2Y0_SS4BEG[2]
    DIRECTION OUTPUT ;
    USE SIGNAL ;
    ANTENNADIFFAREA 2.724000 ;
    PORT
      LAYER Metal2 ;
        RECT 641.560 0.000 641.960 0.400 ;
    END
  END Tile_X2Y0_SS4BEG[2]
  PIN Tile_X2Y0_SS4BEG[3]
    DIRECTION OUTPUT ;
    USE SIGNAL ;
    ANTENNADIFFAREA 2.724000 ;
    PORT
      LAYER Metal2 ;
        RECT 642.520 0.000 642.920 0.400 ;
    END
  END Tile_X2Y0_SS4BEG[3]
  PIN Tile_X2Y0_SS4BEG[4]
    DIRECTION OUTPUT ;
    USE SIGNAL ;
    ANTENNADIFFAREA 2.724000 ;
    PORT
      LAYER Metal2 ;
        RECT 643.480 0.000 643.880 0.400 ;
    END
  END Tile_X2Y0_SS4BEG[4]
  PIN Tile_X2Y0_SS4BEG[5]
    DIRECTION OUTPUT ;
    USE SIGNAL ;
    ANTENNADIFFAREA 2.724000 ;
    PORT
      LAYER Metal2 ;
        RECT 644.440 0.000 644.840 0.400 ;
    END
  END Tile_X2Y0_SS4BEG[5]
  PIN Tile_X2Y0_SS4BEG[6]
    DIRECTION OUTPUT ;
    USE SIGNAL ;
    ANTENNADIFFAREA 2.724000 ;
    PORT
      LAYER Metal2 ;
        RECT 645.400 0.000 645.800 0.400 ;
    END
  END Tile_X2Y0_SS4BEG[6]
  PIN Tile_X2Y0_SS4BEG[7]
    DIRECTION OUTPUT ;
    USE SIGNAL ;
    ANTENNADIFFAREA 2.724000 ;
    PORT
      LAYER Metal2 ;
        RECT 646.360 0.000 646.760 0.400 ;
    END
  END Tile_X2Y0_SS4BEG[7]
  PIN Tile_X2Y0_SS4BEG[8]
    DIRECTION OUTPUT ;
    USE SIGNAL ;
    ANTENNADIFFAREA 2.724000 ;
    PORT
      LAYER Metal2 ;
        RECT 647.320 0.000 647.720 0.400 ;
    END
  END Tile_X2Y0_SS4BEG[8]
  PIN Tile_X2Y0_SS4BEG[9]
    DIRECTION OUTPUT ;
    USE SIGNAL ;
    ANTENNADIFFAREA 2.724000 ;
    PORT
      LAYER Metal2 ;
        RECT 648.280 0.000 648.680 0.400 ;
    END
  END Tile_X2Y0_SS4BEG[9]
  PIN Tile_X3Y0_Ci
    DIRECTION INPUT ;
    USE SIGNAL ;
    PORT
      LAYER Metal2 ;
        RECT 797.080 0.000 797.480 0.400 ;
    END
  END Tile_X3Y0_Ci
  PIN Tile_X3Y0_FrameStrobe[0]
    DIRECTION INPUT ;
    USE SIGNAL ;
    ANTENNAGATEAREA 11.745500 ;
    PORT
      LAYER Metal2 ;
        RECT 904.600 0.000 905.000 0.400 ;
    END
  END Tile_X3Y0_FrameStrobe[0]
  PIN Tile_X3Y0_FrameStrobe[10]
    DIRECTION INPUT ;
    USE SIGNAL ;
    ANTENNAGATEAREA 0.180700 ;
    PORT
      LAYER Metal2 ;
        RECT 914.200 0.000 914.600 0.400 ;
    END
  END Tile_X3Y0_FrameStrobe[10]
  PIN Tile_X3Y0_FrameStrobe[11]
    DIRECTION INPUT ;
    USE SIGNAL ;
    ANTENNAGATEAREA 0.180700 ;
    PORT
      LAYER Metal2 ;
        RECT 915.160 0.000 915.560 0.400 ;
    END
  END Tile_X3Y0_FrameStrobe[11]
  PIN Tile_X3Y0_FrameStrobe[12]
    DIRECTION INPUT ;
    USE SIGNAL ;
    ANTENNAGATEAREA 0.180700 ;
    PORT
      LAYER Metal2 ;
        RECT 916.120 0.000 916.520 0.400 ;
    END
  END Tile_X3Y0_FrameStrobe[12]
  PIN Tile_X3Y0_FrameStrobe[13]
    DIRECTION INPUT ;
    USE SIGNAL ;
    ANTENNAGATEAREA 0.180700 ;
    PORT
      LAYER Metal2 ;
        RECT 917.080 0.000 917.480 0.400 ;
    END
  END Tile_X3Y0_FrameStrobe[13]
  PIN Tile_X3Y0_FrameStrobe[14]
    DIRECTION INPUT ;
    USE SIGNAL ;
    ANTENNAGATEAREA 0.180700 ;
    PORT
      LAYER Metal2 ;
        RECT 918.040 0.000 918.440 0.400 ;
    END
  END Tile_X3Y0_FrameStrobe[14]
  PIN Tile_X3Y0_FrameStrobe[15]
    DIRECTION INPUT ;
    USE SIGNAL ;
    ANTENNAGATEAREA 0.180700 ;
    PORT
      LAYER Metal2 ;
        RECT 919.000 0.000 919.400 0.400 ;
    END
  END Tile_X3Y0_FrameStrobe[15]
  PIN Tile_X3Y0_FrameStrobe[16]
    DIRECTION INPUT ;
    USE SIGNAL ;
    ANTENNAGATEAREA 0.180700 ;
    PORT
      LAYER Metal2 ;
        RECT 919.960 0.000 920.360 0.400 ;
    END
  END Tile_X3Y0_FrameStrobe[16]
  PIN Tile_X3Y0_FrameStrobe[17]
    DIRECTION INPUT ;
    USE SIGNAL ;
    ANTENNAGATEAREA 0.180700 ;
    PORT
      LAYER Metal2 ;
        RECT 920.920 0.000 921.320 0.400 ;
    END
  END Tile_X3Y0_FrameStrobe[17]
  PIN Tile_X3Y0_FrameStrobe[18]
    DIRECTION INPUT ;
    USE SIGNAL ;
    ANTENNAGATEAREA 0.180700 ;
    PORT
      LAYER Metal2 ;
        RECT 921.880 0.000 922.280 0.400 ;
    END
  END Tile_X3Y0_FrameStrobe[18]
  PIN Tile_X3Y0_FrameStrobe[19]
    DIRECTION INPUT ;
    USE SIGNAL ;
    ANTENNAGATEAREA 0.180700 ;
    PORT
      LAYER Metal2 ;
        RECT 922.840 0.000 923.240 0.400 ;
    END
  END Tile_X3Y0_FrameStrobe[19]
  PIN Tile_X3Y0_FrameStrobe[1]
    DIRECTION INPUT ;
    USE SIGNAL ;
    ANTENNAGATEAREA 11.745500 ;
    PORT
      LAYER Metal2 ;
        RECT 905.560 0.000 905.960 0.400 ;
    END
  END Tile_X3Y0_FrameStrobe[1]
  PIN Tile_X3Y0_FrameStrobe[2]
    DIRECTION INPUT ;
    USE SIGNAL ;
    ANTENNAGATEAREA 11.745500 ;
    PORT
      LAYER Metal2 ;
        RECT 906.520 0.000 906.920 0.400 ;
    END
  END Tile_X3Y0_FrameStrobe[2]
  PIN Tile_X3Y0_FrameStrobe[3]
    DIRECTION INPUT ;
    USE SIGNAL ;
    ANTENNAGATEAREA 0.180700 ;
    PORT
      LAYER Metal2 ;
        RECT 907.480 0.000 907.880 0.400 ;
    END
  END Tile_X3Y0_FrameStrobe[3]
  PIN Tile_X3Y0_FrameStrobe[4]
    DIRECTION INPUT ;
    USE SIGNAL ;
    ANTENNAGATEAREA 0.180700 ;
    PORT
      LAYER Metal2 ;
        RECT 908.440 0.000 908.840 0.400 ;
    END
  END Tile_X3Y0_FrameStrobe[4]
  PIN Tile_X3Y0_FrameStrobe[5]
    DIRECTION INPUT ;
    USE SIGNAL ;
    ANTENNAGATEAREA 0.180700 ;
    PORT
      LAYER Metal2 ;
        RECT 909.400 0.000 909.800 0.400 ;
    END
  END Tile_X3Y0_FrameStrobe[5]
  PIN Tile_X3Y0_FrameStrobe[6]
    DIRECTION INPUT ;
    USE SIGNAL ;
    ANTENNAGATEAREA 0.180700 ;
    PORT
      LAYER Metal2 ;
        RECT 910.360 0.000 910.760 0.400 ;
    END
  END Tile_X3Y0_FrameStrobe[6]
  PIN Tile_X3Y0_FrameStrobe[7]
    DIRECTION INPUT ;
    USE SIGNAL ;
    ANTENNAGATEAREA 0.180700 ;
    PORT
      LAYER Metal2 ;
        RECT 911.320 0.000 911.720 0.400 ;
    END
  END Tile_X3Y0_FrameStrobe[7]
  PIN Tile_X3Y0_FrameStrobe[8]
    DIRECTION INPUT ;
    USE SIGNAL ;
    ANTENNAGATEAREA 0.180700 ;
    PORT
      LAYER Metal2 ;
        RECT 912.280 0.000 912.680 0.400 ;
    END
  END Tile_X3Y0_FrameStrobe[8]
  PIN Tile_X3Y0_FrameStrobe[9]
    DIRECTION INPUT ;
    USE SIGNAL ;
    ANTENNAGATEAREA 0.180700 ;
    PORT
      LAYER Metal2 ;
        RECT 913.240 0.000 913.640 0.400 ;
    END
  END Tile_X3Y0_FrameStrobe[9]
  PIN Tile_X3Y0_FrameStrobe_O[0]
    DIRECTION OUTPUT ;
    USE SIGNAL ;
    ANTENNADIFFAREA 2.724000 ;
    PORT
      LAYER Metal2 ;
        RECT 706.840 78.980 707.240 79.380 ;
    END
  END Tile_X3Y0_FrameStrobe_O[0]
  PIN Tile_X3Y0_FrameStrobe_O[10]
    DIRECTION OUTPUT ;
    USE SIGNAL ;
    ANTENNADIFFAREA 2.724000 ;
    PORT
      LAYER Metal2 ;
        RECT 822.040 78.980 822.440 79.380 ;
    END
  END Tile_X3Y0_FrameStrobe_O[10]
  PIN Tile_X3Y0_FrameStrobe_O[11]
    DIRECTION OUTPUT ;
    USE SIGNAL ;
    ANTENNADIFFAREA 2.724000 ;
    PORT
      LAYER Metal2 ;
        RECT 833.560 78.980 833.960 79.380 ;
    END
  END Tile_X3Y0_FrameStrobe_O[11]
  PIN Tile_X3Y0_FrameStrobe_O[12]
    DIRECTION OUTPUT ;
    USE SIGNAL ;
    ANTENNADIFFAREA 2.724000 ;
    PORT
      LAYER Metal2 ;
        RECT 845.080 78.980 845.480 79.380 ;
    END
  END Tile_X3Y0_FrameStrobe_O[12]
  PIN Tile_X3Y0_FrameStrobe_O[13]
    DIRECTION OUTPUT ;
    USE SIGNAL ;
    ANTENNADIFFAREA 2.724000 ;
    PORT
      LAYER Metal2 ;
        RECT 856.600 78.980 857.000 79.380 ;
    END
  END Tile_X3Y0_FrameStrobe_O[13]
  PIN Tile_X3Y0_FrameStrobe_O[14]
    DIRECTION OUTPUT ;
    USE SIGNAL ;
    ANTENNADIFFAREA 2.724000 ;
    PORT
      LAYER Metal2 ;
        RECT 868.120 78.980 868.520 79.380 ;
    END
  END Tile_X3Y0_FrameStrobe_O[14]
  PIN Tile_X3Y0_FrameStrobe_O[15]
    DIRECTION OUTPUT ;
    USE SIGNAL ;
    ANTENNADIFFAREA 2.724000 ;
    PORT
      LAYER Metal2 ;
        RECT 879.640 78.980 880.040 79.380 ;
    END
  END Tile_X3Y0_FrameStrobe_O[15]
  PIN Tile_X3Y0_FrameStrobe_O[16]
    DIRECTION OUTPUT ;
    USE SIGNAL ;
    ANTENNADIFFAREA 2.724000 ;
    PORT
      LAYER Metal2 ;
        RECT 891.160 78.980 891.560 79.380 ;
    END
  END Tile_X3Y0_FrameStrobe_O[16]
  PIN Tile_X3Y0_FrameStrobe_O[17]
    DIRECTION OUTPUT ;
    USE SIGNAL ;
    ANTENNADIFFAREA 2.724000 ;
    PORT
      LAYER Metal2 ;
        RECT 902.680 78.980 903.080 79.380 ;
    END
  END Tile_X3Y0_FrameStrobe_O[17]
  PIN Tile_X3Y0_FrameStrobe_O[18]
    DIRECTION OUTPUT ;
    USE SIGNAL ;
    ANTENNADIFFAREA 2.724000 ;
    PORT
      LAYER Metal2 ;
        RECT 914.200 78.980 914.600 79.380 ;
    END
  END Tile_X3Y0_FrameStrobe_O[18]
  PIN Tile_X3Y0_FrameStrobe_O[19]
    DIRECTION OUTPUT ;
    USE SIGNAL ;
    ANTENNADIFFAREA 2.724000 ;
    PORT
      LAYER Metal2 ;
        RECT 925.720 78.980 926.120 79.380 ;
    END
  END Tile_X3Y0_FrameStrobe_O[19]
  PIN Tile_X3Y0_FrameStrobe_O[1]
    DIRECTION OUTPUT ;
    USE SIGNAL ;
    ANTENNADIFFAREA 2.724000 ;
    PORT
      LAYER Metal2 ;
        RECT 718.360 78.980 718.760 79.380 ;
    END
  END Tile_X3Y0_FrameStrobe_O[1]
  PIN Tile_X3Y0_FrameStrobe_O[2]
    DIRECTION OUTPUT ;
    USE SIGNAL ;
    ANTENNADIFFAREA 2.724000 ;
    PORT
      LAYER Metal2 ;
        RECT 729.880 78.980 730.280 79.380 ;
    END
  END Tile_X3Y0_FrameStrobe_O[2]
  PIN Tile_X3Y0_FrameStrobe_O[3]
    DIRECTION OUTPUT ;
    USE SIGNAL ;
    ANTENNADIFFAREA 2.724000 ;
    PORT
      LAYER Metal2 ;
        RECT 741.400 78.980 741.800 79.380 ;
    END
  END Tile_X3Y0_FrameStrobe_O[3]
  PIN Tile_X3Y0_FrameStrobe_O[4]
    DIRECTION OUTPUT ;
    USE SIGNAL ;
    ANTENNADIFFAREA 2.724000 ;
    PORT
      LAYER Metal2 ;
        RECT 752.920 78.980 753.320 79.380 ;
    END
  END Tile_X3Y0_FrameStrobe_O[4]
  PIN Tile_X3Y0_FrameStrobe_O[5]
    DIRECTION OUTPUT ;
    USE SIGNAL ;
    ANTENNADIFFAREA 2.724000 ;
    PORT
      LAYER Metal2 ;
        RECT 764.440 78.980 764.840 79.380 ;
    END
  END Tile_X3Y0_FrameStrobe_O[5]
  PIN Tile_X3Y0_FrameStrobe_O[6]
    DIRECTION OUTPUT ;
    USE SIGNAL ;
    ANTENNADIFFAREA 2.724000 ;
    PORT
      LAYER Metal2 ;
        RECT 775.960 78.980 776.360 79.380 ;
    END
  END Tile_X3Y0_FrameStrobe_O[6]
  PIN Tile_X3Y0_FrameStrobe_O[7]
    DIRECTION OUTPUT ;
    USE SIGNAL ;
    ANTENNADIFFAREA 2.724000 ;
    PORT
      LAYER Metal2 ;
        RECT 787.480 78.980 787.880 79.380 ;
    END
  END Tile_X3Y0_FrameStrobe_O[7]
  PIN Tile_X3Y0_FrameStrobe_O[8]
    DIRECTION OUTPUT ;
    USE SIGNAL ;
    ANTENNADIFFAREA 2.724000 ;
    PORT
      LAYER Metal2 ;
        RECT 799.000 78.980 799.400 79.380 ;
    END
  END Tile_X3Y0_FrameStrobe_O[8]
  PIN Tile_X3Y0_FrameStrobe_O[9]
    DIRECTION OUTPUT ;
    USE SIGNAL ;
    ANTENNADIFFAREA 2.724000 ;
    PORT
      LAYER Metal2 ;
        RECT 810.520 78.980 810.920 79.380 ;
    END
  END Tile_X3Y0_FrameStrobe_O[9]
  PIN Tile_X3Y0_N1END[0]
    DIRECTION INPUT ;
    USE SIGNAL ;
    ANTENNAGATEAREA 1.033500 ;
    PORT
      LAYER Metal2 ;
        RECT 701.080 0.000 701.480 0.400 ;
    END
  END Tile_X3Y0_N1END[0]
  PIN Tile_X3Y0_N1END[1]
    DIRECTION INPUT ;
    USE SIGNAL ;
    ANTENNAGATEAREA 1.033500 ;
    PORT
      LAYER Metal2 ;
        RECT 703.000 0.000 703.400 0.400 ;
    END
  END Tile_X3Y0_N1END[1]
  PIN Tile_X3Y0_N1END[2]
    DIRECTION INPUT ;
    USE SIGNAL ;
    ANTENNAGATEAREA 1.033500 ;
    PORT
      LAYER Metal2 ;
        RECT 704.920 0.000 705.320 0.400 ;
    END
  END Tile_X3Y0_N1END[2]
  PIN Tile_X3Y0_N1END[3]
    DIRECTION INPUT ;
    USE SIGNAL ;
    ANTENNAGATEAREA 1.033500 ;
    PORT
      LAYER Metal2 ;
        RECT 706.840 0.000 707.240 0.400 ;
    END
  END Tile_X3Y0_N1END[3]
  PIN Tile_X3Y0_N2END[0]
    DIRECTION INPUT ;
    USE SIGNAL ;
    ANTENNAGATEAREA 0.852800 ;
    PORT
      LAYER Metal2 ;
        RECT 726.040 0.000 726.440 0.400 ;
    END
  END Tile_X3Y0_N2END[0]
  PIN Tile_X3Y0_N2END[1]
    DIRECTION INPUT ;
    USE SIGNAL ;
    ANTENNAGATEAREA 0.852800 ;
    PORT
      LAYER Metal2 ;
        RECT 727.000 0.000 727.400 0.400 ;
    END
  END Tile_X3Y0_N2END[1]
  PIN Tile_X3Y0_N2END[2]
    DIRECTION INPUT ;
    USE SIGNAL ;
    ANTENNAGATEAREA 0.852800 ;
    PORT
      LAYER Metal2 ;
        RECT 727.960 0.000 728.360 0.400 ;
    END
  END Tile_X3Y0_N2END[2]
  PIN Tile_X3Y0_N2END[3]
    DIRECTION INPUT ;
    USE SIGNAL ;
    ANTENNAGATEAREA 0.852800 ;
    PORT
      LAYER Metal2 ;
        RECT 728.920 0.000 729.320 0.400 ;
    END
  END Tile_X3Y0_N2END[3]
  PIN Tile_X3Y0_N2END[4]
    DIRECTION INPUT ;
    USE SIGNAL ;
    ANTENNAGATEAREA 0.852800 ;
    PORT
      LAYER Metal2 ;
        RECT 729.880 0.000 730.280 0.400 ;
    END
  END Tile_X3Y0_N2END[4]
  PIN Tile_X3Y0_N2END[5]
    DIRECTION INPUT ;
    USE SIGNAL ;
    ANTENNAGATEAREA 0.852800 ;
    PORT
      LAYER Metal2 ;
        RECT 730.840 0.000 731.240 0.400 ;
    END
  END Tile_X3Y0_N2END[5]
  PIN Tile_X3Y0_N2END[6]
    DIRECTION INPUT ;
    USE SIGNAL ;
    ANTENNAGATEAREA 0.852800 ;
    PORT
      LAYER Metal2 ;
        RECT 731.800 0.000 732.200 0.400 ;
    END
  END Tile_X3Y0_N2END[6]
  PIN Tile_X3Y0_N2END[7]
    DIRECTION INPUT ;
    USE SIGNAL ;
    ANTENNAGATEAREA 0.852800 ;
    PORT
      LAYER Metal2 ;
        RECT 732.760 0.000 733.160 0.400 ;
    END
  END Tile_X3Y0_N2END[7]
  PIN Tile_X3Y0_N2MID[0]
    DIRECTION INPUT ;
    USE SIGNAL ;
    ANTENNAGATEAREA 1.246700 ;
    PORT
      LAYER Metal2 ;
        RECT 711.640 0.000 712.040 0.400 ;
    END
  END Tile_X3Y0_N2MID[0]
  PIN Tile_X3Y0_N2MID[1]
    DIRECTION INPUT ;
    USE SIGNAL ;
    ANTENNAGATEAREA 1.246700 ;
    PORT
      LAYER Metal2 ;
        RECT 712.600 0.000 713.000 0.400 ;
    END
  END Tile_X3Y0_N2MID[1]
  PIN Tile_X3Y0_N2MID[2]
    DIRECTION INPUT ;
    USE SIGNAL ;
    ANTENNAGATEAREA 1.246700 ;
    PORT
      LAYER Metal2 ;
        RECT 713.560 0.000 713.960 0.400 ;
    END
  END Tile_X3Y0_N2MID[2]
  PIN Tile_X3Y0_N2MID[3]
    DIRECTION INPUT ;
    USE SIGNAL ;
    ANTENNAGATEAREA 1.246700 ;
    PORT
      LAYER Metal2 ;
        RECT 714.520 0.000 714.920 0.400 ;
    END
  END Tile_X3Y0_N2MID[3]
  PIN Tile_X3Y0_N2MID[4]
    DIRECTION INPUT ;
    USE SIGNAL ;
    ANTENNAGATEAREA 1.246700 ;
    PORT
      LAYER Metal2 ;
        RECT 715.480 0.000 715.880 0.400 ;
    END
  END Tile_X3Y0_N2MID[4]
  PIN Tile_X3Y0_N2MID[5]
    DIRECTION INPUT ;
    USE SIGNAL ;
    ANTENNAGATEAREA 1.246700 ;
    PORT
      LAYER Metal2 ;
        RECT 716.440 0.000 716.840 0.400 ;
    END
  END Tile_X3Y0_N2MID[5]
  PIN Tile_X3Y0_N2MID[6]
    DIRECTION INPUT ;
    USE SIGNAL ;
    ANTENNAGATEAREA 1.246700 ;
    PORT
      LAYER Metal2 ;
        RECT 717.400 0.000 717.800 0.400 ;
    END
  END Tile_X3Y0_N2MID[6]
  PIN Tile_X3Y0_N2MID[7]
    DIRECTION INPUT ;
    USE SIGNAL ;
    ANTENNAGATEAREA 1.246700 ;
    PORT
      LAYER Metal2 ;
        RECT 718.360 0.000 718.760 0.400 ;
    END
  END Tile_X3Y0_N2MID[7]
  PIN Tile_X3Y0_N4END[0]
    DIRECTION INPUT ;
    USE SIGNAL ;
    ANTENNAGATEAREA 0.426400 ;
    PORT
      LAYER Metal2 ;
        RECT 744.280 0.000 744.680 0.400 ;
    END
  END Tile_X3Y0_N4END[0]
  PIN Tile_X3Y0_N4END[10]
    DIRECTION INPUT ;
    USE SIGNAL ;
    ANTENNAGATEAREA 0.426400 ;
    PORT
      LAYER Metal2 ;
        RECT 753.880 0.000 754.280 0.400 ;
    END
  END Tile_X3Y0_N4END[10]
  PIN Tile_X3Y0_N4END[11]
    DIRECTION INPUT ;
    USE SIGNAL ;
    ANTENNAGATEAREA 0.426400 ;
    PORT
      LAYER Metal2 ;
        RECT 754.840 0.000 755.240 0.400 ;
    END
  END Tile_X3Y0_N4END[11]
  PIN Tile_X3Y0_N4END[12]
    DIRECTION INPUT ;
    USE SIGNAL ;
    ANTENNAGATEAREA 0.426400 ;
    PORT
      LAYER Metal2 ;
        RECT 755.800 0.000 756.200 0.400 ;
    END
  END Tile_X3Y0_N4END[12]
  PIN Tile_X3Y0_N4END[13]
    DIRECTION INPUT ;
    USE SIGNAL ;
    ANTENNAGATEAREA 0.426400 ;
    PORT
      LAYER Metal2 ;
        RECT 756.760 0.000 757.160 0.400 ;
    END
  END Tile_X3Y0_N4END[13]
  PIN Tile_X3Y0_N4END[14]
    DIRECTION INPUT ;
    USE SIGNAL ;
    ANTENNAGATEAREA 0.426400 ;
    PORT
      LAYER Metal2 ;
        RECT 757.720 0.000 758.120 0.400 ;
    END
  END Tile_X3Y0_N4END[14]
  PIN Tile_X3Y0_N4END[15]
    DIRECTION INPUT ;
    USE SIGNAL ;
    ANTENNAGATEAREA 0.426400 ;
    PORT
      LAYER Metal2 ;
        RECT 758.680 0.000 759.080 0.400 ;
    END
  END Tile_X3Y0_N4END[15]
  PIN Tile_X3Y0_N4END[1]
    DIRECTION INPUT ;
    USE SIGNAL ;
    ANTENNAGATEAREA 0.426400 ;
    PORT
      LAYER Metal2 ;
        RECT 745.240 0.000 745.640 0.400 ;
    END
  END Tile_X3Y0_N4END[1]
  PIN Tile_X3Y0_N4END[2]
    DIRECTION INPUT ;
    USE SIGNAL ;
    ANTENNAGATEAREA 0.426400 ;
    PORT
      LAYER Metal2 ;
        RECT 746.200 0.000 746.600 0.400 ;
    END
  END Tile_X3Y0_N4END[2]
  PIN Tile_X3Y0_N4END[3]
    DIRECTION INPUT ;
    USE SIGNAL ;
    ANTENNAGATEAREA 0.426400 ;
    PORT
      LAYER Metal2 ;
        RECT 747.160 0.000 747.560 0.400 ;
    END
  END Tile_X3Y0_N4END[3]
  PIN Tile_X3Y0_N4END[4]
    DIRECTION INPUT ;
    USE SIGNAL ;
    ANTENNAGATEAREA 0.426400 ;
    PORT
      LAYER Metal2 ;
        RECT 748.120 0.000 748.520 0.400 ;
    END
  END Tile_X3Y0_N4END[4]
  PIN Tile_X3Y0_N4END[5]
    DIRECTION INPUT ;
    USE SIGNAL ;
    ANTENNAGATEAREA 0.426400 ;
    PORT
      LAYER Metal2 ;
        RECT 749.080 0.000 749.480 0.400 ;
    END
  END Tile_X3Y0_N4END[5]
  PIN Tile_X3Y0_N4END[6]
    DIRECTION INPUT ;
    USE SIGNAL ;
    ANTENNAGATEAREA 0.426400 ;
    PORT
      LAYER Metal2 ;
        RECT 750.040 0.000 750.440 0.400 ;
    END
  END Tile_X3Y0_N4END[6]
  PIN Tile_X3Y0_N4END[7]
    DIRECTION INPUT ;
    USE SIGNAL ;
    ANTENNAGATEAREA 0.426400 ;
    ANTENNADIFFAREA 8.061600 ;
    PORT
      LAYER Metal2 ;
        RECT 751.000 0.000 751.400 0.400 ;
    END
  END Tile_X3Y0_N4END[7]
  PIN Tile_X3Y0_N4END[8]
    DIRECTION INPUT ;
    USE SIGNAL ;
    ANTENNAGATEAREA 0.426400 ;
    PORT
      LAYER Metal2 ;
        RECT 751.960 0.000 752.360 0.400 ;
    END
  END Tile_X3Y0_N4END[8]
  PIN Tile_X3Y0_N4END[9]
    DIRECTION INPUT ;
    USE SIGNAL ;
    ANTENNAGATEAREA 0.426400 ;
    PORT
      LAYER Metal2 ;
        RECT 752.920 0.000 753.320 0.400 ;
    END
  END Tile_X3Y0_N4END[9]
  PIN Tile_X3Y0_NN4END[0]
    DIRECTION INPUT ;
    USE SIGNAL ;
    ANTENNAGATEAREA 0.426400 ;
    PORT
      LAYER Metal2 ;
        RECT 774.040 0.000 774.440 0.400 ;
    END
  END Tile_X3Y0_NN4END[0]
  PIN Tile_X3Y0_NN4END[10]
    DIRECTION INPUT ;
    USE SIGNAL ;
    ANTENNAGATEAREA 0.426400 ;
    PORT
      LAYER Metal2 ;
        RECT 783.640 0.000 784.040 0.400 ;
    END
  END Tile_X3Y0_NN4END[10]
  PIN Tile_X3Y0_NN4END[11]
    DIRECTION INPUT ;
    USE SIGNAL ;
    ANTENNAGATEAREA 0.426400 ;
    PORT
      LAYER Metal2 ;
        RECT 784.600 0.000 785.000 0.400 ;
    END
  END Tile_X3Y0_NN4END[11]
  PIN Tile_X3Y0_NN4END[12]
    DIRECTION INPUT ;
    USE SIGNAL ;
    ANTENNAGATEAREA 0.426400 ;
    PORT
      LAYER Metal2 ;
        RECT 785.560 0.000 785.960 0.400 ;
    END
  END Tile_X3Y0_NN4END[12]
  PIN Tile_X3Y0_NN4END[13]
    DIRECTION INPUT ;
    USE SIGNAL ;
    ANTENNAGATEAREA 0.426400 ;
    PORT
      LAYER Metal2 ;
        RECT 786.520 0.000 786.920 0.400 ;
    END
  END Tile_X3Y0_NN4END[13]
  PIN Tile_X3Y0_NN4END[14]
    DIRECTION INPUT ;
    USE SIGNAL ;
    ANTENNAGATEAREA 0.426400 ;
    PORT
      LAYER Metal2 ;
        RECT 787.480 0.000 787.880 0.400 ;
    END
  END Tile_X3Y0_NN4END[14]
  PIN Tile_X3Y0_NN4END[15]
    DIRECTION INPUT ;
    USE SIGNAL ;
    ANTENNAGATEAREA 0.426400 ;
    PORT
      LAYER Metal2 ;
        RECT 788.440 0.000 788.840 0.400 ;
    END
  END Tile_X3Y0_NN4END[15]
  PIN Tile_X3Y0_NN4END[1]
    DIRECTION INPUT ;
    USE SIGNAL ;
    ANTENNAGATEAREA 0.426400 ;
    PORT
      LAYER Metal2 ;
        RECT 775.000 0.000 775.400 0.400 ;
    END
  END Tile_X3Y0_NN4END[1]
  PIN Tile_X3Y0_NN4END[2]
    DIRECTION INPUT ;
    USE SIGNAL ;
    ANTENNAGATEAREA 0.426400 ;
    PORT
      LAYER Metal2 ;
        RECT 775.960 0.000 776.360 0.400 ;
    END
  END Tile_X3Y0_NN4END[2]
  PIN Tile_X3Y0_NN4END[3]
    DIRECTION INPUT ;
    USE SIGNAL ;
    ANTENNAGATEAREA 0.426400 ;
    PORT
      LAYER Metal2 ;
        RECT 776.920 0.000 777.320 0.400 ;
    END
  END Tile_X3Y0_NN4END[3]
  PIN Tile_X3Y0_NN4END[4]
    DIRECTION INPUT ;
    USE SIGNAL ;
    ANTENNAGATEAREA 0.426400 ;
    PORT
      LAYER Metal2 ;
        RECT 777.880 0.000 778.280 0.400 ;
    END
  END Tile_X3Y0_NN4END[4]
  PIN Tile_X3Y0_NN4END[5]
    DIRECTION INPUT ;
    USE SIGNAL ;
    ANTENNAGATEAREA 0.426400 ;
    PORT
      LAYER Metal2 ;
        RECT 778.840 0.000 779.240 0.400 ;
    END
  END Tile_X3Y0_NN4END[5]
  PIN Tile_X3Y0_NN4END[6]
    DIRECTION INPUT ;
    USE SIGNAL ;
    ANTENNAGATEAREA 0.426400 ;
    PORT
      LAYER Metal2 ;
        RECT 779.800 0.000 780.200 0.400 ;
    END
  END Tile_X3Y0_NN4END[6]
  PIN Tile_X3Y0_NN4END[7]
    DIRECTION INPUT ;
    USE SIGNAL ;
    ANTENNAGATEAREA 0.426400 ;
    PORT
      LAYER Metal2 ;
        RECT 780.760 0.000 781.160 0.400 ;
    END
  END Tile_X3Y0_NN4END[7]
  PIN Tile_X3Y0_NN4END[8]
    DIRECTION INPUT ;
    USE SIGNAL ;
    ANTENNAGATEAREA 0.426400 ;
    PORT
      LAYER Metal2 ;
        RECT 781.720 0.000 782.120 0.400 ;
    END
  END Tile_X3Y0_NN4END[8]
  PIN Tile_X3Y0_NN4END[9]
    DIRECTION INPUT ;
    USE SIGNAL ;
    ANTENNAGATEAREA 0.426400 ;
    PORT
      LAYER Metal2 ;
        RECT 782.680 0.000 783.080 0.400 ;
    END
  END Tile_X3Y0_NN4END[9]
  PIN Tile_X3Y0_S1BEG[0]
    DIRECTION OUTPUT ;
    USE SIGNAL ;
    ANTENNADIFFAREA 2.724000 ;
    PORT
      LAYER Metal2 ;
        RECT 799.000 0.000 799.400 0.400 ;
    END
  END Tile_X3Y0_S1BEG[0]
  PIN Tile_X3Y0_S1BEG[1]
    DIRECTION OUTPUT ;
    USE SIGNAL ;
    ANTENNADIFFAREA 2.724000 ;
    PORT
      LAYER Metal2 ;
        RECT 800.920 0.000 801.320 0.400 ;
    END
  END Tile_X3Y0_S1BEG[1]
  PIN Tile_X3Y0_S1BEG[2]
    DIRECTION OUTPUT ;
    USE SIGNAL ;
    ANTENNADIFFAREA 2.724000 ;
    PORT
      LAYER Metal2 ;
        RECT 802.840 0.000 803.240 0.400 ;
    END
  END Tile_X3Y0_S1BEG[2]
  PIN Tile_X3Y0_S1BEG[3]
    DIRECTION OUTPUT ;
    USE SIGNAL ;
    ANTENNADIFFAREA 2.724000 ;
    PORT
      LAYER Metal2 ;
        RECT 804.760 0.000 805.160 0.400 ;
    END
  END Tile_X3Y0_S1BEG[3]
  PIN Tile_X3Y0_S2BEG[0]
    DIRECTION OUTPUT ;
    USE SIGNAL ;
    ANTENNADIFFAREA 2.724000 ;
    PORT
      LAYER Metal2 ;
        RECT 806.680 0.000 807.080 0.400 ;
    END
  END Tile_X3Y0_S2BEG[0]
  PIN Tile_X3Y0_S2BEG[1]
    DIRECTION OUTPUT ;
    USE SIGNAL ;
    ANTENNADIFFAREA 2.724000 ;
    PORT
      LAYER Metal2 ;
        RECT 808.600 0.000 809.000 0.400 ;
    END
  END Tile_X3Y0_S2BEG[1]
  PIN Tile_X3Y0_S2BEG[2]
    DIRECTION OUTPUT ;
    USE SIGNAL ;
    ANTENNADIFFAREA 2.724000 ;
    PORT
      LAYER Metal2 ;
        RECT 810.520 0.000 810.920 0.400 ;
    END
  END Tile_X3Y0_S2BEG[2]
  PIN Tile_X3Y0_S2BEG[3]
    DIRECTION OUTPUT ;
    USE SIGNAL ;
    ANTENNADIFFAREA 2.724000 ;
    PORT
      LAYER Metal2 ;
        RECT 812.440 0.000 812.840 0.400 ;
    END
  END Tile_X3Y0_S2BEG[3]
  PIN Tile_X3Y0_S2BEG[4]
    DIRECTION OUTPUT ;
    USE SIGNAL ;
    ANTENNADIFFAREA 2.724000 ;
    PORT
      LAYER Metal2 ;
        RECT 814.360 0.000 814.760 0.400 ;
    END
  END Tile_X3Y0_S2BEG[4]
  PIN Tile_X3Y0_S2BEG[5]
    DIRECTION OUTPUT ;
    USE SIGNAL ;
    ANTENNADIFFAREA 2.724000 ;
    PORT
      LAYER Metal2 ;
        RECT 816.280 0.000 816.680 0.400 ;
    END
  END Tile_X3Y0_S2BEG[5]
  PIN Tile_X3Y0_S2BEG[6]
    DIRECTION OUTPUT ;
    USE SIGNAL ;
    ANTENNADIFFAREA 2.724000 ;
    PORT
      LAYER Metal2 ;
        RECT 818.200 0.000 818.600 0.400 ;
    END
  END Tile_X3Y0_S2BEG[6]
  PIN Tile_X3Y0_S2BEG[7]
    DIRECTION OUTPUT ;
    USE SIGNAL ;
    ANTENNADIFFAREA 2.724000 ;
    PORT
      LAYER Metal2 ;
        RECT 820.120 0.000 820.520 0.400 ;
    END
  END Tile_X3Y0_S2BEG[7]
  PIN Tile_X3Y0_S2BEGb[0]
    DIRECTION OUTPUT ;
    USE SIGNAL ;
    ANTENNADIFFAREA 2.724000 ;
    PORT
      LAYER Metal2 ;
        RECT 824.920 0.000 825.320 0.400 ;
    END
  END Tile_X3Y0_S2BEGb[0]
  PIN Tile_X3Y0_S2BEGb[1]
    DIRECTION OUTPUT ;
    USE SIGNAL ;
    ANTENNADIFFAREA 2.724000 ;
    PORT
      LAYER Metal2 ;
        RECT 825.880 0.000 826.280 0.400 ;
    END
  END Tile_X3Y0_S2BEGb[1]
  PIN Tile_X3Y0_S2BEGb[2]
    DIRECTION OUTPUT ;
    USE SIGNAL ;
    ANTENNADIFFAREA 2.724000 ;
    PORT
      LAYER Metal2 ;
        RECT 826.840 0.000 827.240 0.400 ;
    END
  END Tile_X3Y0_S2BEGb[2]
  PIN Tile_X3Y0_S2BEGb[3]
    DIRECTION OUTPUT ;
    USE SIGNAL ;
    ANTENNADIFFAREA 2.724000 ;
    PORT
      LAYER Metal2 ;
        RECT 827.800 0.000 828.200 0.400 ;
    END
  END Tile_X3Y0_S2BEGb[3]
  PIN Tile_X3Y0_S2BEGb[4]
    DIRECTION OUTPUT ;
    USE SIGNAL ;
    ANTENNADIFFAREA 2.724000 ;
    PORT
      LAYER Metal2 ;
        RECT 828.760 0.000 829.160 0.400 ;
    END
  END Tile_X3Y0_S2BEGb[4]
  PIN Tile_X3Y0_S2BEGb[5]
    DIRECTION OUTPUT ;
    USE SIGNAL ;
    ANTENNADIFFAREA 2.724000 ;
    PORT
      LAYER Metal2 ;
        RECT 829.720 0.000 830.120 0.400 ;
    END
  END Tile_X3Y0_S2BEGb[5]
  PIN Tile_X3Y0_S2BEGb[6]
    DIRECTION OUTPUT ;
    USE SIGNAL ;
    ANTENNADIFFAREA 2.724000 ;
    PORT
      LAYER Metal2 ;
        RECT 830.680 0.000 831.080 0.400 ;
    END
  END Tile_X3Y0_S2BEGb[6]
  PIN Tile_X3Y0_S2BEGb[7]
    DIRECTION OUTPUT ;
    USE SIGNAL ;
    ANTENNADIFFAREA 2.724000 ;
    PORT
      LAYER Metal2 ;
        RECT 831.640 0.000 832.040 0.400 ;
    END
  END Tile_X3Y0_S2BEGb[7]
  PIN Tile_X3Y0_S4BEG[0]
    DIRECTION OUTPUT ;
    USE SIGNAL ;
    ANTENNADIFFAREA 2.724000 ;
    PORT
      LAYER Metal2 ;
        RECT 843.160 0.000 843.560 0.400 ;
    END
  END Tile_X3Y0_S4BEG[0]
  PIN Tile_X3Y0_S4BEG[10]
    DIRECTION OUTPUT ;
    USE SIGNAL ;
    ANTENNADIFFAREA 2.724000 ;
    PORT
      LAYER Metal2 ;
        RECT 852.760 0.000 853.160 0.400 ;
    END
  END Tile_X3Y0_S4BEG[10]
  PIN Tile_X3Y0_S4BEG[11]
    DIRECTION OUTPUT ;
    USE SIGNAL ;
    ANTENNADIFFAREA 2.724000 ;
    PORT
      LAYER Metal2 ;
        RECT 853.720 0.000 854.120 0.400 ;
    END
  END Tile_X3Y0_S4BEG[11]
  PIN Tile_X3Y0_S4BEG[12]
    DIRECTION OUTPUT ;
    USE SIGNAL ;
    ANTENNADIFFAREA 2.724000 ;
    PORT
      LAYER Metal2 ;
        RECT 854.680 0.000 855.080 0.400 ;
    END
  END Tile_X3Y0_S4BEG[12]
  PIN Tile_X3Y0_S4BEG[13]
    DIRECTION OUTPUT ;
    USE SIGNAL ;
    ANTENNADIFFAREA 2.724000 ;
    PORT
      LAYER Metal2 ;
        RECT 855.640 0.000 856.040 0.400 ;
    END
  END Tile_X3Y0_S4BEG[13]
  PIN Tile_X3Y0_S4BEG[14]
    DIRECTION OUTPUT ;
    USE SIGNAL ;
    ANTENNADIFFAREA 2.724000 ;
    PORT
      LAYER Metal2 ;
        RECT 856.600 0.000 857.000 0.400 ;
    END
  END Tile_X3Y0_S4BEG[14]
  PIN Tile_X3Y0_S4BEG[15]
    DIRECTION OUTPUT ;
    USE SIGNAL ;
    ANTENNADIFFAREA 2.724000 ;
    PORT
      LAYER Metal2 ;
        RECT 857.560 0.000 857.960 0.400 ;
    END
  END Tile_X3Y0_S4BEG[15]
  PIN Tile_X3Y0_S4BEG[1]
    DIRECTION OUTPUT ;
    USE SIGNAL ;
    ANTENNADIFFAREA 2.724000 ;
    PORT
      LAYER Metal2 ;
        RECT 844.120 0.000 844.520 0.400 ;
    END
  END Tile_X3Y0_S4BEG[1]
  PIN Tile_X3Y0_S4BEG[2]
    DIRECTION OUTPUT ;
    USE SIGNAL ;
    ANTENNADIFFAREA 2.724000 ;
    PORT
      LAYER Metal2 ;
        RECT 845.080 0.000 845.480 0.400 ;
    END
  END Tile_X3Y0_S4BEG[2]
  PIN Tile_X3Y0_S4BEG[3]
    DIRECTION OUTPUT ;
    USE SIGNAL ;
    ANTENNADIFFAREA 2.724000 ;
    PORT
      LAYER Metal2 ;
        RECT 846.040 0.000 846.440 0.400 ;
    END
  END Tile_X3Y0_S4BEG[3]
  PIN Tile_X3Y0_S4BEG[4]
    DIRECTION OUTPUT ;
    USE SIGNAL ;
    ANTENNADIFFAREA 2.724000 ;
    PORT
      LAYER Metal2 ;
        RECT 847.000 0.000 847.400 0.400 ;
    END
  END Tile_X3Y0_S4BEG[4]
  PIN Tile_X3Y0_S4BEG[5]
    DIRECTION OUTPUT ;
    USE SIGNAL ;
    ANTENNADIFFAREA 2.724000 ;
    PORT
      LAYER Metal2 ;
        RECT 847.960 0.000 848.360 0.400 ;
    END
  END Tile_X3Y0_S4BEG[5]
  PIN Tile_X3Y0_S4BEG[6]
    DIRECTION OUTPUT ;
    USE SIGNAL ;
    ANTENNADIFFAREA 2.724000 ;
    PORT
      LAYER Metal2 ;
        RECT 848.920 0.000 849.320 0.400 ;
    END
  END Tile_X3Y0_S4BEG[6]
  PIN Tile_X3Y0_S4BEG[7]
    DIRECTION OUTPUT ;
    USE SIGNAL ;
    ANTENNADIFFAREA 2.724000 ;
    PORT
      LAYER Metal2 ;
        RECT 849.880 0.000 850.280 0.400 ;
    END
  END Tile_X3Y0_S4BEG[7]
  PIN Tile_X3Y0_S4BEG[8]
    DIRECTION OUTPUT ;
    USE SIGNAL ;
    ANTENNADIFFAREA 2.724000 ;
    PORT
      LAYER Metal2 ;
        RECT 850.840 0.000 851.240 0.400 ;
    END
  END Tile_X3Y0_S4BEG[8]
  PIN Tile_X3Y0_S4BEG[9]
    DIRECTION OUTPUT ;
    USE SIGNAL ;
    ANTENNADIFFAREA 2.724000 ;
    PORT
      LAYER Metal2 ;
        RECT 851.800 0.000 852.200 0.400 ;
    END
  END Tile_X3Y0_S4BEG[9]
  PIN Tile_X3Y0_SS4BEG[0]
    DIRECTION OUTPUT ;
    USE SIGNAL ;
    ANTENNADIFFAREA 2.724000 ;
    PORT
      LAYER Metal2 ;
        RECT 872.920 0.000 873.320 0.400 ;
    END
  END Tile_X3Y0_SS4BEG[0]
  PIN Tile_X3Y0_SS4BEG[10]
    DIRECTION OUTPUT ;
    USE SIGNAL ;
    ANTENNADIFFAREA 2.724000 ;
    PORT
      LAYER Metal2 ;
        RECT 882.520 0.000 882.920 0.400 ;
    END
  END Tile_X3Y0_SS4BEG[10]
  PIN Tile_X3Y0_SS4BEG[11]
    DIRECTION OUTPUT ;
    USE SIGNAL ;
    ANTENNADIFFAREA 2.724000 ;
    PORT
      LAYER Metal2 ;
        RECT 883.480 0.000 883.880 0.400 ;
    END
  END Tile_X3Y0_SS4BEG[11]
  PIN Tile_X3Y0_SS4BEG[12]
    DIRECTION OUTPUT ;
    USE SIGNAL ;
    ANTENNADIFFAREA 2.724000 ;
    PORT
      LAYER Metal2 ;
        RECT 884.440 0.000 884.840 0.400 ;
    END
  END Tile_X3Y0_SS4BEG[12]
  PIN Tile_X3Y0_SS4BEG[13]
    DIRECTION OUTPUT ;
    USE SIGNAL ;
    ANTENNADIFFAREA 2.724000 ;
    PORT
      LAYER Metal2 ;
        RECT 885.400 0.000 885.800 0.400 ;
    END
  END Tile_X3Y0_SS4BEG[13]
  PIN Tile_X3Y0_SS4BEG[14]
    DIRECTION OUTPUT ;
    USE SIGNAL ;
    ANTENNADIFFAREA 2.724000 ;
    PORT
      LAYER Metal2 ;
        RECT 886.360 0.000 886.760 0.400 ;
    END
  END Tile_X3Y0_SS4BEG[14]
  PIN Tile_X3Y0_SS4BEG[15]
    DIRECTION OUTPUT ;
    USE SIGNAL ;
    ANTENNADIFFAREA 2.724000 ;
    PORT
      LAYER Metal2 ;
        RECT 887.320 0.000 887.720 0.400 ;
    END
  END Tile_X3Y0_SS4BEG[15]
  PIN Tile_X3Y0_SS4BEG[1]
    DIRECTION OUTPUT ;
    USE SIGNAL ;
    ANTENNADIFFAREA 2.724000 ;
    PORT
      LAYER Metal2 ;
        RECT 873.880 0.000 874.280 0.400 ;
    END
  END Tile_X3Y0_SS4BEG[1]
  PIN Tile_X3Y0_SS4BEG[2]
    DIRECTION OUTPUT ;
    USE SIGNAL ;
    ANTENNADIFFAREA 2.724000 ;
    PORT
      LAYER Metal2 ;
        RECT 874.840 0.000 875.240 0.400 ;
    END
  END Tile_X3Y0_SS4BEG[2]
  PIN Tile_X3Y0_SS4BEG[3]
    DIRECTION OUTPUT ;
    USE SIGNAL ;
    ANTENNADIFFAREA 2.724000 ;
    PORT
      LAYER Metal2 ;
        RECT 875.800 0.000 876.200 0.400 ;
    END
  END Tile_X3Y0_SS4BEG[3]
  PIN Tile_X3Y0_SS4BEG[4]
    DIRECTION OUTPUT ;
    USE SIGNAL ;
    ANTENNADIFFAREA 2.724000 ;
    PORT
      LAYER Metal2 ;
        RECT 876.760 0.000 877.160 0.400 ;
    END
  END Tile_X3Y0_SS4BEG[4]
  PIN Tile_X3Y0_SS4BEG[5]
    DIRECTION OUTPUT ;
    USE SIGNAL ;
    ANTENNADIFFAREA 2.724000 ;
    PORT
      LAYER Metal2 ;
        RECT 877.720 0.000 878.120 0.400 ;
    END
  END Tile_X3Y0_SS4BEG[5]
  PIN Tile_X3Y0_SS4BEG[6]
    DIRECTION OUTPUT ;
    USE SIGNAL ;
    ANTENNADIFFAREA 2.724000 ;
    PORT
      LAYER Metal2 ;
        RECT 878.680 0.000 879.080 0.400 ;
    END
  END Tile_X3Y0_SS4BEG[6]
  PIN Tile_X3Y0_SS4BEG[7]
    DIRECTION OUTPUT ;
    USE SIGNAL ;
    ANTENNADIFFAREA 2.724000 ;
    PORT
      LAYER Metal2 ;
        RECT 879.640 0.000 880.040 0.400 ;
    END
  END Tile_X3Y0_SS4BEG[7]
  PIN Tile_X3Y0_SS4BEG[8]
    DIRECTION OUTPUT ;
    USE SIGNAL ;
    ANTENNADIFFAREA 2.724000 ;
    PORT
      LAYER Metal2 ;
        RECT 880.600 0.000 881.000 0.400 ;
    END
  END Tile_X3Y0_SS4BEG[8]
  PIN Tile_X3Y0_SS4BEG[9]
    DIRECTION OUTPUT ;
    USE SIGNAL ;
    ANTENNADIFFAREA 2.724000 ;
    PORT
      LAYER Metal2 ;
        RECT 881.560 0.000 881.960 0.400 ;
    END
  END Tile_X3Y0_SS4BEG[9]
  PIN Tile_X4Y0_Ci
    DIRECTION INPUT ;
    USE SIGNAL ;
    PORT
      LAYER Metal2 ;
        RECT 1030.360 0.000 1030.760 0.400 ;
    END
  END Tile_X4Y0_Ci
  PIN Tile_X4Y0_FrameData_O[0]
    DIRECTION OUTPUT ;
    USE SIGNAL ;
    ANTENNADIFFAREA 2.724000 ;
    PORT
      LAYER Metal3 ;
        RECT 1166.000 15.340 1166.400 15.740 ;
    END
  END Tile_X4Y0_FrameData_O[0]
  PIN Tile_X4Y0_FrameData_O[10]
    DIRECTION OUTPUT ;
    USE SIGNAL ;
    ANTENNADIFFAREA 2.724000 ;
    PORT
      LAYER Metal3 ;
        RECT 1166.000 32.140 1166.400 32.540 ;
    END
  END Tile_X4Y0_FrameData_O[10]
  PIN Tile_X4Y0_FrameData_O[11]
    DIRECTION OUTPUT ;
    USE SIGNAL ;
    ANTENNADIFFAREA 2.724000 ;
    PORT
      LAYER Metal3 ;
        RECT 1166.000 33.820 1166.400 34.220 ;
    END
  END Tile_X4Y0_FrameData_O[11]
  PIN Tile_X4Y0_FrameData_O[12]
    DIRECTION OUTPUT ;
    USE SIGNAL ;
    ANTENNADIFFAREA 2.724000 ;
    PORT
      LAYER Metal3 ;
        RECT 1166.000 35.500 1166.400 35.900 ;
    END
  END Tile_X4Y0_FrameData_O[12]
  PIN Tile_X4Y0_FrameData_O[13]
    DIRECTION OUTPUT ;
    USE SIGNAL ;
    ANTENNADIFFAREA 2.724000 ;
    PORT
      LAYER Metal3 ;
        RECT 1166.000 37.180 1166.400 37.580 ;
    END
  END Tile_X4Y0_FrameData_O[13]
  PIN Tile_X4Y0_FrameData_O[14]
    DIRECTION OUTPUT ;
    USE SIGNAL ;
    ANTENNADIFFAREA 2.724000 ;
    PORT
      LAYER Metal3 ;
        RECT 1166.000 38.860 1166.400 39.260 ;
    END
  END Tile_X4Y0_FrameData_O[14]
  PIN Tile_X4Y0_FrameData_O[15]
    DIRECTION OUTPUT ;
    USE SIGNAL ;
    ANTENNADIFFAREA 2.724000 ;
    PORT
      LAYER Metal3 ;
        RECT 1166.000 40.540 1166.400 40.940 ;
    END
  END Tile_X4Y0_FrameData_O[15]
  PIN Tile_X4Y0_FrameData_O[16]
    DIRECTION OUTPUT ;
    USE SIGNAL ;
    ANTENNADIFFAREA 2.724000 ;
    PORT
      LAYER Metal3 ;
        RECT 1166.000 42.220 1166.400 42.620 ;
    END
  END Tile_X4Y0_FrameData_O[16]
  PIN Tile_X4Y0_FrameData_O[17]
    DIRECTION OUTPUT ;
    USE SIGNAL ;
    ANTENNADIFFAREA 2.724000 ;
    PORT
      LAYER Metal3 ;
        RECT 1166.000 43.900 1166.400 44.300 ;
    END
  END Tile_X4Y0_FrameData_O[17]
  PIN Tile_X4Y0_FrameData_O[18]
    DIRECTION OUTPUT ;
    USE SIGNAL ;
    ANTENNADIFFAREA 2.724000 ;
    PORT
      LAYER Metal3 ;
        RECT 1166.000 45.580 1166.400 45.980 ;
    END
  END Tile_X4Y0_FrameData_O[18]
  PIN Tile_X4Y0_FrameData_O[19]
    DIRECTION OUTPUT ;
    USE SIGNAL ;
    ANTENNADIFFAREA 2.724000 ;
    PORT
      LAYER Metal3 ;
        RECT 1166.000 47.260 1166.400 47.660 ;
    END
  END Tile_X4Y0_FrameData_O[19]
  PIN Tile_X4Y0_FrameData_O[1]
    DIRECTION OUTPUT ;
    USE SIGNAL ;
    ANTENNADIFFAREA 2.724000 ;
    PORT
      LAYER Metal3 ;
        RECT 1166.000 17.020 1166.400 17.420 ;
    END
  END Tile_X4Y0_FrameData_O[1]
  PIN Tile_X4Y0_FrameData_O[20]
    DIRECTION OUTPUT ;
    USE SIGNAL ;
    ANTENNADIFFAREA 2.724000 ;
    PORT
      LAYER Metal3 ;
        RECT 1166.000 48.940 1166.400 49.340 ;
    END
  END Tile_X4Y0_FrameData_O[20]
  PIN Tile_X4Y0_FrameData_O[21]
    DIRECTION OUTPUT ;
    USE SIGNAL ;
    ANTENNADIFFAREA 2.724000 ;
    PORT
      LAYER Metal3 ;
        RECT 1166.000 50.620 1166.400 51.020 ;
    END
  END Tile_X4Y0_FrameData_O[21]
  PIN Tile_X4Y0_FrameData_O[22]
    DIRECTION OUTPUT ;
    USE SIGNAL ;
    ANTENNADIFFAREA 2.724000 ;
    PORT
      LAYER Metal3 ;
        RECT 1166.000 52.300 1166.400 52.700 ;
    END
  END Tile_X4Y0_FrameData_O[22]
  PIN Tile_X4Y0_FrameData_O[23]
    DIRECTION OUTPUT ;
    USE SIGNAL ;
    ANTENNADIFFAREA 2.724000 ;
    PORT
      LAYER Metal3 ;
        RECT 1166.000 53.980 1166.400 54.380 ;
    END
  END Tile_X4Y0_FrameData_O[23]
  PIN Tile_X4Y0_FrameData_O[24]
    DIRECTION OUTPUT ;
    USE SIGNAL ;
    ANTENNADIFFAREA 2.724000 ;
    PORT
      LAYER Metal3 ;
        RECT 1166.000 55.660 1166.400 56.060 ;
    END
  END Tile_X4Y0_FrameData_O[24]
  PIN Tile_X4Y0_FrameData_O[25]
    DIRECTION OUTPUT ;
    USE SIGNAL ;
    ANTENNADIFFAREA 2.724000 ;
    PORT
      LAYER Metal3 ;
        RECT 1166.000 57.340 1166.400 57.740 ;
    END
  END Tile_X4Y0_FrameData_O[25]
  PIN Tile_X4Y0_FrameData_O[26]
    DIRECTION OUTPUT ;
    USE SIGNAL ;
    ANTENNADIFFAREA 2.724000 ;
    PORT
      LAYER Metal3 ;
        RECT 1166.000 59.020 1166.400 59.420 ;
    END
  END Tile_X4Y0_FrameData_O[26]
  PIN Tile_X4Y0_FrameData_O[27]
    DIRECTION OUTPUT ;
    USE SIGNAL ;
    ANTENNADIFFAREA 2.724000 ;
    PORT
      LAYER Metal3 ;
        RECT 1166.000 60.700 1166.400 61.100 ;
    END
  END Tile_X4Y0_FrameData_O[27]
  PIN Tile_X4Y0_FrameData_O[28]
    DIRECTION OUTPUT ;
    USE SIGNAL ;
    ANTENNADIFFAREA 2.724000 ;
    PORT
      LAYER Metal3 ;
        RECT 1166.000 62.380 1166.400 62.780 ;
    END
  END Tile_X4Y0_FrameData_O[28]
  PIN Tile_X4Y0_FrameData_O[29]
    DIRECTION OUTPUT ;
    USE SIGNAL ;
    ANTENNADIFFAREA 2.724000 ;
    PORT
      LAYER Metal3 ;
        RECT 1166.000 64.060 1166.400 64.460 ;
    END
  END Tile_X4Y0_FrameData_O[29]
  PIN Tile_X4Y0_FrameData_O[2]
    DIRECTION OUTPUT ;
    USE SIGNAL ;
    ANTENNADIFFAREA 2.724000 ;
    PORT
      LAYER Metal3 ;
        RECT 1166.000 18.700 1166.400 19.100 ;
    END
  END Tile_X4Y0_FrameData_O[2]
  PIN Tile_X4Y0_FrameData_O[30]
    DIRECTION OUTPUT ;
    USE SIGNAL ;
    ANTENNADIFFAREA 2.724000 ;
    PORT
      LAYER Metal3 ;
        RECT 1166.000 65.740 1166.400 66.140 ;
    END
  END Tile_X4Y0_FrameData_O[30]
  PIN Tile_X4Y0_FrameData_O[31]
    DIRECTION OUTPUT ;
    USE SIGNAL ;
    ANTENNADIFFAREA 2.724000 ;
    PORT
      LAYER Metal3 ;
        RECT 1166.000 67.420 1166.400 67.820 ;
    END
  END Tile_X4Y0_FrameData_O[31]
  PIN Tile_X4Y0_FrameData_O[3]
    DIRECTION OUTPUT ;
    USE SIGNAL ;
    ANTENNADIFFAREA 2.724000 ;
    PORT
      LAYER Metal3 ;
        RECT 1166.000 20.380 1166.400 20.780 ;
    END
  END Tile_X4Y0_FrameData_O[3]
  PIN Tile_X4Y0_FrameData_O[4]
    DIRECTION OUTPUT ;
    USE SIGNAL ;
    ANTENNADIFFAREA 2.724000 ;
    PORT
      LAYER Metal3 ;
        RECT 1166.000 22.060 1166.400 22.460 ;
    END
  END Tile_X4Y0_FrameData_O[4]
  PIN Tile_X4Y0_FrameData_O[5]
    DIRECTION OUTPUT ;
    USE SIGNAL ;
    ANTENNADIFFAREA 2.724000 ;
    PORT
      LAYER Metal3 ;
        RECT 1166.000 23.740 1166.400 24.140 ;
    END
  END Tile_X4Y0_FrameData_O[5]
  PIN Tile_X4Y0_FrameData_O[6]
    DIRECTION OUTPUT ;
    USE SIGNAL ;
    ANTENNADIFFAREA 2.724000 ;
    PORT
      LAYER Metal3 ;
        RECT 1166.000 25.420 1166.400 25.820 ;
    END
  END Tile_X4Y0_FrameData_O[6]
  PIN Tile_X4Y0_FrameData_O[7]
    DIRECTION OUTPUT ;
    USE SIGNAL ;
    ANTENNADIFFAREA 2.724000 ;
    PORT
      LAYER Metal3 ;
        RECT 1166.000 27.100 1166.400 27.500 ;
    END
  END Tile_X4Y0_FrameData_O[7]
  PIN Tile_X4Y0_FrameData_O[8]
    DIRECTION OUTPUT ;
    USE SIGNAL ;
    ANTENNADIFFAREA 2.724000 ;
    PORT
      LAYER Metal3 ;
        RECT 1166.000 28.780 1166.400 29.180 ;
    END
  END Tile_X4Y0_FrameData_O[8]
  PIN Tile_X4Y0_FrameData_O[9]
    DIRECTION OUTPUT ;
    USE SIGNAL ;
    ANTENNADIFFAREA 2.724000 ;
    PORT
      LAYER Metal3 ;
        RECT 1166.000 30.460 1166.400 30.860 ;
    END
  END Tile_X4Y0_FrameData_O[9]
  PIN Tile_X4Y0_FrameStrobe[0]
    DIRECTION INPUT ;
    USE SIGNAL ;
    ANTENNAGATEAREA 5.240300 ;
    PORT
      LAYER Metal2 ;
        RECT 1137.880 0.000 1138.280 0.400 ;
    END
  END Tile_X4Y0_FrameStrobe[0]
  PIN Tile_X4Y0_FrameStrobe[10]
    DIRECTION INPUT ;
    USE SIGNAL ;
    ANTENNAGATEAREA 0.180700 ;
    PORT
      LAYER Metal2 ;
        RECT 1147.480 0.000 1147.880 0.400 ;
    END
  END Tile_X4Y0_FrameStrobe[10]
  PIN Tile_X4Y0_FrameStrobe[11]
    DIRECTION INPUT ;
    USE SIGNAL ;
    ANTENNAGATEAREA 0.180700 ;
    PORT
      LAYER Metal2 ;
        RECT 1148.440 0.000 1148.840 0.400 ;
    END
  END Tile_X4Y0_FrameStrobe[11]
  PIN Tile_X4Y0_FrameStrobe[12]
    DIRECTION INPUT ;
    USE SIGNAL ;
    ANTENNAGATEAREA 0.180700 ;
    PORT
      LAYER Metal2 ;
        RECT 1149.400 0.000 1149.800 0.400 ;
    END
  END Tile_X4Y0_FrameStrobe[12]
  PIN Tile_X4Y0_FrameStrobe[13]
    DIRECTION INPUT ;
    USE SIGNAL ;
    ANTENNAGATEAREA 0.180700 ;
    PORT
      LAYER Metal2 ;
        RECT 1150.360 0.000 1150.760 0.400 ;
    END
  END Tile_X4Y0_FrameStrobe[13]
  PIN Tile_X4Y0_FrameStrobe[14]
    DIRECTION INPUT ;
    USE SIGNAL ;
    ANTENNAGATEAREA 0.180700 ;
    PORT
      LAYER Metal2 ;
        RECT 1151.320 0.000 1151.720 0.400 ;
    END
  END Tile_X4Y0_FrameStrobe[14]
  PIN Tile_X4Y0_FrameStrobe[15]
    DIRECTION INPUT ;
    USE SIGNAL ;
    ANTENNAGATEAREA 0.180700 ;
    PORT
      LAYER Metal2 ;
        RECT 1152.280 0.000 1152.680 0.400 ;
    END
  END Tile_X4Y0_FrameStrobe[15]
  PIN Tile_X4Y0_FrameStrobe[16]
    DIRECTION INPUT ;
    USE SIGNAL ;
    ANTENNAGATEAREA 0.180700 ;
    PORT
      LAYER Metal2 ;
        RECT 1153.240 0.000 1153.640 0.400 ;
    END
  END Tile_X4Y0_FrameStrobe[16]
  PIN Tile_X4Y0_FrameStrobe[17]
    DIRECTION INPUT ;
    USE SIGNAL ;
    ANTENNAGATEAREA 0.180700 ;
    PORT
      LAYER Metal2 ;
        RECT 1154.200 0.000 1154.600 0.400 ;
    END
  END Tile_X4Y0_FrameStrobe[17]
  PIN Tile_X4Y0_FrameStrobe[18]
    DIRECTION INPUT ;
    USE SIGNAL ;
    ANTENNAGATEAREA 0.180700 ;
    PORT
      LAYER Metal2 ;
        RECT 1155.160 0.000 1155.560 0.400 ;
    END
  END Tile_X4Y0_FrameStrobe[18]
  PIN Tile_X4Y0_FrameStrobe[19]
    DIRECTION INPUT ;
    USE SIGNAL ;
    ANTENNAGATEAREA 0.180700 ;
    PORT
      LAYER Metal2 ;
        RECT 1156.120 0.000 1156.520 0.400 ;
    END
  END Tile_X4Y0_FrameStrobe[19]
  PIN Tile_X4Y0_FrameStrobe[1]
    DIRECTION INPUT ;
    USE SIGNAL ;
    ANTENNAGATEAREA 0.180700 ;
    PORT
      LAYER Metal2 ;
        RECT 1138.840 0.000 1139.240 0.400 ;
    END
  END Tile_X4Y0_FrameStrobe[1]
  PIN Tile_X4Y0_FrameStrobe[2]
    DIRECTION INPUT ;
    USE SIGNAL ;
    ANTENNAGATEAREA 0.180700 ;
    PORT
      LAYER Metal2 ;
        RECT 1139.800 0.000 1140.200 0.400 ;
    END
  END Tile_X4Y0_FrameStrobe[2]
  PIN Tile_X4Y0_FrameStrobe[3]
    DIRECTION INPUT ;
    USE SIGNAL ;
    ANTENNAGATEAREA 0.180700 ;
    PORT
      LAYER Metal2 ;
        RECT 1140.760 0.000 1141.160 0.400 ;
    END
  END Tile_X4Y0_FrameStrobe[3]
  PIN Tile_X4Y0_FrameStrobe[4]
    DIRECTION INPUT ;
    USE SIGNAL ;
    ANTENNAGATEAREA 0.180700 ;
    PORT
      LAYER Metal2 ;
        RECT 1141.720 0.000 1142.120 0.400 ;
    END
  END Tile_X4Y0_FrameStrobe[4]
  PIN Tile_X4Y0_FrameStrobe[5]
    DIRECTION INPUT ;
    USE SIGNAL ;
    ANTENNAGATEAREA 0.180700 ;
    PORT
      LAYER Metal2 ;
        RECT 1142.680 0.000 1143.080 0.400 ;
    END
  END Tile_X4Y0_FrameStrobe[5]
  PIN Tile_X4Y0_FrameStrobe[6]
    DIRECTION INPUT ;
    USE SIGNAL ;
    ANTENNAGATEAREA 0.180700 ;
    PORT
      LAYER Metal2 ;
        RECT 1143.640 0.000 1144.040 0.400 ;
    END
  END Tile_X4Y0_FrameStrobe[6]
  PIN Tile_X4Y0_FrameStrobe[7]
    DIRECTION INPUT ;
    USE SIGNAL ;
    ANTENNAGATEAREA 0.180700 ;
    PORT
      LAYER Metal2 ;
        RECT 1144.600 0.000 1145.000 0.400 ;
    END
  END Tile_X4Y0_FrameStrobe[7]
  PIN Tile_X4Y0_FrameStrobe[8]
    DIRECTION INPUT ;
    USE SIGNAL ;
    ANTENNAGATEAREA 0.180700 ;
    PORT
      LAYER Metal2 ;
        RECT 1145.560 0.000 1145.960 0.400 ;
    END
  END Tile_X4Y0_FrameStrobe[8]
  PIN Tile_X4Y0_FrameStrobe[9]
    DIRECTION INPUT ;
    USE SIGNAL ;
    ANTENNAGATEAREA 0.180700 ;
    PORT
      LAYER Metal2 ;
        RECT 1146.520 0.000 1146.920 0.400 ;
    END
  END Tile_X4Y0_FrameStrobe[9]
  PIN Tile_X4Y0_FrameStrobe_O[0]
    DIRECTION OUTPUT ;
    USE SIGNAL ;
    ANTENNADIFFAREA 2.724000 ;
    PORT
      LAYER Metal2 ;
        RECT 938.200 78.980 938.600 79.380 ;
    END
  END Tile_X4Y0_FrameStrobe_O[0]
  PIN Tile_X4Y0_FrameStrobe_O[10]
    DIRECTION OUTPUT ;
    USE SIGNAL ;
    ANTENNADIFFAREA 2.724000 ;
    PORT
      LAYER Metal2 ;
        RECT 957.400 78.980 957.800 79.380 ;
    END
  END Tile_X4Y0_FrameStrobe_O[10]
  PIN Tile_X4Y0_FrameStrobe_O[11]
    DIRECTION OUTPUT ;
    USE SIGNAL ;
    ANTENNADIFFAREA 2.724000 ;
    PORT
      LAYER Metal2 ;
        RECT 959.320 78.980 959.720 79.380 ;
    END
  END Tile_X4Y0_FrameStrobe_O[11]
  PIN Tile_X4Y0_FrameStrobe_O[12]
    DIRECTION OUTPUT ;
    USE SIGNAL ;
    ANTENNADIFFAREA 2.724000 ;
    PORT
      LAYER Metal2 ;
        RECT 961.240 78.980 961.640 79.380 ;
    END
  END Tile_X4Y0_FrameStrobe_O[12]
  PIN Tile_X4Y0_FrameStrobe_O[13]
    DIRECTION OUTPUT ;
    USE SIGNAL ;
    ANTENNADIFFAREA 2.724000 ;
    PORT
      LAYER Metal2 ;
        RECT 963.160 78.980 963.560 79.380 ;
    END
  END Tile_X4Y0_FrameStrobe_O[13]
  PIN Tile_X4Y0_FrameStrobe_O[14]
    DIRECTION OUTPUT ;
    USE SIGNAL ;
    ANTENNADIFFAREA 2.724000 ;
    PORT
      LAYER Metal2 ;
        RECT 965.080 78.980 965.480 79.380 ;
    END
  END Tile_X4Y0_FrameStrobe_O[14]
  PIN Tile_X4Y0_FrameStrobe_O[15]
    DIRECTION OUTPUT ;
    USE SIGNAL ;
    ANTENNADIFFAREA 2.724000 ;
    PORT
      LAYER Metal2 ;
        RECT 967.000 78.980 967.400 79.380 ;
    END
  END Tile_X4Y0_FrameStrobe_O[15]
  PIN Tile_X4Y0_FrameStrobe_O[16]
    DIRECTION OUTPUT ;
    USE SIGNAL ;
    ANTENNADIFFAREA 2.724000 ;
    PORT
      LAYER Metal2 ;
        RECT 968.920 78.980 969.320 79.380 ;
    END
  END Tile_X4Y0_FrameStrobe_O[16]
  PIN Tile_X4Y0_FrameStrobe_O[17]
    DIRECTION OUTPUT ;
    USE SIGNAL ;
    ANTENNADIFFAREA 2.724000 ;
    PORT
      LAYER Metal2 ;
        RECT 970.840 78.980 971.240 79.380 ;
    END
  END Tile_X4Y0_FrameStrobe_O[17]
  PIN Tile_X4Y0_FrameStrobe_O[18]
    DIRECTION OUTPUT ;
    USE SIGNAL ;
    ANTENNADIFFAREA 2.724000 ;
    PORT
      LAYER Metal2 ;
        RECT 972.760 78.980 973.160 79.380 ;
    END
  END Tile_X4Y0_FrameStrobe_O[18]
  PIN Tile_X4Y0_FrameStrobe_O[19]
    DIRECTION OUTPUT ;
    USE SIGNAL ;
    ANTENNADIFFAREA 2.724000 ;
    PORT
      LAYER Metal2 ;
        RECT 974.680 78.980 975.080 79.380 ;
    END
  END Tile_X4Y0_FrameStrobe_O[19]
  PIN Tile_X4Y0_FrameStrobe_O[1]
    DIRECTION OUTPUT ;
    USE SIGNAL ;
    ANTENNADIFFAREA 2.724000 ;
    PORT
      LAYER Metal2 ;
        RECT 940.120 78.980 940.520 79.380 ;
    END
  END Tile_X4Y0_FrameStrobe_O[1]
  PIN Tile_X4Y0_FrameStrobe_O[2]
    DIRECTION OUTPUT ;
    USE SIGNAL ;
    ANTENNADIFFAREA 2.724000 ;
    PORT
      LAYER Metal2 ;
        RECT 942.040 78.980 942.440 79.380 ;
    END
  END Tile_X4Y0_FrameStrobe_O[2]
  PIN Tile_X4Y0_FrameStrobe_O[3]
    DIRECTION OUTPUT ;
    USE SIGNAL ;
    ANTENNADIFFAREA 2.724000 ;
    PORT
      LAYER Metal2 ;
        RECT 943.960 78.980 944.360 79.380 ;
    END
  END Tile_X4Y0_FrameStrobe_O[3]
  PIN Tile_X4Y0_FrameStrobe_O[4]
    DIRECTION OUTPUT ;
    USE SIGNAL ;
    ANTENNADIFFAREA 2.724000 ;
    PORT
      LAYER Metal2 ;
        RECT 945.880 78.980 946.280 79.380 ;
    END
  END Tile_X4Y0_FrameStrobe_O[4]
  PIN Tile_X4Y0_FrameStrobe_O[5]
    DIRECTION OUTPUT ;
    USE SIGNAL ;
    ANTENNADIFFAREA 2.724000 ;
    PORT
      LAYER Metal2 ;
        RECT 947.800 78.980 948.200 79.380 ;
    END
  END Tile_X4Y0_FrameStrobe_O[5]
  PIN Tile_X4Y0_FrameStrobe_O[6]
    DIRECTION OUTPUT ;
    USE SIGNAL ;
    ANTENNADIFFAREA 2.724000 ;
    PORT
      LAYER Metal2 ;
        RECT 949.720 78.980 950.120 79.380 ;
    END
  END Tile_X4Y0_FrameStrobe_O[6]
  PIN Tile_X4Y0_FrameStrobe_O[7]
    DIRECTION OUTPUT ;
    USE SIGNAL ;
    ANTENNADIFFAREA 2.724000 ;
    PORT
      LAYER Metal2 ;
        RECT 951.640 78.980 952.040 79.380 ;
    END
  END Tile_X4Y0_FrameStrobe_O[7]
  PIN Tile_X4Y0_FrameStrobe_O[8]
    DIRECTION OUTPUT ;
    USE SIGNAL ;
    ANTENNADIFFAREA 2.724000 ;
    PORT
      LAYER Metal2 ;
        RECT 953.560 78.980 953.960 79.380 ;
    END
  END Tile_X4Y0_FrameStrobe_O[8]
  PIN Tile_X4Y0_FrameStrobe_O[9]
    DIRECTION OUTPUT ;
    USE SIGNAL ;
    ANTENNADIFFAREA 2.724000 ;
    PORT
      LAYER Metal2 ;
        RECT 955.480 78.980 955.880 79.380 ;
    END
  END Tile_X4Y0_FrameStrobe_O[9]
  PIN Tile_X4Y0_N1END[0]
    DIRECTION INPUT ;
    USE SIGNAL ;
    ANTENNAGATEAREA 0.393900 ;
    PORT
      LAYER Metal2 ;
        RECT 934.360 0.000 934.760 0.400 ;
    END
  END Tile_X4Y0_N1END[0]
  PIN Tile_X4Y0_N1END[1]
    DIRECTION INPUT ;
    USE SIGNAL ;
    ANTENNAGATEAREA 0.393900 ;
    PORT
      LAYER Metal2 ;
        RECT 936.280 0.000 936.680 0.400 ;
    END
  END Tile_X4Y0_N1END[1]
  PIN Tile_X4Y0_N1END[2]
    DIRECTION INPUT ;
    USE SIGNAL ;
    ANTENNAGATEAREA 0.393900 ;
    PORT
      LAYER Metal2 ;
        RECT 938.200 0.000 938.600 0.400 ;
    END
  END Tile_X4Y0_N1END[2]
  PIN Tile_X4Y0_N1END[3]
    DIRECTION INPUT ;
    USE SIGNAL ;
    ANTENNAGATEAREA 0.180700 ;
    PORT
      LAYER Metal2 ;
        RECT 940.120 0.000 940.520 0.400 ;
    END
  END Tile_X4Y0_N1END[3]
  PIN Tile_X4Y0_N2END[0]
    DIRECTION INPUT ;
    USE SIGNAL ;
    ANTENNAGATEAREA 0.180700 ;
    PORT
      LAYER Metal2 ;
        RECT 959.320 0.000 959.720 0.400 ;
    END
  END Tile_X4Y0_N2END[0]
  PIN Tile_X4Y0_N2END[1]
    DIRECTION INPUT ;
    USE SIGNAL ;
    ANTENNAGATEAREA 0.180700 ;
    PORT
      LAYER Metal2 ;
        RECT 960.280 0.000 960.680 0.400 ;
    END
  END Tile_X4Y0_N2END[1]
  PIN Tile_X4Y0_N2END[2]
    DIRECTION INPUT ;
    USE SIGNAL ;
    ANTENNAGATEAREA 0.180700 ;
    PORT
      LAYER Metal2 ;
        RECT 961.240 0.000 961.640 0.400 ;
    END
  END Tile_X4Y0_N2END[2]
  PIN Tile_X4Y0_N2END[3]
    DIRECTION INPUT ;
    USE SIGNAL ;
    ANTENNAGATEAREA 0.180700 ;
    PORT
      LAYER Metal2 ;
        RECT 962.200 0.000 962.600 0.400 ;
    END
  END Tile_X4Y0_N2END[3]
  PIN Tile_X4Y0_N2END[4]
    DIRECTION INPUT ;
    USE SIGNAL ;
    ANTENNAGATEAREA 0.180700 ;
    PORT
      LAYER Metal2 ;
        RECT 963.160 0.000 963.560 0.400 ;
    END
  END Tile_X4Y0_N2END[4]
  PIN Tile_X4Y0_N2END[5]
    DIRECTION INPUT ;
    USE SIGNAL ;
    ANTENNAGATEAREA 0.393900 ;
    PORT
      LAYER Metal2 ;
        RECT 964.120 0.000 964.520 0.400 ;
    END
  END Tile_X4Y0_N2END[5]
  PIN Tile_X4Y0_N2END[6]
    DIRECTION INPUT ;
    USE SIGNAL ;
    ANTENNAGATEAREA 0.393900 ;
    PORT
      LAYER Metal2 ;
        RECT 965.080 0.000 965.480 0.400 ;
    END
  END Tile_X4Y0_N2END[6]
  PIN Tile_X4Y0_N2END[7]
    DIRECTION INPUT ;
    USE SIGNAL ;
    ANTENNAGATEAREA 0.393900 ;
    PORT
      LAYER Metal2 ;
        RECT 966.040 0.000 966.440 0.400 ;
    END
  END Tile_X4Y0_N2END[7]
  PIN Tile_X4Y0_N2MID[0]
    DIRECTION INPUT ;
    USE SIGNAL ;
    ANTENNAGATEAREA 0.393900 ;
    PORT
      LAYER Metal2 ;
        RECT 944.920 0.000 945.320 0.400 ;
    END
  END Tile_X4Y0_N2MID[0]
  PIN Tile_X4Y0_N2MID[1]
    DIRECTION INPUT ;
    USE SIGNAL ;
    ANTENNAGATEAREA 0.393900 ;
    PORT
      LAYER Metal2 ;
        RECT 945.880 0.000 946.280 0.400 ;
    END
  END Tile_X4Y0_N2MID[1]
  PIN Tile_X4Y0_N2MID[2]
    DIRECTION INPUT ;
    USE SIGNAL ;
    ANTENNAGATEAREA 0.393900 ;
    PORT
      LAYER Metal2 ;
        RECT 946.840 0.000 947.240 0.400 ;
    END
  END Tile_X4Y0_N2MID[2]
  PIN Tile_X4Y0_N2MID[3]
    DIRECTION INPUT ;
    USE SIGNAL ;
    ANTENNAGATEAREA 0.180700 ;
    PORT
      LAYER Metal2 ;
        RECT 947.800 0.000 948.200 0.400 ;
    END
  END Tile_X4Y0_N2MID[3]
  PIN Tile_X4Y0_N2MID[4]
    DIRECTION INPUT ;
    USE SIGNAL ;
    ANTENNAGATEAREA 0.180700 ;
    PORT
      LAYER Metal2 ;
        RECT 948.760 0.000 949.160 0.400 ;
    END
  END Tile_X4Y0_N2MID[4]
  PIN Tile_X4Y0_N2MID[5]
    DIRECTION INPUT ;
    USE SIGNAL ;
    ANTENNAGATEAREA 0.393900 ;
    PORT
      LAYER Metal2 ;
        RECT 949.720 0.000 950.120 0.400 ;
    END
  END Tile_X4Y0_N2MID[5]
  PIN Tile_X4Y0_N2MID[6]
    DIRECTION INPUT ;
    USE SIGNAL ;
    ANTENNAGATEAREA 0.393900 ;
    PORT
      LAYER Metal2 ;
        RECT 950.680 0.000 951.080 0.400 ;
    END
  END Tile_X4Y0_N2MID[6]
  PIN Tile_X4Y0_N2MID[7]
    DIRECTION INPUT ;
    USE SIGNAL ;
    ANTENNAGATEAREA 0.393900 ;
    PORT
      LAYER Metal2 ;
        RECT 951.640 0.000 952.040 0.400 ;
    END
  END Tile_X4Y0_N2MID[7]
  PIN Tile_X4Y0_N4END[0]
    DIRECTION INPUT ;
    USE SIGNAL ;
    ANTENNAGATEAREA 0.180700 ;
    PORT
      LAYER Metal2 ;
        RECT 977.560 0.000 977.960 0.400 ;
    END
  END Tile_X4Y0_N4END[0]
  PIN Tile_X4Y0_N4END[10]
    DIRECTION INPUT ;
    USE SIGNAL ;
    ANTENNAGATEAREA 0.180700 ;
    PORT
      LAYER Metal2 ;
        RECT 987.160 0.000 987.560 0.400 ;
    END
  END Tile_X4Y0_N4END[10]
  PIN Tile_X4Y0_N4END[11]
    DIRECTION INPUT ;
    USE SIGNAL ;
    ANTENNAGATEAREA 0.180700 ;
    PORT
      LAYER Metal2 ;
        RECT 988.120 0.000 988.520 0.400 ;
    END
  END Tile_X4Y0_N4END[11]
  PIN Tile_X4Y0_N4END[12]
    DIRECTION INPUT ;
    USE SIGNAL ;
    ANTENNAGATEAREA 0.180700 ;
    PORT
      LAYER Metal2 ;
        RECT 989.080 0.000 989.480 0.400 ;
    END
  END Tile_X4Y0_N4END[12]
  PIN Tile_X4Y0_N4END[13]
    DIRECTION INPUT ;
    USE SIGNAL ;
    ANTENNAGATEAREA 0.180700 ;
    PORT
      LAYER Metal2 ;
        RECT 990.040 0.000 990.440 0.400 ;
    END
  END Tile_X4Y0_N4END[13]
  PIN Tile_X4Y0_N4END[14]
    DIRECTION INPUT ;
    USE SIGNAL ;
    ANTENNAGATEAREA 0.180700 ;
    PORT
      LAYER Metal2 ;
        RECT 991.000 0.000 991.400 0.400 ;
    END
  END Tile_X4Y0_N4END[14]
  PIN Tile_X4Y0_N4END[15]
    DIRECTION INPUT ;
    USE SIGNAL ;
    ANTENNAGATEAREA 0.180700 ;
    PORT
      LAYER Metal2 ;
        RECT 991.960 0.000 992.360 0.400 ;
    END
  END Tile_X4Y0_N4END[15]
  PIN Tile_X4Y0_N4END[1]
    DIRECTION INPUT ;
    USE SIGNAL ;
    ANTENNAGATEAREA 0.180700 ;
    PORT
      LAYER Metal2 ;
        RECT 978.520 0.000 978.920 0.400 ;
    END
  END Tile_X4Y0_N4END[1]
  PIN Tile_X4Y0_N4END[2]
    DIRECTION INPUT ;
    USE SIGNAL ;
    ANTENNAGATEAREA 0.180700 ;
    PORT
      LAYER Metal2 ;
        RECT 979.480 0.000 979.880 0.400 ;
    END
  END Tile_X4Y0_N4END[2]
  PIN Tile_X4Y0_N4END[3]
    DIRECTION INPUT ;
    USE SIGNAL ;
    ANTENNAGATEAREA 0.180700 ;
    PORT
      LAYER Metal2 ;
        RECT 980.440 0.000 980.840 0.400 ;
    END
  END Tile_X4Y0_N4END[3]
  PIN Tile_X4Y0_N4END[4]
    DIRECTION INPUT ;
    USE SIGNAL ;
    ANTENNAGATEAREA 0.180700 ;
    PORT
      LAYER Metal2 ;
        RECT 981.400 0.000 981.800 0.400 ;
    END
  END Tile_X4Y0_N4END[4]
  PIN Tile_X4Y0_N4END[5]
    DIRECTION INPUT ;
    USE SIGNAL ;
    ANTENNAGATEAREA 0.180700 ;
    PORT
      LAYER Metal2 ;
        RECT 982.360 0.000 982.760 0.400 ;
    END
  END Tile_X4Y0_N4END[5]
  PIN Tile_X4Y0_N4END[6]
    DIRECTION INPUT ;
    USE SIGNAL ;
    ANTENNAGATEAREA 0.180700 ;
    PORT
      LAYER Metal2 ;
        RECT 983.320 0.000 983.720 0.400 ;
    END
  END Tile_X4Y0_N4END[6]
  PIN Tile_X4Y0_N4END[7]
    DIRECTION INPUT ;
    USE SIGNAL ;
    ANTENNAGATEAREA 0.180700 ;
    PORT
      LAYER Metal2 ;
        RECT 984.280 0.000 984.680 0.400 ;
    END
  END Tile_X4Y0_N4END[7]
  PIN Tile_X4Y0_N4END[8]
    DIRECTION INPUT ;
    USE SIGNAL ;
    ANTENNAGATEAREA 0.180700 ;
    ANTENNADIFFAREA 2.015400 ;
    PORT
      LAYER Metal2 ;
        RECT 985.240 0.000 985.640 0.400 ;
    END
  END Tile_X4Y0_N4END[8]
  PIN Tile_X4Y0_N4END[9]
    DIRECTION INPUT ;
    USE SIGNAL ;
    ANTENNAGATEAREA 0.180700 ;
    PORT
      LAYER Metal2 ;
        RECT 986.200 0.000 986.600 0.400 ;
    END
  END Tile_X4Y0_N4END[9]
  PIN Tile_X4Y0_NN4END[0]
    DIRECTION INPUT ;
    USE SIGNAL ;
    ANTENNAGATEAREA 0.180700 ;
    PORT
      LAYER Metal2 ;
        RECT 1007.320 0.000 1007.720 0.400 ;
    END
  END Tile_X4Y0_NN4END[0]
  PIN Tile_X4Y0_NN4END[10]
    DIRECTION INPUT ;
    USE SIGNAL ;
    ANTENNAGATEAREA 0.180700 ;
    ANTENNADIFFAREA 2.015400 ;
    PORT
      LAYER Metal2 ;
        RECT 1016.920 0.000 1017.320 0.400 ;
    END
  END Tile_X4Y0_NN4END[10]
  PIN Tile_X4Y0_NN4END[11]
    DIRECTION INPUT ;
    USE SIGNAL ;
    ANTENNAGATEAREA 0.180700 ;
    PORT
      LAYER Metal2 ;
        RECT 1017.880 0.000 1018.280 0.400 ;
    END
  END Tile_X4Y0_NN4END[11]
  PIN Tile_X4Y0_NN4END[12]
    DIRECTION INPUT ;
    USE SIGNAL ;
    ANTENNAGATEAREA 0.180700 ;
    PORT
      LAYER Metal2 ;
        RECT 1018.840 0.000 1019.240 0.400 ;
    END
  END Tile_X4Y0_NN4END[12]
  PIN Tile_X4Y0_NN4END[13]
    DIRECTION INPUT ;
    USE SIGNAL ;
    ANTENNAGATEAREA 0.180700 ;
    PORT
      LAYER Metal2 ;
        RECT 1019.800 0.000 1020.200 0.400 ;
    END
  END Tile_X4Y0_NN4END[13]
  PIN Tile_X4Y0_NN4END[14]
    DIRECTION INPUT ;
    USE SIGNAL ;
    ANTENNAGATEAREA 0.180700 ;
    PORT
      LAYER Metal2 ;
        RECT 1020.760 0.000 1021.160 0.400 ;
    END
  END Tile_X4Y0_NN4END[14]
  PIN Tile_X4Y0_NN4END[15]
    DIRECTION INPUT ;
    USE SIGNAL ;
    ANTENNAGATEAREA 0.180700 ;
    PORT
      LAYER Metal2 ;
        RECT 1021.720 0.000 1022.120 0.400 ;
    END
  END Tile_X4Y0_NN4END[15]
  PIN Tile_X4Y0_NN4END[1]
    DIRECTION INPUT ;
    USE SIGNAL ;
    ANTENNAGATEAREA 0.180700 ;
    PORT
      LAYER Metal2 ;
        RECT 1008.280 0.000 1008.680 0.400 ;
    END
  END Tile_X4Y0_NN4END[1]
  PIN Tile_X4Y0_NN4END[2]
    DIRECTION INPUT ;
    USE SIGNAL ;
    ANTENNAGATEAREA 0.180700 ;
    PORT
      LAYER Metal2 ;
        RECT 1009.240 0.000 1009.640 0.400 ;
    END
  END Tile_X4Y0_NN4END[2]
  PIN Tile_X4Y0_NN4END[3]
    DIRECTION INPUT ;
    USE SIGNAL ;
    ANTENNAGATEAREA 0.180700 ;
    PORT
      LAYER Metal2 ;
        RECT 1010.200 0.000 1010.600 0.400 ;
    END
  END Tile_X4Y0_NN4END[3]
  PIN Tile_X4Y0_NN4END[4]
    DIRECTION INPUT ;
    USE SIGNAL ;
    ANTENNAGATEAREA 0.180700 ;
    PORT
      LAYER Metal2 ;
        RECT 1011.160 0.000 1011.560 0.400 ;
    END
  END Tile_X4Y0_NN4END[4]
  PIN Tile_X4Y0_NN4END[5]
    DIRECTION INPUT ;
    USE SIGNAL ;
    ANTENNAGATEAREA 0.180700 ;
    ANTENNADIFFAREA 2.015400 ;
    PORT
      LAYER Metal2 ;
        RECT 1012.120 0.000 1012.520 0.400 ;
    END
  END Tile_X4Y0_NN4END[5]
  PIN Tile_X4Y0_NN4END[6]
    DIRECTION INPUT ;
    USE SIGNAL ;
    ANTENNAGATEAREA 0.180700 ;
    PORT
      LAYER Metal2 ;
        RECT 1013.080 0.000 1013.480 0.400 ;
    END
  END Tile_X4Y0_NN4END[6]
  PIN Tile_X4Y0_NN4END[7]
    DIRECTION INPUT ;
    USE SIGNAL ;
    ANTENNAGATEAREA 0.180700 ;
    ANTENNADIFFAREA 2.015400 ;
    PORT
      LAYER Metal2 ;
        RECT 1014.040 0.000 1014.440 0.400 ;
    END
  END Tile_X4Y0_NN4END[7]
  PIN Tile_X4Y0_NN4END[8]
    DIRECTION INPUT ;
    USE SIGNAL ;
    ANTENNAGATEAREA 0.180700 ;
    PORT
      LAYER Metal2 ;
        RECT 1015.000 0.000 1015.400 0.400 ;
    END
  END Tile_X4Y0_NN4END[8]
  PIN Tile_X4Y0_NN4END[9]
    DIRECTION INPUT ;
    USE SIGNAL ;
    ANTENNAGATEAREA 0.180700 ;
    PORT
      LAYER Metal2 ;
        RECT 1015.960 0.000 1016.360 0.400 ;
    END
  END Tile_X4Y0_NN4END[9]
  PIN Tile_X4Y0_S1BEG[0]
    DIRECTION OUTPUT ;
    USE SIGNAL ;
    ANTENNADIFFAREA 2.724000 ;
    PORT
      LAYER Metal2 ;
        RECT 1032.280 0.000 1032.680 0.400 ;
    END
  END Tile_X4Y0_S1BEG[0]
  PIN Tile_X4Y0_S1BEG[1]
    DIRECTION OUTPUT ;
    USE SIGNAL ;
    ANTENNADIFFAREA 2.724000 ;
    PORT
      LAYER Metal2 ;
        RECT 1034.200 0.000 1034.600 0.400 ;
    END
  END Tile_X4Y0_S1BEG[1]
  PIN Tile_X4Y0_S1BEG[2]
    DIRECTION OUTPUT ;
    USE SIGNAL ;
    ANTENNADIFFAREA 2.724000 ;
    PORT
      LAYER Metal2 ;
        RECT 1036.120 0.000 1036.520 0.400 ;
    END
  END Tile_X4Y0_S1BEG[2]
  PIN Tile_X4Y0_S1BEG[3]
    DIRECTION OUTPUT ;
    USE SIGNAL ;
    ANTENNADIFFAREA 2.724000 ;
    PORT
      LAYER Metal2 ;
        RECT 1038.040 0.000 1038.440 0.400 ;
    END
  END Tile_X4Y0_S1BEG[3]
  PIN Tile_X4Y0_S2BEG[0]
    DIRECTION OUTPUT ;
    USE SIGNAL ;
    ANTENNADIFFAREA 2.724000 ;
    PORT
      LAYER Metal2 ;
        RECT 1039.960 0.000 1040.360 0.400 ;
    END
  END Tile_X4Y0_S2BEG[0]
  PIN Tile_X4Y0_S2BEG[1]
    DIRECTION OUTPUT ;
    USE SIGNAL ;
    ANTENNADIFFAREA 2.724000 ;
    PORT
      LAYER Metal2 ;
        RECT 1041.880 0.000 1042.280 0.400 ;
    END
  END Tile_X4Y0_S2BEG[1]
  PIN Tile_X4Y0_S2BEG[2]
    DIRECTION OUTPUT ;
    USE SIGNAL ;
    ANTENNADIFFAREA 2.724000 ;
    PORT
      LAYER Metal2 ;
        RECT 1043.800 0.000 1044.200 0.400 ;
    END
  END Tile_X4Y0_S2BEG[2]
  PIN Tile_X4Y0_S2BEG[3]
    DIRECTION OUTPUT ;
    USE SIGNAL ;
    ANTENNADIFFAREA 2.724000 ;
    PORT
      LAYER Metal2 ;
        RECT 1045.720 0.000 1046.120 0.400 ;
    END
  END Tile_X4Y0_S2BEG[3]
  PIN Tile_X4Y0_S2BEG[4]
    DIRECTION OUTPUT ;
    USE SIGNAL ;
    ANTENNADIFFAREA 2.724000 ;
    PORT
      LAYER Metal2 ;
        RECT 1047.640 0.000 1048.040 0.400 ;
    END
  END Tile_X4Y0_S2BEG[4]
  PIN Tile_X4Y0_S2BEG[5]
    DIRECTION OUTPUT ;
    USE SIGNAL ;
    ANTENNADIFFAREA 2.724000 ;
    PORT
      LAYER Metal2 ;
        RECT 1049.560 0.000 1049.960 0.400 ;
    END
  END Tile_X4Y0_S2BEG[5]
  PIN Tile_X4Y0_S2BEG[6]
    DIRECTION OUTPUT ;
    USE SIGNAL ;
    ANTENNADIFFAREA 2.724000 ;
    PORT
      LAYER Metal2 ;
        RECT 1051.480 0.000 1051.880 0.400 ;
    END
  END Tile_X4Y0_S2BEG[6]
  PIN Tile_X4Y0_S2BEG[7]
    DIRECTION OUTPUT ;
    USE SIGNAL ;
    ANTENNADIFFAREA 2.724000 ;
    PORT
      LAYER Metal2 ;
        RECT 1053.400 0.000 1053.800 0.400 ;
    END
  END Tile_X4Y0_S2BEG[7]
  PIN Tile_X4Y0_S2BEGb[0]
    DIRECTION OUTPUT ;
    USE SIGNAL ;
    ANTENNADIFFAREA 2.724000 ;
    PORT
      LAYER Metal2 ;
        RECT 1058.200 0.000 1058.600 0.400 ;
    END
  END Tile_X4Y0_S2BEGb[0]
  PIN Tile_X4Y0_S2BEGb[1]
    DIRECTION OUTPUT ;
    USE SIGNAL ;
    ANTENNADIFFAREA 2.724000 ;
    PORT
      LAYER Metal2 ;
        RECT 1059.160 0.000 1059.560 0.400 ;
    END
  END Tile_X4Y0_S2BEGb[1]
  PIN Tile_X4Y0_S2BEGb[2]
    DIRECTION OUTPUT ;
    USE SIGNAL ;
    ANTENNADIFFAREA 2.724000 ;
    PORT
      LAYER Metal2 ;
        RECT 1060.120 0.000 1060.520 0.400 ;
    END
  END Tile_X4Y0_S2BEGb[2]
  PIN Tile_X4Y0_S2BEGb[3]
    DIRECTION OUTPUT ;
    USE SIGNAL ;
    ANTENNADIFFAREA 2.724000 ;
    PORT
      LAYER Metal2 ;
        RECT 1061.080 0.000 1061.480 0.400 ;
    END
  END Tile_X4Y0_S2BEGb[3]
  PIN Tile_X4Y0_S2BEGb[4]
    DIRECTION OUTPUT ;
    USE SIGNAL ;
    ANTENNADIFFAREA 2.724000 ;
    PORT
      LAYER Metal2 ;
        RECT 1062.040 0.000 1062.440 0.400 ;
    END
  END Tile_X4Y0_S2BEGb[4]
  PIN Tile_X4Y0_S2BEGb[5]
    DIRECTION OUTPUT ;
    USE SIGNAL ;
    ANTENNADIFFAREA 2.724000 ;
    PORT
      LAYER Metal2 ;
        RECT 1063.000 0.000 1063.400 0.400 ;
    END
  END Tile_X4Y0_S2BEGb[5]
  PIN Tile_X4Y0_S2BEGb[6]
    DIRECTION OUTPUT ;
    USE SIGNAL ;
    ANTENNADIFFAREA 2.724000 ;
    PORT
      LAYER Metal2 ;
        RECT 1063.960 0.000 1064.360 0.400 ;
    END
  END Tile_X4Y0_S2BEGb[6]
  PIN Tile_X4Y0_S2BEGb[7]
    DIRECTION OUTPUT ;
    USE SIGNAL ;
    ANTENNADIFFAREA 2.724000 ;
    PORT
      LAYER Metal2 ;
        RECT 1064.920 0.000 1065.320 0.400 ;
    END
  END Tile_X4Y0_S2BEGb[7]
  PIN Tile_X4Y0_S4BEG[0]
    DIRECTION OUTPUT ;
    USE SIGNAL ;
    ANTENNADIFFAREA 2.724000 ;
    PORT
      LAYER Metal2 ;
        RECT 1076.440 0.000 1076.840 0.400 ;
    END
  END Tile_X4Y0_S4BEG[0]
  PIN Tile_X4Y0_S4BEG[10]
    DIRECTION OUTPUT ;
    USE SIGNAL ;
    ANTENNADIFFAREA 2.724000 ;
    PORT
      LAYER Metal2 ;
        RECT 1086.040 0.000 1086.440 0.400 ;
    END
  END Tile_X4Y0_S4BEG[10]
  PIN Tile_X4Y0_S4BEG[11]
    DIRECTION OUTPUT ;
    USE SIGNAL ;
    ANTENNADIFFAREA 2.724000 ;
    PORT
      LAYER Metal2 ;
        RECT 1087.000 0.000 1087.400 0.400 ;
    END
  END Tile_X4Y0_S4BEG[11]
  PIN Tile_X4Y0_S4BEG[12]
    DIRECTION OUTPUT ;
    USE SIGNAL ;
    ANTENNADIFFAREA 2.724000 ;
    PORT
      LAYER Metal2 ;
        RECT 1087.960 0.000 1088.360 0.400 ;
    END
  END Tile_X4Y0_S4BEG[12]
  PIN Tile_X4Y0_S4BEG[13]
    DIRECTION OUTPUT ;
    USE SIGNAL ;
    ANTENNADIFFAREA 2.724000 ;
    PORT
      LAYER Metal2 ;
        RECT 1088.920 0.000 1089.320 0.400 ;
    END
  END Tile_X4Y0_S4BEG[13]
  PIN Tile_X4Y0_S4BEG[14]
    DIRECTION OUTPUT ;
    USE SIGNAL ;
    ANTENNADIFFAREA 2.724000 ;
    PORT
      LAYER Metal2 ;
        RECT 1089.880 0.000 1090.280 0.400 ;
    END
  END Tile_X4Y0_S4BEG[14]
  PIN Tile_X4Y0_S4BEG[15]
    DIRECTION OUTPUT ;
    USE SIGNAL ;
    ANTENNADIFFAREA 2.724000 ;
    PORT
      LAYER Metal2 ;
        RECT 1090.840 0.000 1091.240 0.400 ;
    END
  END Tile_X4Y0_S4BEG[15]
  PIN Tile_X4Y0_S4BEG[1]
    DIRECTION OUTPUT ;
    USE SIGNAL ;
    ANTENNADIFFAREA 2.724000 ;
    PORT
      LAYER Metal2 ;
        RECT 1077.400 0.000 1077.800 0.400 ;
    END
  END Tile_X4Y0_S4BEG[1]
  PIN Tile_X4Y0_S4BEG[2]
    DIRECTION OUTPUT ;
    USE SIGNAL ;
    ANTENNADIFFAREA 2.724000 ;
    PORT
      LAYER Metal2 ;
        RECT 1078.360 0.000 1078.760 0.400 ;
    END
  END Tile_X4Y0_S4BEG[2]
  PIN Tile_X4Y0_S4BEG[3]
    DIRECTION OUTPUT ;
    USE SIGNAL ;
    ANTENNADIFFAREA 2.724000 ;
    PORT
      LAYER Metal2 ;
        RECT 1079.320 0.000 1079.720 0.400 ;
    END
  END Tile_X4Y0_S4BEG[3]
  PIN Tile_X4Y0_S4BEG[4]
    DIRECTION OUTPUT ;
    USE SIGNAL ;
    ANTENNADIFFAREA 2.724000 ;
    PORT
      LAYER Metal2 ;
        RECT 1080.280 0.000 1080.680 0.400 ;
    END
  END Tile_X4Y0_S4BEG[4]
  PIN Tile_X4Y0_S4BEG[5]
    DIRECTION OUTPUT ;
    USE SIGNAL ;
    ANTENNADIFFAREA 2.724000 ;
    PORT
      LAYER Metal2 ;
        RECT 1081.240 0.000 1081.640 0.400 ;
    END
  END Tile_X4Y0_S4BEG[5]
  PIN Tile_X4Y0_S4BEG[6]
    DIRECTION OUTPUT ;
    USE SIGNAL ;
    ANTENNADIFFAREA 2.724000 ;
    PORT
      LAYER Metal2 ;
        RECT 1082.200 0.000 1082.600 0.400 ;
    END
  END Tile_X4Y0_S4BEG[6]
  PIN Tile_X4Y0_S4BEG[7]
    DIRECTION OUTPUT ;
    USE SIGNAL ;
    ANTENNADIFFAREA 2.724000 ;
    PORT
      LAYER Metal2 ;
        RECT 1083.160 0.000 1083.560 0.400 ;
    END
  END Tile_X4Y0_S4BEG[7]
  PIN Tile_X4Y0_S4BEG[8]
    DIRECTION OUTPUT ;
    USE SIGNAL ;
    ANTENNADIFFAREA 2.724000 ;
    PORT
      LAYER Metal2 ;
        RECT 1084.120 0.000 1084.520 0.400 ;
    END
  END Tile_X4Y0_S4BEG[8]
  PIN Tile_X4Y0_S4BEG[9]
    DIRECTION OUTPUT ;
    USE SIGNAL ;
    ANTENNADIFFAREA 2.724000 ;
    PORT
      LAYER Metal2 ;
        RECT 1085.080 0.000 1085.480 0.400 ;
    END
  END Tile_X4Y0_S4BEG[9]
  PIN Tile_X4Y0_SS4BEG[0]
    DIRECTION OUTPUT ;
    USE SIGNAL ;
    ANTENNADIFFAREA 2.724000 ;
    PORT
      LAYER Metal2 ;
        RECT 1106.200 0.000 1106.600 0.400 ;
    END
  END Tile_X4Y0_SS4BEG[0]
  PIN Tile_X4Y0_SS4BEG[10]
    DIRECTION OUTPUT ;
    USE SIGNAL ;
    ANTENNADIFFAREA 2.724000 ;
    PORT
      LAYER Metal2 ;
        RECT 1115.800 0.000 1116.200 0.400 ;
    END
  END Tile_X4Y0_SS4BEG[10]
  PIN Tile_X4Y0_SS4BEG[11]
    DIRECTION OUTPUT ;
    USE SIGNAL ;
    ANTENNADIFFAREA 2.724000 ;
    PORT
      LAYER Metal2 ;
        RECT 1116.760 0.000 1117.160 0.400 ;
    END
  END Tile_X4Y0_SS4BEG[11]
  PIN Tile_X4Y0_SS4BEG[12]
    DIRECTION OUTPUT ;
    USE SIGNAL ;
    ANTENNADIFFAREA 2.724000 ;
    PORT
      LAYER Metal2 ;
        RECT 1117.720 0.000 1118.120 0.400 ;
    END
  END Tile_X4Y0_SS4BEG[12]
  PIN Tile_X4Y0_SS4BEG[13]
    DIRECTION OUTPUT ;
    USE SIGNAL ;
    ANTENNADIFFAREA 2.724000 ;
    PORT
      LAYER Metal2 ;
        RECT 1118.680 0.000 1119.080 0.400 ;
    END
  END Tile_X4Y0_SS4BEG[13]
  PIN Tile_X4Y0_SS4BEG[14]
    DIRECTION OUTPUT ;
    USE SIGNAL ;
    ANTENNADIFFAREA 2.724000 ;
    PORT
      LAYER Metal2 ;
        RECT 1119.640 0.000 1120.040 0.400 ;
    END
  END Tile_X4Y0_SS4BEG[14]
  PIN Tile_X4Y0_SS4BEG[15]
    DIRECTION OUTPUT ;
    USE SIGNAL ;
    ANTENNADIFFAREA 2.724000 ;
    PORT
      LAYER Metal2 ;
        RECT 1120.600 0.000 1121.000 0.400 ;
    END
  END Tile_X4Y0_SS4BEG[15]
  PIN Tile_X4Y0_SS4BEG[1]
    DIRECTION OUTPUT ;
    USE SIGNAL ;
    ANTENNADIFFAREA 2.724000 ;
    PORT
      LAYER Metal2 ;
        RECT 1107.160 0.000 1107.560 0.400 ;
    END
  END Tile_X4Y0_SS4BEG[1]
  PIN Tile_X4Y0_SS4BEG[2]
    DIRECTION OUTPUT ;
    USE SIGNAL ;
    ANTENNADIFFAREA 2.724000 ;
    PORT
      LAYER Metal2 ;
        RECT 1108.120 0.000 1108.520 0.400 ;
    END
  END Tile_X4Y0_SS4BEG[2]
  PIN Tile_X4Y0_SS4BEG[3]
    DIRECTION OUTPUT ;
    USE SIGNAL ;
    ANTENNADIFFAREA 2.724000 ;
    PORT
      LAYER Metal2 ;
        RECT 1109.080 0.000 1109.480 0.400 ;
    END
  END Tile_X4Y0_SS4BEG[3]
  PIN Tile_X4Y0_SS4BEG[4]
    DIRECTION OUTPUT ;
    USE SIGNAL ;
    ANTENNADIFFAREA 2.724000 ;
    PORT
      LAYER Metal2 ;
        RECT 1110.040 0.000 1110.440 0.400 ;
    END
  END Tile_X4Y0_SS4BEG[4]
  PIN Tile_X4Y0_SS4BEG[5]
    DIRECTION OUTPUT ;
    USE SIGNAL ;
    ANTENNADIFFAREA 2.724000 ;
    PORT
      LAYER Metal2 ;
        RECT 1111.000 0.000 1111.400 0.400 ;
    END
  END Tile_X4Y0_SS4BEG[5]
  PIN Tile_X4Y0_SS4BEG[6]
    DIRECTION OUTPUT ;
    USE SIGNAL ;
    ANTENNADIFFAREA 2.724000 ;
    PORT
      LAYER Metal2 ;
        RECT 1111.960 0.000 1112.360 0.400 ;
    END
  END Tile_X4Y0_SS4BEG[6]
  PIN Tile_X4Y0_SS4BEG[7]
    DIRECTION OUTPUT ;
    USE SIGNAL ;
    ANTENNADIFFAREA 2.724000 ;
    PORT
      LAYER Metal2 ;
        RECT 1112.920 0.000 1113.320 0.400 ;
    END
  END Tile_X4Y0_SS4BEG[7]
  PIN Tile_X4Y0_SS4BEG[8]
    DIRECTION OUTPUT ;
    USE SIGNAL ;
    ANTENNADIFFAREA 2.724000 ;
    PORT
      LAYER Metal2 ;
        RECT 1113.880 0.000 1114.280 0.400 ;
    END
  END Tile_X4Y0_SS4BEG[8]
  PIN Tile_X4Y0_SS4BEG[9]
    DIRECTION OUTPUT ;
    USE SIGNAL ;
    ANTENNADIFFAREA 2.724000 ;
    PORT
      LAYER Metal2 ;
        RECT 1114.840 0.000 1115.240 0.400 ;
    END
  END Tile_X4Y0_SS4BEG[9]
  PIN Tile_X4Y0_UserCLKo
    DIRECTION OUTPUT ;
    USE SIGNAL ;
    ANTENNADIFFAREA 2.724000 ;
    PORT
      LAYER Metal3 ;
        RECT 1166.000 1.900 1166.400 2.300 ;
    END
  END Tile_X4Y0_UserCLKo
  PIN VGND
    DIRECTION INOUT ;
    USE GROUND ;
    PORT
      LAYER Metal4 ;
        RECT 15.380 0.000 16.380 79.380 ;
    END
    PORT
      LAYER Metal4 ;
        RECT 65.380 0.000 66.380 79.380 ;
    END
    PORT
      LAYER Metal4 ;
        RECT 115.380 0.000 116.380 79.380 ;
    END
    PORT
      LAYER Metal4 ;
        RECT 165.380 0.000 166.380 79.380 ;
    END
    PORT
      LAYER Metal4 ;
        RECT 215.380 0.000 216.380 79.380 ;
    END
    PORT
      LAYER Metal4 ;
        RECT 248.660 0.000 249.660 79.380 ;
    END
    PORT
      LAYER Metal4 ;
        RECT 298.660 0.000 299.660 79.380 ;
    END
    PORT
      LAYER Metal4 ;
        RECT 348.660 0.000 349.660 79.380 ;
    END
    PORT
      LAYER Metal4 ;
        RECT 398.660 0.000 399.660 79.380 ;
    END
    PORT
      LAYER Metal4 ;
        RECT 448.660 0.000 449.660 79.380 ;
    END
    PORT
      LAYER Metal4 ;
        RECT 481.940 0.000 482.940 79.380 ;
    END
    PORT
      LAYER Metal4 ;
        RECT 531.940 0.000 532.940 79.380 ;
    END
    PORT
      LAYER Metal4 ;
        RECT 581.940 0.000 582.940 79.380 ;
    END
    PORT
      LAYER Metal4 ;
        RECT 631.940 0.000 632.940 79.380 ;
    END
    PORT
      LAYER Metal4 ;
        RECT 681.940 0.000 682.940 79.380 ;
    END
    PORT
      LAYER Metal4 ;
        RECT 715.220 0.000 716.220 79.380 ;
    END
    PORT
      LAYER Metal4 ;
        RECT 765.220 0.000 766.220 79.380 ;
    END
    PORT
      LAYER Metal4 ;
        RECT 815.220 0.000 816.220 79.380 ;
    END
    PORT
      LAYER Metal4 ;
        RECT 865.220 0.000 866.220 79.380 ;
    END
    PORT
      LAYER Metal4 ;
        RECT 915.220 0.000 916.220 79.380 ;
    END
    PORT
      LAYER Metal4 ;
        RECT 948.500 0.000 949.500 79.380 ;
    END
    PORT
      LAYER Metal4 ;
        RECT 998.500 0.000 999.500 79.380 ;
    END
    PORT
      LAYER Metal4 ;
        RECT 1048.500 0.000 1049.500 79.380 ;
    END
    PORT
      LAYER Metal4 ;
        RECT 1098.500 0.000 1099.500 79.380 ;
    END
    PORT
      LAYER Metal4 ;
        RECT 1148.500 0.000 1149.500 79.380 ;
    END
  END VGND
  PIN VPWR
    DIRECTION INOUT ;
    USE POWER ;
    PORT
      LAYER Metal4 ;
        RECT 12.380 0.000 13.380 79.380 ;
    END
    PORT
      LAYER Metal4 ;
        RECT 62.380 0.000 63.380 79.380 ;
    END
    PORT
      LAYER Metal4 ;
        RECT 112.380 0.000 113.380 79.380 ;
    END
    PORT
      LAYER Metal4 ;
        RECT 162.380 0.000 163.380 79.380 ;
    END
    PORT
      LAYER Metal4 ;
        RECT 212.380 0.000 213.380 79.380 ;
    END
    PORT
      LAYER Metal4 ;
        RECT 245.660 0.000 246.660 79.380 ;
    END
    PORT
      LAYER Metal4 ;
        RECT 295.660 0.000 296.660 79.380 ;
    END
    PORT
      LAYER Metal4 ;
        RECT 345.660 0.000 346.660 79.380 ;
    END
    PORT
      LAYER Metal4 ;
        RECT 395.660 0.000 396.660 79.380 ;
    END
    PORT
      LAYER Metal4 ;
        RECT 445.660 0.000 446.660 79.380 ;
    END
    PORT
      LAYER Metal4 ;
        RECT 478.940 0.000 479.940 79.380 ;
    END
    PORT
      LAYER Metal4 ;
        RECT 528.940 0.000 529.940 79.380 ;
    END
    PORT
      LAYER Metal4 ;
        RECT 578.940 0.000 579.940 79.380 ;
    END
    PORT
      LAYER Metal4 ;
        RECT 628.940 0.000 629.940 79.380 ;
    END
    PORT
      LAYER Metal4 ;
        RECT 678.940 0.000 679.940 79.380 ;
    END
    PORT
      LAYER Metal4 ;
        RECT 712.220 0.000 713.220 79.380 ;
    END
    PORT
      LAYER Metal4 ;
        RECT 762.220 0.000 763.220 79.380 ;
    END
    PORT
      LAYER Metal4 ;
        RECT 812.220 0.000 813.220 79.380 ;
    END
    PORT
      LAYER Metal4 ;
        RECT 862.220 0.000 863.220 79.380 ;
    END
    PORT
      LAYER Metal4 ;
        RECT 912.220 0.000 913.220 79.380 ;
    END
    PORT
      LAYER Metal4 ;
        RECT 945.500 0.000 946.500 79.380 ;
    END
    PORT
      LAYER Metal4 ;
        RECT 995.500 0.000 996.500 79.380 ;
    END
    PORT
      LAYER Metal4 ;
        RECT 1045.500 0.000 1046.500 79.380 ;
    END
    PORT
      LAYER Metal4 ;
        RECT 1095.500 0.000 1096.500 79.380 ;
    END
    PORT
      LAYER Metal4 ;
        RECT 1145.500 0.000 1146.500 79.380 ;
    END
  END VPWR
  OBS
      LAYER GatPoly ;
        RECT 2.880 3.630 1163.520 75.750 ;
      LAYER Metal1 ;
        RECT 2.880 3.560 1163.520 75.820 ;
      LAYER Metal2 ;
        RECT 0.375 78.770 6.790 79.105 ;
        RECT 7.610 78.770 18.310 79.105 ;
        RECT 19.130 78.770 29.830 79.105 ;
        RECT 30.650 78.770 41.350 79.105 ;
        RECT 42.170 78.770 52.870 79.105 ;
        RECT 53.690 78.770 64.390 79.105 ;
        RECT 65.210 78.770 75.910 79.105 ;
        RECT 76.730 78.770 87.430 79.105 ;
        RECT 88.250 78.770 98.950 79.105 ;
        RECT 99.770 78.770 110.470 79.105 ;
        RECT 111.290 78.770 121.990 79.105 ;
        RECT 122.810 78.770 133.510 79.105 ;
        RECT 134.330 78.770 145.030 79.105 ;
        RECT 145.850 78.770 156.550 79.105 ;
        RECT 157.370 78.770 168.070 79.105 ;
        RECT 168.890 78.770 179.590 79.105 ;
        RECT 180.410 78.770 191.110 79.105 ;
        RECT 191.930 78.770 202.630 79.105 ;
        RECT 203.450 78.770 214.150 79.105 ;
        RECT 214.970 78.770 225.670 79.105 ;
        RECT 226.490 78.770 240.070 79.105 ;
        RECT 240.890 78.770 251.590 79.105 ;
        RECT 252.410 78.770 263.110 79.105 ;
        RECT 263.930 78.770 274.630 79.105 ;
        RECT 275.450 78.770 286.150 79.105 ;
        RECT 286.970 78.770 297.670 79.105 ;
        RECT 298.490 78.770 309.190 79.105 ;
        RECT 310.010 78.770 320.710 79.105 ;
        RECT 321.530 78.770 332.230 79.105 ;
        RECT 333.050 78.770 343.750 79.105 ;
        RECT 344.570 78.770 355.270 79.105 ;
        RECT 356.090 78.770 366.790 79.105 ;
        RECT 367.610 78.770 378.310 79.105 ;
        RECT 379.130 78.770 389.830 79.105 ;
        RECT 390.650 78.770 401.350 79.105 ;
        RECT 402.170 78.770 412.870 79.105 ;
        RECT 413.690 78.770 424.390 79.105 ;
        RECT 425.210 78.770 435.910 79.105 ;
        RECT 436.730 78.770 447.430 79.105 ;
        RECT 448.250 78.770 458.950 79.105 ;
        RECT 459.770 78.770 473.350 79.105 ;
        RECT 474.170 78.770 484.870 79.105 ;
        RECT 485.690 78.770 496.390 79.105 ;
        RECT 497.210 78.770 507.910 79.105 ;
        RECT 508.730 78.770 519.430 79.105 ;
        RECT 520.250 78.770 530.950 79.105 ;
        RECT 531.770 78.770 542.470 79.105 ;
        RECT 543.290 78.770 553.990 79.105 ;
        RECT 554.810 78.770 565.510 79.105 ;
        RECT 566.330 78.770 577.030 79.105 ;
        RECT 577.850 78.770 588.550 79.105 ;
        RECT 589.370 78.770 600.070 79.105 ;
        RECT 600.890 78.770 611.590 79.105 ;
        RECT 612.410 78.770 623.110 79.105 ;
        RECT 623.930 78.770 634.630 79.105 ;
        RECT 635.450 78.770 646.150 79.105 ;
        RECT 646.970 78.770 657.670 79.105 ;
        RECT 658.490 78.770 669.190 79.105 ;
        RECT 670.010 78.770 680.710 79.105 ;
        RECT 681.530 78.770 692.230 79.105 ;
        RECT 693.050 78.770 706.630 79.105 ;
        RECT 707.450 78.770 718.150 79.105 ;
        RECT 718.970 78.770 729.670 79.105 ;
        RECT 730.490 78.770 741.190 79.105 ;
        RECT 742.010 78.770 752.710 79.105 ;
        RECT 753.530 78.770 764.230 79.105 ;
        RECT 765.050 78.770 775.750 79.105 ;
        RECT 776.570 78.770 787.270 79.105 ;
        RECT 788.090 78.770 798.790 79.105 ;
        RECT 799.610 78.770 810.310 79.105 ;
        RECT 811.130 78.770 821.830 79.105 ;
        RECT 822.650 78.770 833.350 79.105 ;
        RECT 834.170 78.770 844.870 79.105 ;
        RECT 845.690 78.770 856.390 79.105 ;
        RECT 857.210 78.770 867.910 79.105 ;
        RECT 868.730 78.770 879.430 79.105 ;
        RECT 880.250 78.770 890.950 79.105 ;
        RECT 891.770 78.770 902.470 79.105 ;
        RECT 903.290 78.770 913.990 79.105 ;
        RECT 914.810 78.770 925.510 79.105 ;
        RECT 926.330 78.770 937.990 79.105 ;
        RECT 938.810 78.770 939.910 79.105 ;
        RECT 940.730 78.770 941.830 79.105 ;
        RECT 942.650 78.770 943.750 79.105 ;
        RECT 944.570 78.770 945.670 79.105 ;
        RECT 946.490 78.770 947.590 79.105 ;
        RECT 948.410 78.770 949.510 79.105 ;
        RECT 950.330 78.770 951.430 79.105 ;
        RECT 952.250 78.770 953.350 79.105 ;
        RECT 954.170 78.770 955.270 79.105 ;
        RECT 956.090 78.770 957.190 79.105 ;
        RECT 958.010 78.770 959.110 79.105 ;
        RECT 959.930 78.770 961.030 79.105 ;
        RECT 961.850 78.770 962.950 79.105 ;
        RECT 963.770 78.770 964.870 79.105 ;
        RECT 965.690 78.770 966.790 79.105 ;
        RECT 967.610 78.770 968.710 79.105 ;
        RECT 969.530 78.770 970.630 79.105 ;
        RECT 971.450 78.770 972.550 79.105 ;
        RECT 973.370 78.770 974.470 79.105 ;
        RECT 975.290 78.770 993.670 79.105 ;
        RECT 994.490 78.770 995.590 79.105 ;
        RECT 996.410 78.770 997.510 79.105 ;
        RECT 998.330 78.770 999.430 79.105 ;
        RECT 1000.250 78.770 1001.350 79.105 ;
        RECT 1002.170 78.770 1003.270 79.105 ;
        RECT 1004.090 78.770 1005.190 79.105 ;
        RECT 1006.010 78.770 1007.110 79.105 ;
        RECT 1007.930 78.770 1009.030 79.105 ;
        RECT 1009.850 78.770 1010.950 79.105 ;
        RECT 1011.770 78.770 1012.870 79.105 ;
        RECT 1013.690 78.770 1014.790 79.105 ;
        RECT 1015.610 78.770 1016.710 79.105 ;
        RECT 1017.530 78.770 1018.630 79.105 ;
        RECT 1019.450 78.770 1020.550 79.105 ;
        RECT 1021.370 78.770 1022.470 79.105 ;
        RECT 1023.290 78.770 1024.390 79.105 ;
        RECT 1025.210 78.770 1026.310 79.105 ;
        RECT 1027.130 78.770 1028.230 79.105 ;
        RECT 1029.050 78.770 1030.150 79.105 ;
        RECT 1030.970 78.770 1032.070 79.105 ;
        RECT 1032.890 78.770 1033.990 79.105 ;
        RECT 1034.810 78.770 1035.910 79.105 ;
        RECT 1036.730 78.770 1037.830 79.105 ;
        RECT 1038.650 78.770 1039.750 79.105 ;
        RECT 1040.570 78.770 1041.670 79.105 ;
        RECT 1042.490 78.770 1043.590 79.105 ;
        RECT 1044.410 78.770 1045.510 79.105 ;
        RECT 1046.330 78.770 1047.430 79.105 ;
        RECT 1048.250 78.770 1049.350 79.105 ;
        RECT 1050.170 78.770 1051.270 79.105 ;
        RECT 1052.090 78.770 1053.190 79.105 ;
        RECT 1054.010 78.770 1055.110 79.105 ;
        RECT 1055.930 78.770 1057.030 79.105 ;
        RECT 1057.850 78.770 1058.950 79.105 ;
        RECT 1059.770 78.770 1060.870 79.105 ;
        RECT 1061.690 78.770 1062.790 79.105 ;
        RECT 1063.610 78.770 1064.710 79.105 ;
        RECT 1065.530 78.770 1066.630 79.105 ;
        RECT 1067.450 78.770 1068.550 79.105 ;
        RECT 1069.370 78.770 1070.470 79.105 ;
        RECT 1071.290 78.770 1072.390 79.105 ;
        RECT 1073.210 78.770 1074.310 79.105 ;
        RECT 1075.130 78.770 1076.230 79.105 ;
        RECT 1077.050 78.770 1078.150 79.105 ;
        RECT 1078.970 78.770 1080.070 79.105 ;
        RECT 1080.890 78.770 1081.990 79.105 ;
        RECT 1082.810 78.770 1083.910 79.105 ;
        RECT 1084.730 78.770 1085.830 79.105 ;
        RECT 1086.650 78.770 1087.750 79.105 ;
        RECT 1088.570 78.770 1089.670 79.105 ;
        RECT 1090.490 78.770 1091.590 79.105 ;
        RECT 1092.410 78.770 1093.510 79.105 ;
        RECT 1094.330 78.770 1095.430 79.105 ;
        RECT 1096.250 78.770 1097.350 79.105 ;
        RECT 1098.170 78.770 1099.270 79.105 ;
        RECT 1100.090 78.770 1101.190 79.105 ;
        RECT 1102.010 78.770 1103.110 79.105 ;
        RECT 1103.930 78.770 1105.030 79.105 ;
        RECT 1105.850 78.770 1106.950 79.105 ;
        RECT 1107.770 78.770 1108.870 79.105 ;
        RECT 1109.690 78.770 1110.790 79.105 ;
        RECT 1111.610 78.770 1112.710 79.105 ;
        RECT 1113.530 78.770 1114.630 79.105 ;
        RECT 1115.450 78.770 1116.550 79.105 ;
        RECT 1117.370 78.770 1118.470 79.105 ;
        RECT 1119.290 78.770 1120.390 79.105 ;
        RECT 1121.210 78.770 1122.310 79.105 ;
        RECT 1123.130 78.770 1124.230 79.105 ;
        RECT 1125.050 78.770 1126.150 79.105 ;
        RECT 1126.970 78.770 1128.070 79.105 ;
        RECT 1128.890 78.770 1129.990 79.105 ;
        RECT 1130.810 78.770 1131.910 79.105 ;
        RECT 1132.730 78.770 1133.830 79.105 ;
        RECT 1134.650 78.770 1135.750 79.105 ;
        RECT 1136.570 78.770 1137.670 79.105 ;
        RECT 1138.490 78.770 1139.590 79.105 ;
        RECT 1140.410 78.770 1141.510 79.105 ;
        RECT 1142.330 78.770 1143.430 79.105 ;
        RECT 1144.250 78.770 1145.350 79.105 ;
        RECT 1146.170 78.770 1147.270 79.105 ;
        RECT 1148.090 78.770 1149.190 79.105 ;
        RECT 1150.010 78.770 1151.110 79.105 ;
        RECT 1151.930 78.770 1166.025 79.105 ;
        RECT 0.375 0.610 1166.025 78.770 ;
        RECT 0.375 0.275 1.030 0.610 ;
        RECT 1.850 0.275 2.950 0.610 ;
        RECT 3.770 0.275 4.870 0.610 ;
        RECT 5.690 0.275 6.790 0.610 ;
        RECT 7.610 0.275 11.590 0.610 ;
        RECT 12.410 0.275 12.550 0.610 ;
        RECT 13.370 0.275 13.510 0.610 ;
        RECT 14.330 0.275 14.470 0.610 ;
        RECT 15.290 0.275 15.430 0.610 ;
        RECT 16.250 0.275 16.390 0.610 ;
        RECT 17.210 0.275 17.350 0.610 ;
        RECT 18.170 0.275 18.310 0.610 ;
        RECT 19.130 0.275 25.990 0.610 ;
        RECT 26.810 0.275 26.950 0.610 ;
        RECT 27.770 0.275 27.910 0.610 ;
        RECT 28.730 0.275 28.870 0.610 ;
        RECT 29.690 0.275 29.830 0.610 ;
        RECT 30.650 0.275 30.790 0.610 ;
        RECT 31.610 0.275 31.750 0.610 ;
        RECT 32.570 0.275 32.710 0.610 ;
        RECT 33.530 0.275 44.230 0.610 ;
        RECT 45.050 0.275 45.190 0.610 ;
        RECT 46.010 0.275 46.150 0.610 ;
        RECT 46.970 0.275 47.110 0.610 ;
        RECT 47.930 0.275 48.070 0.610 ;
        RECT 48.890 0.275 49.030 0.610 ;
        RECT 49.850 0.275 49.990 0.610 ;
        RECT 50.810 0.275 50.950 0.610 ;
        RECT 51.770 0.275 51.910 0.610 ;
        RECT 52.730 0.275 52.870 0.610 ;
        RECT 53.690 0.275 53.830 0.610 ;
        RECT 54.650 0.275 54.790 0.610 ;
        RECT 55.610 0.275 55.750 0.610 ;
        RECT 56.570 0.275 56.710 0.610 ;
        RECT 57.530 0.275 57.670 0.610 ;
        RECT 58.490 0.275 58.630 0.610 ;
        RECT 59.450 0.275 73.990 0.610 ;
        RECT 74.810 0.275 74.950 0.610 ;
        RECT 75.770 0.275 75.910 0.610 ;
        RECT 76.730 0.275 76.870 0.610 ;
        RECT 77.690 0.275 77.830 0.610 ;
        RECT 78.650 0.275 78.790 0.610 ;
        RECT 79.610 0.275 79.750 0.610 ;
        RECT 80.570 0.275 80.710 0.610 ;
        RECT 81.530 0.275 81.670 0.610 ;
        RECT 82.490 0.275 82.630 0.610 ;
        RECT 83.450 0.275 83.590 0.610 ;
        RECT 84.410 0.275 84.550 0.610 ;
        RECT 85.370 0.275 85.510 0.610 ;
        RECT 86.330 0.275 86.470 0.610 ;
        RECT 87.290 0.275 87.430 0.610 ;
        RECT 88.250 0.275 88.390 0.610 ;
        RECT 89.210 0.275 97.030 0.610 ;
        RECT 97.850 0.275 98.950 0.610 ;
        RECT 99.770 0.275 100.870 0.610 ;
        RECT 101.690 0.275 102.790 0.610 ;
        RECT 103.610 0.275 104.710 0.610 ;
        RECT 105.530 0.275 106.630 0.610 ;
        RECT 107.450 0.275 108.550 0.610 ;
        RECT 109.370 0.275 110.470 0.610 ;
        RECT 111.290 0.275 112.390 0.610 ;
        RECT 113.210 0.275 114.310 0.610 ;
        RECT 115.130 0.275 116.230 0.610 ;
        RECT 117.050 0.275 118.150 0.610 ;
        RECT 118.970 0.275 120.070 0.610 ;
        RECT 120.890 0.275 124.870 0.610 ;
        RECT 125.690 0.275 125.830 0.610 ;
        RECT 126.650 0.275 126.790 0.610 ;
        RECT 127.610 0.275 127.750 0.610 ;
        RECT 128.570 0.275 128.710 0.610 ;
        RECT 129.530 0.275 129.670 0.610 ;
        RECT 130.490 0.275 130.630 0.610 ;
        RECT 131.450 0.275 131.590 0.610 ;
        RECT 132.410 0.275 143.110 0.610 ;
        RECT 143.930 0.275 144.070 0.610 ;
        RECT 144.890 0.275 145.030 0.610 ;
        RECT 145.850 0.275 145.990 0.610 ;
        RECT 146.810 0.275 146.950 0.610 ;
        RECT 147.770 0.275 147.910 0.610 ;
        RECT 148.730 0.275 148.870 0.610 ;
        RECT 149.690 0.275 149.830 0.610 ;
        RECT 150.650 0.275 150.790 0.610 ;
        RECT 151.610 0.275 151.750 0.610 ;
        RECT 152.570 0.275 152.710 0.610 ;
        RECT 153.530 0.275 153.670 0.610 ;
        RECT 154.490 0.275 154.630 0.610 ;
        RECT 155.450 0.275 155.590 0.610 ;
        RECT 156.410 0.275 156.550 0.610 ;
        RECT 157.370 0.275 157.510 0.610 ;
        RECT 158.330 0.275 172.870 0.610 ;
        RECT 173.690 0.275 173.830 0.610 ;
        RECT 174.650 0.275 174.790 0.610 ;
        RECT 175.610 0.275 175.750 0.610 ;
        RECT 176.570 0.275 176.710 0.610 ;
        RECT 177.530 0.275 177.670 0.610 ;
        RECT 178.490 0.275 178.630 0.610 ;
        RECT 179.450 0.275 179.590 0.610 ;
        RECT 180.410 0.275 180.550 0.610 ;
        RECT 181.370 0.275 181.510 0.610 ;
        RECT 182.330 0.275 182.470 0.610 ;
        RECT 183.290 0.275 183.430 0.610 ;
        RECT 184.250 0.275 184.390 0.610 ;
        RECT 185.210 0.275 185.350 0.610 ;
        RECT 186.170 0.275 186.310 0.610 ;
        RECT 187.130 0.275 187.270 0.610 ;
        RECT 188.090 0.275 204.550 0.610 ;
        RECT 205.370 0.275 205.510 0.610 ;
        RECT 206.330 0.275 206.470 0.610 ;
        RECT 207.290 0.275 207.430 0.610 ;
        RECT 208.250 0.275 208.390 0.610 ;
        RECT 209.210 0.275 209.350 0.610 ;
        RECT 210.170 0.275 210.310 0.610 ;
        RECT 211.130 0.275 211.270 0.610 ;
        RECT 212.090 0.275 212.230 0.610 ;
        RECT 213.050 0.275 213.190 0.610 ;
        RECT 214.010 0.275 214.150 0.610 ;
        RECT 214.970 0.275 215.110 0.610 ;
        RECT 215.930 0.275 216.070 0.610 ;
        RECT 216.890 0.275 217.030 0.610 ;
        RECT 217.850 0.275 217.990 0.610 ;
        RECT 218.810 0.275 218.950 0.610 ;
        RECT 219.770 0.275 219.910 0.610 ;
        RECT 220.730 0.275 220.870 0.610 ;
        RECT 221.690 0.275 221.830 0.610 ;
        RECT 222.650 0.275 222.790 0.610 ;
        RECT 223.610 0.275 234.310 0.610 ;
        RECT 235.130 0.275 236.230 0.610 ;
        RECT 237.050 0.275 238.150 0.610 ;
        RECT 238.970 0.275 240.070 0.610 ;
        RECT 240.890 0.275 244.870 0.610 ;
        RECT 245.690 0.275 245.830 0.610 ;
        RECT 246.650 0.275 246.790 0.610 ;
        RECT 247.610 0.275 247.750 0.610 ;
        RECT 248.570 0.275 248.710 0.610 ;
        RECT 249.530 0.275 249.670 0.610 ;
        RECT 250.490 0.275 250.630 0.610 ;
        RECT 251.450 0.275 251.590 0.610 ;
        RECT 252.410 0.275 259.270 0.610 ;
        RECT 260.090 0.275 260.230 0.610 ;
        RECT 261.050 0.275 261.190 0.610 ;
        RECT 262.010 0.275 262.150 0.610 ;
        RECT 262.970 0.275 263.110 0.610 ;
        RECT 263.930 0.275 264.070 0.610 ;
        RECT 264.890 0.275 265.030 0.610 ;
        RECT 265.850 0.275 265.990 0.610 ;
        RECT 266.810 0.275 277.510 0.610 ;
        RECT 278.330 0.275 278.470 0.610 ;
        RECT 279.290 0.275 279.430 0.610 ;
        RECT 280.250 0.275 280.390 0.610 ;
        RECT 281.210 0.275 281.350 0.610 ;
        RECT 282.170 0.275 282.310 0.610 ;
        RECT 283.130 0.275 283.270 0.610 ;
        RECT 284.090 0.275 284.230 0.610 ;
        RECT 285.050 0.275 285.190 0.610 ;
        RECT 286.010 0.275 286.150 0.610 ;
        RECT 286.970 0.275 287.110 0.610 ;
        RECT 287.930 0.275 288.070 0.610 ;
        RECT 288.890 0.275 289.030 0.610 ;
        RECT 289.850 0.275 289.990 0.610 ;
        RECT 290.810 0.275 290.950 0.610 ;
        RECT 291.770 0.275 291.910 0.610 ;
        RECT 292.730 0.275 307.270 0.610 ;
        RECT 308.090 0.275 308.230 0.610 ;
        RECT 309.050 0.275 309.190 0.610 ;
        RECT 310.010 0.275 310.150 0.610 ;
        RECT 310.970 0.275 311.110 0.610 ;
        RECT 311.930 0.275 312.070 0.610 ;
        RECT 312.890 0.275 313.030 0.610 ;
        RECT 313.850 0.275 313.990 0.610 ;
        RECT 314.810 0.275 314.950 0.610 ;
        RECT 315.770 0.275 315.910 0.610 ;
        RECT 316.730 0.275 316.870 0.610 ;
        RECT 317.690 0.275 317.830 0.610 ;
        RECT 318.650 0.275 318.790 0.610 ;
        RECT 319.610 0.275 319.750 0.610 ;
        RECT 320.570 0.275 320.710 0.610 ;
        RECT 321.530 0.275 321.670 0.610 ;
        RECT 322.490 0.275 330.310 0.610 ;
        RECT 331.130 0.275 332.230 0.610 ;
        RECT 333.050 0.275 334.150 0.610 ;
        RECT 334.970 0.275 336.070 0.610 ;
        RECT 336.890 0.275 337.990 0.610 ;
        RECT 338.810 0.275 339.910 0.610 ;
        RECT 340.730 0.275 341.830 0.610 ;
        RECT 342.650 0.275 343.750 0.610 ;
        RECT 344.570 0.275 345.670 0.610 ;
        RECT 346.490 0.275 347.590 0.610 ;
        RECT 348.410 0.275 349.510 0.610 ;
        RECT 350.330 0.275 351.430 0.610 ;
        RECT 352.250 0.275 353.350 0.610 ;
        RECT 354.170 0.275 358.150 0.610 ;
        RECT 358.970 0.275 359.110 0.610 ;
        RECT 359.930 0.275 360.070 0.610 ;
        RECT 360.890 0.275 361.030 0.610 ;
        RECT 361.850 0.275 361.990 0.610 ;
        RECT 362.810 0.275 362.950 0.610 ;
        RECT 363.770 0.275 363.910 0.610 ;
        RECT 364.730 0.275 364.870 0.610 ;
        RECT 365.690 0.275 376.390 0.610 ;
        RECT 377.210 0.275 377.350 0.610 ;
        RECT 378.170 0.275 378.310 0.610 ;
        RECT 379.130 0.275 379.270 0.610 ;
        RECT 380.090 0.275 380.230 0.610 ;
        RECT 381.050 0.275 381.190 0.610 ;
        RECT 382.010 0.275 382.150 0.610 ;
        RECT 382.970 0.275 383.110 0.610 ;
        RECT 383.930 0.275 384.070 0.610 ;
        RECT 384.890 0.275 385.030 0.610 ;
        RECT 385.850 0.275 385.990 0.610 ;
        RECT 386.810 0.275 386.950 0.610 ;
        RECT 387.770 0.275 387.910 0.610 ;
        RECT 388.730 0.275 388.870 0.610 ;
        RECT 389.690 0.275 389.830 0.610 ;
        RECT 390.650 0.275 390.790 0.610 ;
        RECT 391.610 0.275 406.150 0.610 ;
        RECT 406.970 0.275 407.110 0.610 ;
        RECT 407.930 0.275 408.070 0.610 ;
        RECT 408.890 0.275 409.030 0.610 ;
        RECT 409.850 0.275 409.990 0.610 ;
        RECT 410.810 0.275 410.950 0.610 ;
        RECT 411.770 0.275 411.910 0.610 ;
        RECT 412.730 0.275 412.870 0.610 ;
        RECT 413.690 0.275 413.830 0.610 ;
        RECT 414.650 0.275 414.790 0.610 ;
        RECT 415.610 0.275 415.750 0.610 ;
        RECT 416.570 0.275 416.710 0.610 ;
        RECT 417.530 0.275 417.670 0.610 ;
        RECT 418.490 0.275 418.630 0.610 ;
        RECT 419.450 0.275 419.590 0.610 ;
        RECT 420.410 0.275 420.550 0.610 ;
        RECT 421.370 0.275 437.830 0.610 ;
        RECT 438.650 0.275 438.790 0.610 ;
        RECT 439.610 0.275 439.750 0.610 ;
        RECT 440.570 0.275 440.710 0.610 ;
        RECT 441.530 0.275 441.670 0.610 ;
        RECT 442.490 0.275 442.630 0.610 ;
        RECT 443.450 0.275 443.590 0.610 ;
        RECT 444.410 0.275 444.550 0.610 ;
        RECT 445.370 0.275 445.510 0.610 ;
        RECT 446.330 0.275 446.470 0.610 ;
        RECT 447.290 0.275 447.430 0.610 ;
        RECT 448.250 0.275 448.390 0.610 ;
        RECT 449.210 0.275 449.350 0.610 ;
        RECT 450.170 0.275 450.310 0.610 ;
        RECT 451.130 0.275 451.270 0.610 ;
        RECT 452.090 0.275 452.230 0.610 ;
        RECT 453.050 0.275 453.190 0.610 ;
        RECT 454.010 0.275 454.150 0.610 ;
        RECT 454.970 0.275 455.110 0.610 ;
        RECT 455.930 0.275 456.070 0.610 ;
        RECT 456.890 0.275 467.590 0.610 ;
        RECT 468.410 0.275 469.510 0.610 ;
        RECT 470.330 0.275 471.430 0.610 ;
        RECT 472.250 0.275 473.350 0.610 ;
        RECT 474.170 0.275 478.150 0.610 ;
        RECT 478.970 0.275 479.110 0.610 ;
        RECT 479.930 0.275 480.070 0.610 ;
        RECT 480.890 0.275 481.030 0.610 ;
        RECT 481.850 0.275 481.990 0.610 ;
        RECT 482.810 0.275 482.950 0.610 ;
        RECT 483.770 0.275 483.910 0.610 ;
        RECT 484.730 0.275 484.870 0.610 ;
        RECT 485.690 0.275 492.550 0.610 ;
        RECT 493.370 0.275 493.510 0.610 ;
        RECT 494.330 0.275 494.470 0.610 ;
        RECT 495.290 0.275 495.430 0.610 ;
        RECT 496.250 0.275 496.390 0.610 ;
        RECT 497.210 0.275 497.350 0.610 ;
        RECT 498.170 0.275 498.310 0.610 ;
        RECT 499.130 0.275 499.270 0.610 ;
        RECT 500.090 0.275 510.790 0.610 ;
        RECT 511.610 0.275 511.750 0.610 ;
        RECT 512.570 0.275 512.710 0.610 ;
        RECT 513.530 0.275 513.670 0.610 ;
        RECT 514.490 0.275 514.630 0.610 ;
        RECT 515.450 0.275 515.590 0.610 ;
        RECT 516.410 0.275 516.550 0.610 ;
        RECT 517.370 0.275 517.510 0.610 ;
        RECT 518.330 0.275 518.470 0.610 ;
        RECT 519.290 0.275 519.430 0.610 ;
        RECT 520.250 0.275 520.390 0.610 ;
        RECT 521.210 0.275 521.350 0.610 ;
        RECT 522.170 0.275 522.310 0.610 ;
        RECT 523.130 0.275 523.270 0.610 ;
        RECT 524.090 0.275 524.230 0.610 ;
        RECT 525.050 0.275 525.190 0.610 ;
        RECT 526.010 0.275 540.550 0.610 ;
        RECT 541.370 0.275 541.510 0.610 ;
        RECT 542.330 0.275 542.470 0.610 ;
        RECT 543.290 0.275 543.430 0.610 ;
        RECT 544.250 0.275 544.390 0.610 ;
        RECT 545.210 0.275 545.350 0.610 ;
        RECT 546.170 0.275 546.310 0.610 ;
        RECT 547.130 0.275 547.270 0.610 ;
        RECT 548.090 0.275 548.230 0.610 ;
        RECT 549.050 0.275 549.190 0.610 ;
        RECT 550.010 0.275 550.150 0.610 ;
        RECT 550.970 0.275 551.110 0.610 ;
        RECT 551.930 0.275 552.070 0.610 ;
        RECT 552.890 0.275 553.030 0.610 ;
        RECT 553.850 0.275 553.990 0.610 ;
        RECT 554.810 0.275 554.950 0.610 ;
        RECT 555.770 0.275 563.590 0.610 ;
        RECT 564.410 0.275 565.510 0.610 ;
        RECT 566.330 0.275 567.430 0.610 ;
        RECT 568.250 0.275 569.350 0.610 ;
        RECT 570.170 0.275 571.270 0.610 ;
        RECT 572.090 0.275 573.190 0.610 ;
        RECT 574.010 0.275 575.110 0.610 ;
        RECT 575.930 0.275 577.030 0.610 ;
        RECT 577.850 0.275 578.950 0.610 ;
        RECT 579.770 0.275 580.870 0.610 ;
        RECT 581.690 0.275 582.790 0.610 ;
        RECT 583.610 0.275 584.710 0.610 ;
        RECT 585.530 0.275 586.630 0.610 ;
        RECT 587.450 0.275 591.430 0.610 ;
        RECT 592.250 0.275 592.390 0.610 ;
        RECT 593.210 0.275 593.350 0.610 ;
        RECT 594.170 0.275 594.310 0.610 ;
        RECT 595.130 0.275 595.270 0.610 ;
        RECT 596.090 0.275 596.230 0.610 ;
        RECT 597.050 0.275 597.190 0.610 ;
        RECT 598.010 0.275 598.150 0.610 ;
        RECT 598.970 0.275 609.670 0.610 ;
        RECT 610.490 0.275 610.630 0.610 ;
        RECT 611.450 0.275 611.590 0.610 ;
        RECT 612.410 0.275 612.550 0.610 ;
        RECT 613.370 0.275 613.510 0.610 ;
        RECT 614.330 0.275 614.470 0.610 ;
        RECT 615.290 0.275 615.430 0.610 ;
        RECT 616.250 0.275 616.390 0.610 ;
        RECT 617.210 0.275 617.350 0.610 ;
        RECT 618.170 0.275 618.310 0.610 ;
        RECT 619.130 0.275 619.270 0.610 ;
        RECT 620.090 0.275 620.230 0.610 ;
        RECT 621.050 0.275 621.190 0.610 ;
        RECT 622.010 0.275 622.150 0.610 ;
        RECT 622.970 0.275 623.110 0.610 ;
        RECT 623.930 0.275 624.070 0.610 ;
        RECT 624.890 0.275 639.430 0.610 ;
        RECT 640.250 0.275 640.390 0.610 ;
        RECT 641.210 0.275 641.350 0.610 ;
        RECT 642.170 0.275 642.310 0.610 ;
        RECT 643.130 0.275 643.270 0.610 ;
        RECT 644.090 0.275 644.230 0.610 ;
        RECT 645.050 0.275 645.190 0.610 ;
        RECT 646.010 0.275 646.150 0.610 ;
        RECT 646.970 0.275 647.110 0.610 ;
        RECT 647.930 0.275 648.070 0.610 ;
        RECT 648.890 0.275 649.030 0.610 ;
        RECT 649.850 0.275 649.990 0.610 ;
        RECT 650.810 0.275 650.950 0.610 ;
        RECT 651.770 0.275 651.910 0.610 ;
        RECT 652.730 0.275 652.870 0.610 ;
        RECT 653.690 0.275 653.830 0.610 ;
        RECT 654.650 0.275 671.110 0.610 ;
        RECT 671.930 0.275 672.070 0.610 ;
        RECT 672.890 0.275 673.030 0.610 ;
        RECT 673.850 0.275 673.990 0.610 ;
        RECT 674.810 0.275 674.950 0.610 ;
        RECT 675.770 0.275 675.910 0.610 ;
        RECT 676.730 0.275 676.870 0.610 ;
        RECT 677.690 0.275 677.830 0.610 ;
        RECT 678.650 0.275 678.790 0.610 ;
        RECT 679.610 0.275 679.750 0.610 ;
        RECT 680.570 0.275 680.710 0.610 ;
        RECT 681.530 0.275 681.670 0.610 ;
        RECT 682.490 0.275 682.630 0.610 ;
        RECT 683.450 0.275 683.590 0.610 ;
        RECT 684.410 0.275 684.550 0.610 ;
        RECT 685.370 0.275 685.510 0.610 ;
        RECT 686.330 0.275 686.470 0.610 ;
        RECT 687.290 0.275 687.430 0.610 ;
        RECT 688.250 0.275 688.390 0.610 ;
        RECT 689.210 0.275 689.350 0.610 ;
        RECT 690.170 0.275 700.870 0.610 ;
        RECT 701.690 0.275 702.790 0.610 ;
        RECT 703.610 0.275 704.710 0.610 ;
        RECT 705.530 0.275 706.630 0.610 ;
        RECT 707.450 0.275 711.430 0.610 ;
        RECT 712.250 0.275 712.390 0.610 ;
        RECT 713.210 0.275 713.350 0.610 ;
        RECT 714.170 0.275 714.310 0.610 ;
        RECT 715.130 0.275 715.270 0.610 ;
        RECT 716.090 0.275 716.230 0.610 ;
        RECT 717.050 0.275 717.190 0.610 ;
        RECT 718.010 0.275 718.150 0.610 ;
        RECT 718.970 0.275 725.830 0.610 ;
        RECT 726.650 0.275 726.790 0.610 ;
        RECT 727.610 0.275 727.750 0.610 ;
        RECT 728.570 0.275 728.710 0.610 ;
        RECT 729.530 0.275 729.670 0.610 ;
        RECT 730.490 0.275 730.630 0.610 ;
        RECT 731.450 0.275 731.590 0.610 ;
        RECT 732.410 0.275 732.550 0.610 ;
        RECT 733.370 0.275 744.070 0.610 ;
        RECT 744.890 0.275 745.030 0.610 ;
        RECT 745.850 0.275 745.990 0.610 ;
        RECT 746.810 0.275 746.950 0.610 ;
        RECT 747.770 0.275 747.910 0.610 ;
        RECT 748.730 0.275 748.870 0.610 ;
        RECT 749.690 0.275 749.830 0.610 ;
        RECT 750.650 0.275 750.790 0.610 ;
        RECT 751.610 0.275 751.750 0.610 ;
        RECT 752.570 0.275 752.710 0.610 ;
        RECT 753.530 0.275 753.670 0.610 ;
        RECT 754.490 0.275 754.630 0.610 ;
        RECT 755.450 0.275 755.590 0.610 ;
        RECT 756.410 0.275 756.550 0.610 ;
        RECT 757.370 0.275 757.510 0.610 ;
        RECT 758.330 0.275 758.470 0.610 ;
        RECT 759.290 0.275 773.830 0.610 ;
        RECT 774.650 0.275 774.790 0.610 ;
        RECT 775.610 0.275 775.750 0.610 ;
        RECT 776.570 0.275 776.710 0.610 ;
        RECT 777.530 0.275 777.670 0.610 ;
        RECT 778.490 0.275 778.630 0.610 ;
        RECT 779.450 0.275 779.590 0.610 ;
        RECT 780.410 0.275 780.550 0.610 ;
        RECT 781.370 0.275 781.510 0.610 ;
        RECT 782.330 0.275 782.470 0.610 ;
        RECT 783.290 0.275 783.430 0.610 ;
        RECT 784.250 0.275 784.390 0.610 ;
        RECT 785.210 0.275 785.350 0.610 ;
        RECT 786.170 0.275 786.310 0.610 ;
        RECT 787.130 0.275 787.270 0.610 ;
        RECT 788.090 0.275 788.230 0.610 ;
        RECT 789.050 0.275 796.870 0.610 ;
        RECT 797.690 0.275 798.790 0.610 ;
        RECT 799.610 0.275 800.710 0.610 ;
        RECT 801.530 0.275 802.630 0.610 ;
        RECT 803.450 0.275 804.550 0.610 ;
        RECT 805.370 0.275 806.470 0.610 ;
        RECT 807.290 0.275 808.390 0.610 ;
        RECT 809.210 0.275 810.310 0.610 ;
        RECT 811.130 0.275 812.230 0.610 ;
        RECT 813.050 0.275 814.150 0.610 ;
        RECT 814.970 0.275 816.070 0.610 ;
        RECT 816.890 0.275 817.990 0.610 ;
        RECT 818.810 0.275 819.910 0.610 ;
        RECT 820.730 0.275 824.710 0.610 ;
        RECT 825.530 0.275 825.670 0.610 ;
        RECT 826.490 0.275 826.630 0.610 ;
        RECT 827.450 0.275 827.590 0.610 ;
        RECT 828.410 0.275 828.550 0.610 ;
        RECT 829.370 0.275 829.510 0.610 ;
        RECT 830.330 0.275 830.470 0.610 ;
        RECT 831.290 0.275 831.430 0.610 ;
        RECT 832.250 0.275 842.950 0.610 ;
        RECT 843.770 0.275 843.910 0.610 ;
        RECT 844.730 0.275 844.870 0.610 ;
        RECT 845.690 0.275 845.830 0.610 ;
        RECT 846.650 0.275 846.790 0.610 ;
        RECT 847.610 0.275 847.750 0.610 ;
        RECT 848.570 0.275 848.710 0.610 ;
        RECT 849.530 0.275 849.670 0.610 ;
        RECT 850.490 0.275 850.630 0.610 ;
        RECT 851.450 0.275 851.590 0.610 ;
        RECT 852.410 0.275 852.550 0.610 ;
        RECT 853.370 0.275 853.510 0.610 ;
        RECT 854.330 0.275 854.470 0.610 ;
        RECT 855.290 0.275 855.430 0.610 ;
        RECT 856.250 0.275 856.390 0.610 ;
        RECT 857.210 0.275 857.350 0.610 ;
        RECT 858.170 0.275 872.710 0.610 ;
        RECT 873.530 0.275 873.670 0.610 ;
        RECT 874.490 0.275 874.630 0.610 ;
        RECT 875.450 0.275 875.590 0.610 ;
        RECT 876.410 0.275 876.550 0.610 ;
        RECT 877.370 0.275 877.510 0.610 ;
        RECT 878.330 0.275 878.470 0.610 ;
        RECT 879.290 0.275 879.430 0.610 ;
        RECT 880.250 0.275 880.390 0.610 ;
        RECT 881.210 0.275 881.350 0.610 ;
        RECT 882.170 0.275 882.310 0.610 ;
        RECT 883.130 0.275 883.270 0.610 ;
        RECT 884.090 0.275 884.230 0.610 ;
        RECT 885.050 0.275 885.190 0.610 ;
        RECT 886.010 0.275 886.150 0.610 ;
        RECT 886.970 0.275 887.110 0.610 ;
        RECT 887.930 0.275 904.390 0.610 ;
        RECT 905.210 0.275 905.350 0.610 ;
        RECT 906.170 0.275 906.310 0.610 ;
        RECT 907.130 0.275 907.270 0.610 ;
        RECT 908.090 0.275 908.230 0.610 ;
        RECT 909.050 0.275 909.190 0.610 ;
        RECT 910.010 0.275 910.150 0.610 ;
        RECT 910.970 0.275 911.110 0.610 ;
        RECT 911.930 0.275 912.070 0.610 ;
        RECT 912.890 0.275 913.030 0.610 ;
        RECT 913.850 0.275 913.990 0.610 ;
        RECT 914.810 0.275 914.950 0.610 ;
        RECT 915.770 0.275 915.910 0.610 ;
        RECT 916.730 0.275 916.870 0.610 ;
        RECT 917.690 0.275 917.830 0.610 ;
        RECT 918.650 0.275 918.790 0.610 ;
        RECT 919.610 0.275 919.750 0.610 ;
        RECT 920.570 0.275 920.710 0.610 ;
        RECT 921.530 0.275 921.670 0.610 ;
        RECT 922.490 0.275 922.630 0.610 ;
        RECT 923.450 0.275 934.150 0.610 ;
        RECT 934.970 0.275 936.070 0.610 ;
        RECT 936.890 0.275 937.990 0.610 ;
        RECT 938.810 0.275 939.910 0.610 ;
        RECT 940.730 0.275 944.710 0.610 ;
        RECT 945.530 0.275 945.670 0.610 ;
        RECT 946.490 0.275 946.630 0.610 ;
        RECT 947.450 0.275 947.590 0.610 ;
        RECT 948.410 0.275 948.550 0.610 ;
        RECT 949.370 0.275 949.510 0.610 ;
        RECT 950.330 0.275 950.470 0.610 ;
        RECT 951.290 0.275 951.430 0.610 ;
        RECT 952.250 0.275 959.110 0.610 ;
        RECT 959.930 0.275 960.070 0.610 ;
        RECT 960.890 0.275 961.030 0.610 ;
        RECT 961.850 0.275 961.990 0.610 ;
        RECT 962.810 0.275 962.950 0.610 ;
        RECT 963.770 0.275 963.910 0.610 ;
        RECT 964.730 0.275 964.870 0.610 ;
        RECT 965.690 0.275 965.830 0.610 ;
        RECT 966.650 0.275 977.350 0.610 ;
        RECT 978.170 0.275 978.310 0.610 ;
        RECT 979.130 0.275 979.270 0.610 ;
        RECT 980.090 0.275 980.230 0.610 ;
        RECT 981.050 0.275 981.190 0.610 ;
        RECT 982.010 0.275 982.150 0.610 ;
        RECT 982.970 0.275 983.110 0.610 ;
        RECT 983.930 0.275 984.070 0.610 ;
        RECT 984.890 0.275 985.030 0.610 ;
        RECT 985.850 0.275 985.990 0.610 ;
        RECT 986.810 0.275 986.950 0.610 ;
        RECT 987.770 0.275 987.910 0.610 ;
        RECT 988.730 0.275 988.870 0.610 ;
        RECT 989.690 0.275 989.830 0.610 ;
        RECT 990.650 0.275 990.790 0.610 ;
        RECT 991.610 0.275 991.750 0.610 ;
        RECT 992.570 0.275 1007.110 0.610 ;
        RECT 1007.930 0.275 1008.070 0.610 ;
        RECT 1008.890 0.275 1009.030 0.610 ;
        RECT 1009.850 0.275 1009.990 0.610 ;
        RECT 1010.810 0.275 1010.950 0.610 ;
        RECT 1011.770 0.275 1011.910 0.610 ;
        RECT 1012.730 0.275 1012.870 0.610 ;
        RECT 1013.690 0.275 1013.830 0.610 ;
        RECT 1014.650 0.275 1014.790 0.610 ;
        RECT 1015.610 0.275 1015.750 0.610 ;
        RECT 1016.570 0.275 1016.710 0.610 ;
        RECT 1017.530 0.275 1017.670 0.610 ;
        RECT 1018.490 0.275 1018.630 0.610 ;
        RECT 1019.450 0.275 1019.590 0.610 ;
        RECT 1020.410 0.275 1020.550 0.610 ;
        RECT 1021.370 0.275 1021.510 0.610 ;
        RECT 1022.330 0.275 1030.150 0.610 ;
        RECT 1030.970 0.275 1032.070 0.610 ;
        RECT 1032.890 0.275 1033.990 0.610 ;
        RECT 1034.810 0.275 1035.910 0.610 ;
        RECT 1036.730 0.275 1037.830 0.610 ;
        RECT 1038.650 0.275 1039.750 0.610 ;
        RECT 1040.570 0.275 1041.670 0.610 ;
        RECT 1042.490 0.275 1043.590 0.610 ;
        RECT 1044.410 0.275 1045.510 0.610 ;
        RECT 1046.330 0.275 1047.430 0.610 ;
        RECT 1048.250 0.275 1049.350 0.610 ;
        RECT 1050.170 0.275 1051.270 0.610 ;
        RECT 1052.090 0.275 1053.190 0.610 ;
        RECT 1054.010 0.275 1057.990 0.610 ;
        RECT 1058.810 0.275 1058.950 0.610 ;
        RECT 1059.770 0.275 1059.910 0.610 ;
        RECT 1060.730 0.275 1060.870 0.610 ;
        RECT 1061.690 0.275 1061.830 0.610 ;
        RECT 1062.650 0.275 1062.790 0.610 ;
        RECT 1063.610 0.275 1063.750 0.610 ;
        RECT 1064.570 0.275 1064.710 0.610 ;
        RECT 1065.530 0.275 1076.230 0.610 ;
        RECT 1077.050 0.275 1077.190 0.610 ;
        RECT 1078.010 0.275 1078.150 0.610 ;
        RECT 1078.970 0.275 1079.110 0.610 ;
        RECT 1079.930 0.275 1080.070 0.610 ;
        RECT 1080.890 0.275 1081.030 0.610 ;
        RECT 1081.850 0.275 1081.990 0.610 ;
        RECT 1082.810 0.275 1082.950 0.610 ;
        RECT 1083.770 0.275 1083.910 0.610 ;
        RECT 1084.730 0.275 1084.870 0.610 ;
        RECT 1085.690 0.275 1085.830 0.610 ;
        RECT 1086.650 0.275 1086.790 0.610 ;
        RECT 1087.610 0.275 1087.750 0.610 ;
        RECT 1088.570 0.275 1088.710 0.610 ;
        RECT 1089.530 0.275 1089.670 0.610 ;
        RECT 1090.490 0.275 1090.630 0.610 ;
        RECT 1091.450 0.275 1105.990 0.610 ;
        RECT 1106.810 0.275 1106.950 0.610 ;
        RECT 1107.770 0.275 1107.910 0.610 ;
        RECT 1108.730 0.275 1108.870 0.610 ;
        RECT 1109.690 0.275 1109.830 0.610 ;
        RECT 1110.650 0.275 1110.790 0.610 ;
        RECT 1111.610 0.275 1111.750 0.610 ;
        RECT 1112.570 0.275 1112.710 0.610 ;
        RECT 1113.530 0.275 1113.670 0.610 ;
        RECT 1114.490 0.275 1114.630 0.610 ;
        RECT 1115.450 0.275 1115.590 0.610 ;
        RECT 1116.410 0.275 1116.550 0.610 ;
        RECT 1117.370 0.275 1117.510 0.610 ;
        RECT 1118.330 0.275 1118.470 0.610 ;
        RECT 1119.290 0.275 1119.430 0.610 ;
        RECT 1120.250 0.275 1120.390 0.610 ;
        RECT 1121.210 0.275 1137.670 0.610 ;
        RECT 1138.490 0.275 1138.630 0.610 ;
        RECT 1139.450 0.275 1139.590 0.610 ;
        RECT 1140.410 0.275 1140.550 0.610 ;
        RECT 1141.370 0.275 1141.510 0.610 ;
        RECT 1142.330 0.275 1142.470 0.610 ;
        RECT 1143.290 0.275 1143.430 0.610 ;
        RECT 1144.250 0.275 1144.390 0.610 ;
        RECT 1145.210 0.275 1145.350 0.610 ;
        RECT 1146.170 0.275 1146.310 0.610 ;
        RECT 1147.130 0.275 1147.270 0.610 ;
        RECT 1148.090 0.275 1148.230 0.610 ;
        RECT 1149.050 0.275 1149.190 0.610 ;
        RECT 1150.010 0.275 1150.150 0.610 ;
        RECT 1150.970 0.275 1151.110 0.610 ;
        RECT 1151.930 0.275 1152.070 0.610 ;
        RECT 1152.890 0.275 1153.030 0.610 ;
        RECT 1153.850 0.275 1153.990 0.610 ;
        RECT 1154.810 0.275 1154.950 0.610 ;
        RECT 1155.770 0.275 1155.910 0.610 ;
        RECT 1156.730 0.275 1166.025 0.610 ;
      LAYER Metal3 ;
        RECT 0.335 68.030 1166.065 79.065 ;
        RECT 0.610 67.210 1165.790 68.030 ;
        RECT 0.335 66.350 1166.065 67.210 ;
        RECT 0.610 65.530 1165.790 66.350 ;
        RECT 0.335 64.670 1166.065 65.530 ;
        RECT 0.610 63.850 1165.790 64.670 ;
        RECT 0.335 62.990 1166.065 63.850 ;
        RECT 0.610 62.170 1165.790 62.990 ;
        RECT 0.335 61.310 1166.065 62.170 ;
        RECT 0.610 60.490 1165.790 61.310 ;
        RECT 0.335 59.630 1166.065 60.490 ;
        RECT 0.610 58.810 1165.790 59.630 ;
        RECT 0.335 57.950 1166.065 58.810 ;
        RECT 0.610 57.130 1165.790 57.950 ;
        RECT 0.335 56.270 1166.065 57.130 ;
        RECT 0.610 55.450 1165.790 56.270 ;
        RECT 0.335 54.590 1166.065 55.450 ;
        RECT 0.610 53.770 1165.790 54.590 ;
        RECT 0.335 52.910 1166.065 53.770 ;
        RECT 0.610 52.090 1165.790 52.910 ;
        RECT 0.335 51.230 1166.065 52.090 ;
        RECT 0.610 50.410 1165.790 51.230 ;
        RECT 0.335 49.550 1166.065 50.410 ;
        RECT 0.610 48.730 1165.790 49.550 ;
        RECT 0.335 47.870 1166.065 48.730 ;
        RECT 0.610 47.050 1165.790 47.870 ;
        RECT 0.335 46.190 1166.065 47.050 ;
        RECT 0.610 45.370 1165.790 46.190 ;
        RECT 0.335 44.510 1166.065 45.370 ;
        RECT 0.610 43.690 1165.790 44.510 ;
        RECT 0.335 42.830 1166.065 43.690 ;
        RECT 0.610 42.010 1165.790 42.830 ;
        RECT 0.335 41.150 1166.065 42.010 ;
        RECT 0.610 40.330 1165.790 41.150 ;
        RECT 0.335 39.470 1166.065 40.330 ;
        RECT 0.610 38.650 1165.790 39.470 ;
        RECT 0.335 37.790 1166.065 38.650 ;
        RECT 0.610 36.970 1165.790 37.790 ;
        RECT 0.335 36.110 1166.065 36.970 ;
        RECT 0.610 35.290 1165.790 36.110 ;
        RECT 0.335 34.430 1166.065 35.290 ;
        RECT 0.610 33.610 1165.790 34.430 ;
        RECT 0.335 32.750 1166.065 33.610 ;
        RECT 0.610 31.930 1165.790 32.750 ;
        RECT 0.335 31.070 1166.065 31.930 ;
        RECT 0.610 30.250 1165.790 31.070 ;
        RECT 0.335 29.390 1166.065 30.250 ;
        RECT 0.610 28.570 1165.790 29.390 ;
        RECT 0.335 27.710 1166.065 28.570 ;
        RECT 0.610 26.890 1165.790 27.710 ;
        RECT 0.335 26.030 1166.065 26.890 ;
        RECT 0.610 25.210 1165.790 26.030 ;
        RECT 0.335 24.350 1166.065 25.210 ;
        RECT 0.610 23.530 1165.790 24.350 ;
        RECT 0.335 22.670 1166.065 23.530 ;
        RECT 0.610 21.850 1165.790 22.670 ;
        RECT 0.335 20.990 1166.065 21.850 ;
        RECT 0.610 20.170 1165.790 20.990 ;
        RECT 0.335 19.310 1166.065 20.170 ;
        RECT 0.610 18.490 1165.790 19.310 ;
        RECT 0.335 17.630 1166.065 18.490 ;
        RECT 0.610 16.810 1165.790 17.630 ;
        RECT 0.335 15.950 1166.065 16.810 ;
        RECT 0.610 15.130 1165.790 15.950 ;
        RECT 0.335 2.510 1166.065 15.130 ;
        RECT 0.610 1.690 1165.790 2.510 ;
        RECT 0.335 0.315 1166.065 1.690 ;
      LAYER Metal4 ;
        RECT 7.100 0.275 12.170 79.105 ;
        RECT 13.590 0.275 15.170 79.105 ;
        RECT 16.590 0.275 62.170 79.105 ;
        RECT 63.590 0.275 65.170 79.105 ;
        RECT 66.590 0.275 112.170 79.105 ;
        RECT 113.590 0.275 115.170 79.105 ;
        RECT 116.590 0.275 162.170 79.105 ;
        RECT 163.590 0.275 165.170 79.105 ;
        RECT 166.590 0.275 212.170 79.105 ;
        RECT 213.590 0.275 215.170 79.105 ;
        RECT 216.590 0.275 245.450 79.105 ;
        RECT 246.870 0.275 248.450 79.105 ;
        RECT 249.870 0.275 295.450 79.105 ;
        RECT 296.870 0.275 298.450 79.105 ;
        RECT 299.870 0.275 345.450 79.105 ;
        RECT 346.870 0.275 348.450 79.105 ;
        RECT 349.870 0.275 395.450 79.105 ;
        RECT 396.870 0.275 398.450 79.105 ;
        RECT 399.870 0.275 445.450 79.105 ;
        RECT 446.870 0.275 448.450 79.105 ;
        RECT 449.870 0.275 478.730 79.105 ;
        RECT 480.150 0.275 481.730 79.105 ;
        RECT 483.150 0.275 528.730 79.105 ;
        RECT 530.150 0.275 531.730 79.105 ;
        RECT 533.150 0.275 578.730 79.105 ;
        RECT 580.150 0.275 581.730 79.105 ;
        RECT 583.150 0.275 628.730 79.105 ;
        RECT 630.150 0.275 631.730 79.105 ;
        RECT 633.150 0.275 678.730 79.105 ;
        RECT 680.150 0.275 681.730 79.105 ;
        RECT 683.150 0.275 712.010 79.105 ;
        RECT 713.430 0.275 715.010 79.105 ;
        RECT 716.430 0.275 762.010 79.105 ;
        RECT 763.430 0.275 765.010 79.105 ;
        RECT 766.430 0.275 812.010 79.105 ;
        RECT 813.430 0.275 815.010 79.105 ;
        RECT 816.430 0.275 862.010 79.105 ;
        RECT 863.430 0.275 865.010 79.105 ;
        RECT 866.430 0.275 912.010 79.105 ;
        RECT 913.430 0.275 915.010 79.105 ;
        RECT 916.430 0.275 945.290 79.105 ;
        RECT 946.710 0.275 948.290 79.105 ;
        RECT 949.710 0.275 995.290 79.105 ;
        RECT 996.710 0.275 998.290 79.105 ;
        RECT 999.710 0.275 1045.290 79.105 ;
        RECT 1046.710 0.275 1048.290 79.105 ;
        RECT 1049.710 0.275 1095.290 79.105 ;
        RECT 1096.710 0.275 1098.290 79.105 ;
        RECT 1099.710 0.275 1144.900 79.105 ;
      LAYER TopMetal1 ;
        RECT 7.340 3.100 1125.460 77.700 ;
  END
END NPU_ACCUM_N
END LIBRARY

